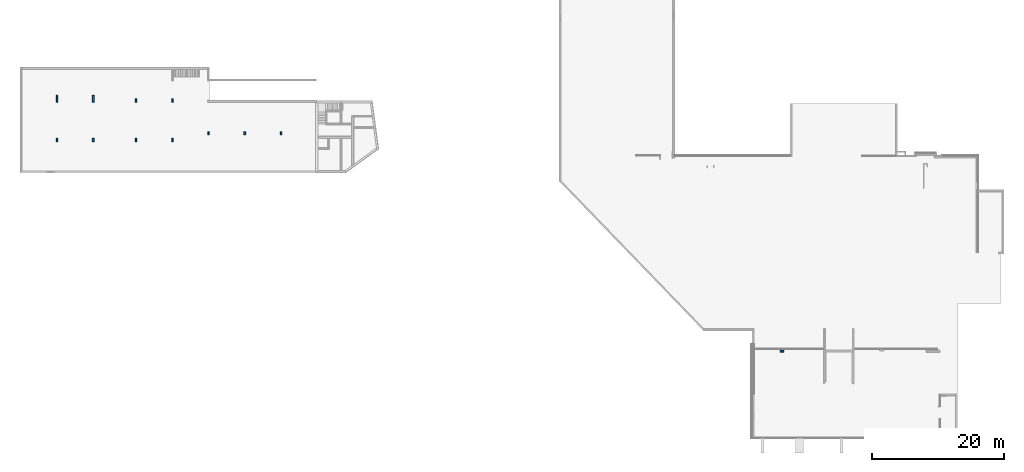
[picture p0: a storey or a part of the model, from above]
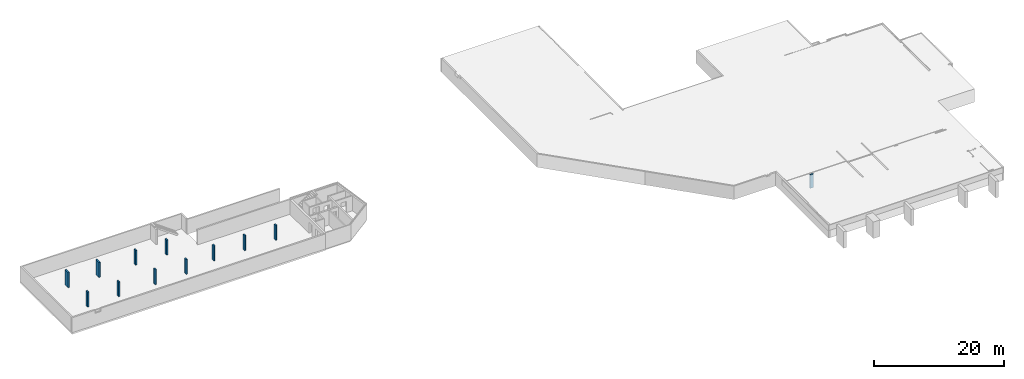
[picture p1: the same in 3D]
Properties of the parts of a building model (IFC2X3), part 1 of 4

# File
Description: ViewDefinition [CoordinationView_V2.0]
File name: X:\Daten\1-Firma\0-bv\Clemenz\18-019_Kandel Rheinstrasse\C a d\Transfair-DATEN\Test_181112.ifc
Time: 2018-11-12T08:55:23
Written by: EDMsix Version 2.0100.03 Feb 3 2016
Made in: Allplan 2017.1 19.09.2018 - 11:13:58

# IfcBuildingStorey (5)
In: Gebäude
Name | Elevation (mm)
Allgemein
KG.- Grundriss | -3205
EG.- Grundriss | -200
OG.- Grundriss | 2730
DG.- Grundriss | 5580

# IfcSpace (170)
InteriorOrExteriorSpace: INTERNAL
Allplan Attributes - Einheit: m²; Umschließungsart: a; Flächenart_DIN277: N; Flächenart_Wohnfläche: 1; BauNVO_Anrechnung_auf_GR: 0; Ortscode_Geschoßbezeichnung: 0-UG; BauNVO_Anrechnung_auf_GF: 0; Raum unter Treppe (Wohnfl erst ab 2m): 0; Faktor_Wohnfläche_Raum: 1; Faktor_DIN277: 1
Name | In | Description | LongName | Allright_Bauteil_ID | Nutzungsart_Din277 | Text2 | NOI_UUID
2-U.00.04 | KG.- Grundriss | Anstrich | Trockenraum | 0110Rau0000000851 | NF | Betonboden glatt | b6d4dd52-af4a-4a99-80c0-3d315f88db4b--851
1-U.01.07 | KG.- Grundriss | Anstrich | Müllraum | 0110Rau0000000320 | NF | Betonboden glatt | b6d4dd52-af4a-4a99-80c0-3d315f88db4b--320
1-U.00.03 | KG.- Grundriss | Anstrich | Schleuse1 | 0110Rau0000000425 | VF | Betonboden glatt | b6d4dd52-af4a-4a99-80c0-3d315f88db4b--425
0-U.00.01 | KG.- Grundriss | Anstrich | Tiefgarage | 0110Rau0000000002 | NF | Betonboden glatt | b6d4dd52-af4a-4a99-80c0-3d315f88db4b--2
0-U.00.02-2 | KG.- Grundriss | Anstrich | HAR | 0110Rau0000000212 | TF | Betonboden glatt | b6d4dd52-af4a-4a99-80c0-3d315f88db4b--212
1-U.00.01 | KG.- Grundriss | Werksteinbelag | Treppenhaus1 | 0110Rau0000000524 | VF | schw.Estrich | b6d4dd52-af4a-4a99-80c0-3d315f88db4b--524 | Allplan Attributes - Text3: Dämmung
1-U.00.02 | KG.- Grundriss | Belag | Aufzug1 | 0110Rau0000000629 | VF | schw.Estrich | b6d4dd52-af4a-4a99-80c0-3d315f88db4b--629 | Allplan Attributes - Text3: Trittschalld.
2-U.00.05 | KG.- Grundriss | Anstrich | Abstellraum | 0110Rau0000001094 | NF | Betonboden glatt | b6d4dd52-af4a-4a99-80c0-3d315f88db4b--1094
0-U.00.02-1 | KG.- Grundriss | Anstrich | Haustechnik | 0110Rau0000000107 | TF | Betonboden glatt | b6d4dd52-af4a-4a99-80c0-3d315f88db4b--107
0-U.00.02-2 | KG.- Grundriss | Anstrich | Haustechnik 2 | 0117Rau0781534050 | TF | Betonboden glatt | 09ef5a79-666f-4d65-ae11-371ec0050284--781534050 | Allplan Attributes - Faktor: 1
0-U.00.03 | KG.- Grundriss | Anstrich | Haustechnik 3 | 0117Rau0781533207 | TF | Betonboden glatt | 09ef5a79-666f-4d65-ae11-371ec0050284--781533207 | Allplan Attributes - Faktor: 1
0-U.00.02-1 | KG.- Grundriss | Anstrich | Haustechnik 1 | 0117Rau0781533084 | TF | Betonboden glatt | 09ef5a79-666f-4d65-ae11-371ec0050284--781533084 | Allplan Attributes - Faktor: 1
1-U.01.07 | KG.- Grundriss | Anstrich | Hausmeister | 0117Rau0781533926 | NF | schw.Estrich | 09ef5a79-666f-4d65-ae11-371ec0050284--781533926 | Allplan Attributes - Text3: Dämmung; Faktor: 1; Text4: Betonboden
1-U.00.02 | KG.- Grundriss | Belag | Aufzug1 | 0117Rau0781533922 | VF | schw.Estrich | 09ef5a79-666f-4d65-ae11-371ec0050284--781533922 | Allplan Attributes - Text3: Trittschalld.; Faktor: 1
1-U.00.01 | KG.- Grundriss | Werksteinbelag | Treppenhaus1 | 0117Rau0781533905 | VF | schw.Estrich | 09ef5a79-666f-4d65-ae11-371ec0050284--781533905 | Allplan Attributes - Text3: Dämmung; Faktor: 1
1-U.00.03 | KG.- Grundriss | schw.Estrich | Schleuse1 | 0117Rau0781533321 | VF | Dämmung | 09ef5a79-666f-4d65-ae11-371ec0050284--781533321 | Allplan Attributes - Faktor: 1
1-U.00.04 | KG.- Grundriss | Anstrich | Flur | 0117Rau0781533300 | VF | Betonboden glatt | 09ef5a79-666f-4d65-ae11-371ec0050284--781533300 | Allplan Attributes - Faktor: 1
0-U.00.02 | KG.- Grundriss | Anstrich | Müllraum | 0117Rau0781533278 | NF | Betonboden glatt | 09ef5a79-666f-4d65-ae11-371ec0050284--781533278 | Allplan Attributes - Faktor: 1
2-U.00.02 | KG.- Grundriss | Belag | Aufzug2 | 0117Rau0781533884 | VF | schw.Estrich | 09ef5a79-666f-4d65-ae11-371ec0050284--781533884 | Allplan Attributes - Text3: Trittschalld.; Faktor: 1
2-U.00.03 | KG.- Grundriss | schw.Estrich | Schleuse2 | 0117Rau0781533559 | VF | Dämmung | 09ef5a79-666f-4d65-ae11-371ec0050284--781533559 | Allplan Attributes - Faktor: 1
2-U.00.01 | KG.- Grundriss | Werksteinbelag | Treppenhaus2 | 0117Rau0781533556 | VF | schw.Estrich | 09ef5a79-666f-4d65-ae11-371ec0050284--781533556 | Allplan Attributes - Text3: Dämmung; Faktor: 1
2-U.00.04 | KG.- Grundriss | Anstrich | Abstellraum | 0117Rau0781533294 | NF | Betonboden glatt | 09ef5a79-666f-4d65-ae11-371ec0050284--781533294 | Allplan Attributes - Faktor: 1
2-U.00.05 | KG.- Grundriss | Anstrich | Flur | 0117Rau0781533275 | VF | Betonboden glatt | 09ef5a79-666f-4d65-ae11-371ec0050284--781533275 | Allplan Attributes - Faktor: 1
2-U.00.07 | KG.- Grundriss | schw.Estrich | Technik2 | 0117Rau0781533135 | TF | Dämmung | 09ef5a79-666f-4d65-ae11-371ec0050284--781533135 | Allplan Attributes - Faktor: 1
2-U.00.06 | KG.- Grundriss | Anstrich | Flur | 0117Rau0781533063 | VF | Betonboden glatt | 09ef5a79-666f-4d65-ae11-371ec0050284--781533063 | Allplan Attributes - Faktor: 1
3-U.00.01 | KG.- Grundriss | Werksteinbelag | Treppenhaus3 | 0117Rau0781533430 | VF | schw.Estrich | 09ef5a79-666f-4d65-ae11-371ec0050284--781533430 | Allplan Attributes - Text3: Dämmung; Faktor: 1
3-U.00.04 | KG.- Grundriss | schw.Estrich | Abstellraum | 0117Rau0781533296 | NF | Dämmung | 09ef5a79-666f-4d65-ae11-371ec0050284--781533296 | Allplan Attributes - Faktor: 1
3-U.00.06 | KG.- Grundriss | Anstrich | Flur | 0117Rau0781533292 | VF | Betonboden glatt | 09ef5a79-666f-4d65-ae11-371ec0050284--781533292 | Allplan Attributes - Faktor: 1
3-U.00.05a | KG.- Grundriss | Anstrich | Heizungs-Verteilung | 0117Rau0781533193 | TF | Betonboden glatt | 09ef5a79-666f-4d65-ae11-371ec0050284--781533193 | Allplan Attributes - Faktor: 1
3-U.00.05 | KG.- Grundriss | Anstrich | Technik3 | 0117Rau0781533145 | TF | Betonboden glatt | 09ef5a79-666f-4d65-ae11-371ec0050284--781533145 | Allplan Attributes - Faktor: 1
3-U.00.02 | KG.- Grundriss | Belag | Aufzug3 | 0117Rau0781532964 | VF | schw.Estrich | 09ef5a79-666f-4d65-ae11-371ec0050284--781532964 | Allplan Attributes - Text3: Trittschalld.; Faktor: 1
3-U.00.03 | KG.- Grundriss | schw.Estrich | Schleuse3 | 0117Rau0781532952 | VF | Dämmung | 09ef5a79-666f-4d65-ae11-371ec0050284--781532952 | Allplan Attributes - Faktor: 1
3-U.12 | KG.- Grundriss | Anstrich | Keller3.12 | 0117Rau0781533157 | NF | Betonboden glatt | 09ef5a79-666f-4d65-ae11-371ec0050284--781533157 | Allplan Attributes - Faktor: 1
3-U.13 | KG.- Grundriss | Anstrich | Keller3.13 | 0117Rau0781533154 | NF | Betonboden glatt | 09ef5a79-666f-4d65-ae11-371ec0050284--781533154 | Allplan Attributes - Faktor: 1
3-U.11 | KG.- Grundriss | Anstrich | Keller3.11 | 0117Rau0781533151 | NF | Betonboden glatt | 09ef5a79-666f-4d65-ae11-371ec0050284--781533151 | Allplan Attributes - Faktor: 1
3-U.10 | KG.- Grundriss | Anstrich | Keller3.10 | 0117Rau0781533148 | NF | Betonboden glatt | 09ef5a79-666f-4d65-ae11-371ec0050284--781533148 | Allplan Attributes - Faktor: 1
3-U.01 | KG.- Grundriss | Anstrich | Keller3.01 | 0117Rau0781533081 | NF | Betonboden glatt | 09ef5a79-666f-4d65-ae11-371ec0050284--781533081 | Allplan Attributes - Faktor: 1
3-U.02 | KG.- Grundriss | Anstrich | Keller3.02 | 0117Rau0781533072 | NF | Betonboden glatt | 09ef5a79-666f-4d65-ae11-371ec0050284--781533072 | Allplan Attributes - Faktor: 1
3-U.09 | KG.- Grundriss | Anstrich | Keller3.09 | 0117Rau0781533027 | NF | Betonboden glatt | 09ef5a79-666f-4d65-ae11-371ec0050284--781533027 | Allplan Attributes - Faktor: 1
3-U.08 | KG.- Grundriss | Anstrich | Keller3.08 | 0117Rau0781533018 | NF | Betonboden glatt | 09ef5a79-666f-4d65-ae11-371ec0050284--781533018 | Allplan Attributes - Faktor: 1
3-U.07 | KG.- Grundriss | Anstrich | Keller3.07 | 0117Rau0781533009 | NF | Betonboden glatt | 09ef5a79-666f-4d65-ae11-371ec0050284--781533009 | Allplan Attributes - Faktor: 1
3-U.06 | KG.- Grundriss | Anstrich | Keller3.06 | 0117Rau0781533000 | NF | Betonboden glatt | 09ef5a79-666f-4d65-ae11-371ec0050284--781533000 | Allplan Attributes - Faktor: 1
3-U.05 | KG.- Grundriss | Anstrich | Keller3.05 | 0117Rau0781532991 | NF | Betonboden glatt | 09ef5a79-666f-4d65-ae11-371ec0050284--781532991 | Allplan Attributes - Faktor: 1
3-U.03 | KG.- Grundriss | Anstrich | Keller3.03 | 0117Rau0781532982 | NF | Betonboden glatt | 09ef5a79-666f-4d65-ae11-371ec0050284--781532982 | Allplan Attributes - Faktor: 1
3-U.04 | KG.- Grundriss | Anstrich | Keller3.04 | 0117Rau0781532973 | NF | Betonboden glatt | 09ef5a79-666f-4d65-ae11-371ec0050284--781532973 | Allplan Attributes - Faktor: 1
2-U.01 | KG.- Grundriss | schw.Estrich | Keller2.01 | 0117Rau0781533265 | NF | Dämmung | 09ef5a79-666f-4d65-ae11-371ec0050284--781533265 | Allplan Attributes - Faktor: 1
2-U.03 | KG.- Grundriss | Anstrich | Keller2.03 | 0117Rau0781533262 | NF | Betonboden glatt | 09ef5a79-666f-4d65-ae11-371ec0050284--781533262 | Allplan Attributes - Faktor: 1
2-U.04 | KG.- Grundriss | Anstrich | Keller2.04 | 0117Rau0781533259 | NF | Betonboden glatt | 09ef5a79-666f-4d65-ae11-371ec0050284--781533259 | Allplan Attributes - Faktor: 1
2-U.07 | KG.- Grundriss | Anstrich | Keller2.07 | 0117Rau0781533132 | NF | Betonboden glatt | 09ef5a79-666f-4d65-ae11-371ec0050284--781533132 | Allplan Attributes - Faktor: 1
2-U.08 | KG.- Grundriss | Anstrich | Keller2.08 | 0117Rau0781533129 | NF | Betonboden glatt | 09ef5a79-666f-4d65-ae11-371ec0050284--781533129 | Allplan Attributes - Faktor: 1
2-U.11 | KG.- Grundriss | schw.Estrich | Keller2.11 | 0117Rau0781533126 | NF | Dämmung | 09ef5a79-666f-4d65-ae11-371ec0050284--781533126 | Allplan Attributes - Faktor: 1
2-U.10 | KG.- Grundriss | Anstrich | Keller2.10 | 0117Rau0781533123 | NF | Betonboden glatt | 09ef5a79-666f-4d65-ae11-371ec0050284--781533123 | Allplan Attributes - Faktor: 1
2-U.09 | KG.- Grundriss | Anstrich | Keller2.09 | 0117Rau0781533098 | NF | Betonboden glatt | 09ef5a79-666f-4d65-ae11-371ec0050284--781533098 | Allplan Attributes - Faktor: 1
2-U.02 | KG.- Grundriss | Anstrich | Keller2.02 | 0117Rau0781532961 | NF | Betonboden glatt | 09ef5a79-666f-4d65-ae11-371ec0050284--781532961 | Allplan Attributes - Faktor: 1
2-U.06 | KG.- Grundriss | Anstrich | Keller2.06 | 0117Rau0781532958 | NF | Betonboden glatt | 09ef5a79-666f-4d65-ae11-371ec0050284--781532958 | Allplan Attributes - Faktor: 1
2-U.05 | KG.- Grundriss | Anstrich | Keller2.05 | 0117Rau0781532955 | NF | Betonboden glatt | 09ef5a79-666f-4d65-ae11-371ec0050284--781532955 | Allplan Attributes - Faktor: 1
1-U.08 | KG.- Grundriss | Anstrich | Keller1.08 | 0117Rau0781533407 | NF | Betonboden glatt | 09ef5a79-666f-4d65-ae11-371ec0050284--781533407 | Allplan Attributes - Faktor: 1
1-U.09 | KG.- Grundriss | Anstrich | Keller1.09 | 0117Rau0781533404 | NF | Betonboden glatt | 09ef5a79-666f-4d65-ae11-371ec0050284--781533404 | Allplan Attributes - Faktor: 1
1-U.10 | KG.- Grundriss | Anstrich | Keller1.10 | 0117Rau0781533401 | NF | Betonboden glatt | 09ef5a79-666f-4d65-ae11-371ec0050284--781533401 | Allplan Attributes - Faktor: 1
1-U.11 | KG.- Grundriss | Anstrich | Keller1.11 | 0117Rau0781533383 | NF | Betonboden glatt | 09ef5a79-666f-4d65-ae11-371ec0050284--781533383 | Allplan Attributes - Faktor: 1
1-U.01 | KG.- Grundriss | Anstrich | Keller1.01 | 0117Rau0781533060 | NF | Betonboden glatt | 09ef5a79-666f-4d65-ae11-371ec0050284--781533060 | Allplan Attributes - Faktor: 1
1-U.02 | KG.- Grundriss | Anstrich | Keller1.02 | 0117Rau0781533057 | NF | Betonboden glatt | 09ef5a79-666f-4d65-ae11-371ec0050284--781533057 | Allplan Attributes - Faktor: 1
1-U.03 | KG.- Grundriss | Anstrich | Keller1.03 | 0117Rau0781533054 | NF | Betonboden glatt | 09ef5a79-666f-4d65-ae11-371ec0050284--781533054 | Allplan Attributes - Faktor: 1
1-U.04 | KG.- Grundriss | Anstrich | Keller1.04 | 0117Rau0781533051 | NF | Betonboden glatt | 09ef5a79-666f-4d65-ae11-371ec0050284--781533051 | Allplan Attributes - Faktor: 1
1-U.05 | KG.- Grundriss | Anstrich | Keller1.05 | 0117Rau0781533048 | NF | Betonboden glatt | 09ef5a79-666f-4d65-ae11-371ec0050284--781533048 | Allplan Attributes - Faktor: 1
1-U.14 | KG.- Grundriss | Anstrich | Keller1.14 | 0117Rau0781533045 | NF | Betonboden glatt | 09ef5a79-666f-4d65-ae11-371ec0050284--781533045 | Allplan Attributes - Faktor: 1
1-U.17 | KG.- Grundriss | Anstrich | Keller1.17 | 0117Rau0781533042 | NF | Betonboden glatt | 09ef5a79-666f-4d65-ae11-371ec0050284--781533042 | Allplan Attributes - Faktor: 1
1-U.16 | KG.- Grundriss | Anstrich | Keller1.16 | 0117Rau0781533039 | NF | Betonboden glatt | 09ef5a79-666f-4d65-ae11-371ec0050284--781533039 | Allplan Attributes - Faktor: 1
1-U.15 | KG.- Grundriss | Anstrich | Keller1.15 | 0117Rau0781533036 | NF | Betonboden glatt | 09ef5a79-666f-4d65-ae11-371ec0050284--781533036 | Allplan Attributes - Faktor: 1
1-U.13 | KG.- Grundriss | Anstrich | Keller1.13 | 0117Rau0781533033 | NF | Betonboden glatt | 09ef5a79-666f-4d65-ae11-371ec0050284--781533033 | Allplan Attributes - Faktor: 1
1-U.12 | KG.- Grundriss | Anstrich | Keller1.12 | 0117Rau0781533030 | NF | Betonboden glatt | 09ef5a79-666f-4d65-ae11-371ec0050284--781533030 | Allplan Attributes - Faktor: 1
0-U.00.01 | KG.- Grundriss | Anstrich | Tiefgarage | 0117Rau0781533466 | NF | Betonboden glatt | 09ef5a79-666f-4d65-ae11-371ec0050284--781533466 | Allplan Attributes - Faktor: 1
1-0.00.02 | EG.- Grundriss | Belag | Aufzug1 | 0210Rau0000001110 | VF | schw.Estrich | cb6ca373-0bca-4cb3-851c-22c560fc348a--1110 | Allplan Attributes - Text3: Trittschalld.
1-0.00.01 | EG.- Grundriss | Werksteinbelag | Treppenhaus1 | 0210Rau0000001113 | VF | schw.Estrich | cb6ca373-0bca-4cb3-851c-22c560fc348a--1113 | Allplan Attributes - Text3: Dämmung
1-0.00.28 | EG.- Grundriss | Anstrich | Abstellraum | 0210Rau0000004021 | NF | Betonboden glatt | cb6ca373-0bca-4cb3-851c-22c560fc348a--4021
1-0.00.09 | EG.- Grundriss | Anstrich | Raum | 0210Rau0000001909 | NF | Betonboden glatt | cb6ca373-0bca-4cb3-851c-22c560fc348a--1909
1-0.00.08 | EG.- Grundriss | Anstrich | Raum | 0210Rau0000001786 | NF | Betonboden glatt | cb6ca373-0bca-4cb3-851c-22c560fc348a--1786
1-0.00.05 | EG.- Grundriss | Anstrich | WC | 0210Rau0000001107 | NF | Betonboden glatt | cb6ca373-0bca-4cb3-851c-22c560fc348a--1107
1-0.00.07 | EG.- Grundriss | Anstrich | Teeküche | 0210Rau0000001687 | NF | Betonboden glatt | cb6ca373-0bca-4cb3-851c-22c560fc348a--1687
1-0.00.06 | EG.- Grundriss | Anstrich | Bad | 0210Rau0000001588 | NF | Betonboden glatt | cb6ca373-0bca-4cb3-851c-22c560fc348a--1588
1-0.00.05 | EG.- Grundriss | Anstrich | Wohnen/Essen/Kochen | 0210Rau0000001441 | NF | Betonboden glatt | cb6ca373-0bca-4cb3-851c-22c560fc348a--1441
1-0.00.05 | EG.- Grundriss | Anstrich | Abstr. | 0210Rau0000001408 | NF | Betonboden glatt | cb6ca373-0bca-4cb3-851c-22c560fc348a--1408
1-0.00.13 | EG.- Grundriss | Anstrich | Ankleide | 0210Rau0000002359 | NF | Betonboden glatt | cb6ca373-0bca-4cb3-851c-22c560fc348a--2359
1-0.00.11 | EG.- Grundriss | Anstrich | Bad | 0210Rau0000002131 | NF | Betonboden glatt | cb6ca373-0bca-4cb3-851c-22c560fc348a--2131
1-0.00.01 | EG.- Grundriss | Werksteinbelag | Treppenhaus2 | 0210Rau0000004441 | VF | schw.Estrich | cb6ca373-0bca-4cb3-851c-22c560fc348a--4441 | Allplan Attributes - Text3: Dämmung
1-0.00.10 | EG.- Grundriss | Anstrich | Flur | 0210Rau0000002032 | NF | Betonboden glatt | cb6ca373-0bca-4cb3-851c-22c560fc348a--2032
1-0.00.12 | EG.- Grundriss | Anstrich | Wohnen/Essen/Kochen | 0210Rau0000002230 | NF | Betonboden glatt | cb6ca373-0bca-4cb3-851c-22c560fc348a--2230
1-0.00.15 | EG.- Grundriss | Anstrich | Schlafen | 0210Rau0000002557 | NF | Betonboden glatt | cb6ca373-0bca-4cb3-851c-22c560fc348a--2557
1-0.00.19 | EG.- Grundriss | Anstrich | Flur | 0210Rau0000003001 | NF | Betonboden glatt | cb6ca373-0bca-4cb3-851c-22c560fc348a--3001
1-0.00.16 | EG.- Grundriss | Anstrich | Bad | 0210Rau0000002668 | NF | Betonboden glatt | cb6ca373-0bca-4cb3-851c-22c560fc348a--2668
1-0.00.17 | EG.- Grundriss | Anstrich | Schlafen | 0210Rau0000002767 | NF | Betonboden glatt | cb6ca373-0bca-4cb3-851c-22c560fc348a--2767
1-0.00.18 | EG.- Grundriss | Anstrich | Wohnen/Essen/Kochen | 0210Rau0000002884 | NF | Betonboden glatt | cb6ca373-0bca-4cb3-851c-22c560fc348a--2884
1-0.00.24 | EG.- Grundriss | Anstrich | Wohnen/Essen/Kochen | 0210Rau0000003514 | NF | Betonboden glatt | cb6ca373-0bca-4cb3-851c-22c560fc348a--3514
1-0.00.21 | EG.- Grundriss | Anstrich | Schlafen | 0210Rau0000003199 | NF | Betonboden glatt | cb6ca373-0bca-4cb3-851c-22c560fc348a--3199
1-0.00.20 | EG.- Grundriss | Anstrich | Flur | 0210Rau0000003100 | NF | Betonboden glatt | cb6ca373-0bca-4cb3-851c-22c560fc348a--3100
1-0.00.23 | EG.- Grundriss | Anstrich | Bad | 0210Rau0000003415 | NF | Betonboden glatt | cb6ca373-0bca-4cb3-851c-22c560fc348a--3415
1-0.00.22 | EG.- Grundriss | Anstrich | Abstr. | 0210Rau0000003316 | NF | Betonboden glatt | cb6ca373-0bca-4cb3-851c-22c560fc348a--3316
1-0.00.14 | EG.- Grundriss | Anstrich | Abstr. | 0210Rau0000002458 | NF | Betonboden glatt | cb6ca373-0bca-4cb3-851c-22c560fc348a--2458
1-0.00.25 | EG.- Grundriss | Anstrich | WC | 0210Rau0000003660 | NF | Betonboden glatt | cb6ca373-0bca-4cb3-851c-22c560fc348a--3660
1-0.00.27 | EG.- Grundriss | Anstrich | Kochen | 0210Rau0000004889 | NF | Betonboden glatt | cb6ca373-0bca-4cb3-851c-22c560fc348a--4889
1-0.00.30 | EG.- Grundriss | Anstrich | Wohnen/Essen | 0210Rau0000004219 | NF | Betonboden glatt | cb6ca373-0bca-4cb3-851c-22c560fc348a--4219
1-0.00.27 | EG.- Grundriss | Anstrich | Wohnen/Essen | 0210Rau0000003880 | NF | Betonboden glatt | cb6ca373-0bca-4cb3-851c-22c560fc348a--3880
1-0.00.29 | EG.- Grundriss | Anstrich | Kochen | 0210Rau0000004120 | NF | Betonboden glatt | cb6ca373-0bca-4cb3-851c-22c560fc348a--4120
1-0.00.32 | EG.- Grundriss | Anstrich | Abstr. | 0210Rau0000005164 | NF | Betonboden glatt | cb6ca373-0bca-4cb3-851c-22c560fc348a--5164
1-0.00.31 | EG.- Grundriss | Anstrich | Abstr. | 0210Rau0000005065 | NF | Betonboden glatt | cb6ca373-0bca-4cb3-851c-22c560fc348a--5065
1-0.00.31 | EG.- Grundriss | Anstrich | Diele | 0210Rau0000004330 | NF | Betonboden glatt | cb6ca373-0bca-4cb3-851c-22c560fc348a--4330
1-0.00.26 | EG.- Grundriss | Anstrich | Diele | 0210Rau0000003781 | NF | Betonboden glatt | cb6ca373-0bca-4cb3-851c-22c560fc348a--3781
1-0.00.14 | OG.- Grundriss | Anstrich | Abstr. | 0310Rau0000005811 | NF | Betonboden glatt | c8e704be-ccd8-4ce4-b42b-70ee46b7e8a9--5811
1-0.00.22 | OG.- Grundriss | Anstrich | Abstr. | 0310Rau0000005788 | NF | Betonboden glatt | c8e704be-ccd8-4ce4-b42b-70ee46b7e8a9--5788
1-0.00.23 | OG.- Grundriss | Anstrich | Bad | 0310Rau0000005765 | NF | Betonboden glatt | c8e704be-ccd8-4ce4-b42b-70ee46b7e8a9--5765
1-0.00.20 | OG.- Grundriss | Anstrich | Flur | 0310Rau0000005762 | NF | Betonboden glatt | c8e704be-ccd8-4ce4-b42b-70ee46b7e8a9--5762
1-0.00.21 | OG.- Grundriss | Anstrich | Schlafen | 0310Rau0000005719 | NF | Betonboden glatt | c8e704be-ccd8-4ce4-b42b-70ee46b7e8a9--5719
1-0.00.24 | OG.- Grundriss | Anstrich | Wohnen/Essen/Kochen | 0310Rau0000005696 | NF | Betonboden glatt | c8e704be-ccd8-4ce4-b42b-70ee46b7e8a9--5696
1-0.00.18 | OG.- Grundriss | Anstrich | Wohnen/Essen/Kochen | 0310Rau0000005673 | NF | Betonboden glatt | c8e704be-ccd8-4ce4-b42b-70ee46b7e8a9--5673
1-0.00.17 | OG.- Grundriss | Anstrich | Schlafen | 0310Rau0000005650 | NF | Betonboden glatt | c8e704be-ccd8-4ce4-b42b-70ee46b7e8a9--5650
1-0.00.16 | OG.- Grundriss | Anstrich | Bad | 0310Rau0000005627 | NF | Betonboden glatt | c8e704be-ccd8-4ce4-b42b-70ee46b7e8a9--5627
1-0.00.19 | OG.- Grundriss | Anstrich | Flur | 0310Rau0000005604 | NF | Betonboden glatt | c8e704be-ccd8-4ce4-b42b-70ee46b7e8a9--5604
1-0.00.15 | OG.- Grundriss | Anstrich | Schlafen | 0310Rau0000005581 | NF | Betonboden glatt | c8e704be-ccd8-4ce4-b42b-70ee46b7e8a9--5581
1-0.00.12 | OG.- Grundriss | Anstrich | Wohnen/Essen/Kochen | 0310Rau0000005558 | NF | Betonboden glatt | c8e704be-ccd8-4ce4-b42b-70ee46b7e8a9--5558
1-0.00.10 | OG.- Grundriss | Anstrich | Flur | 0310Rau0000005535 | NF | Betonboden glatt | c8e704be-ccd8-4ce4-b42b-70ee46b7e8a9--5535
1-0.00.01 | OG.- Grundriss | Werksteinbelag | Treppenhaus2 | 0310Rau0000005512 | VF | schw.Estrich | c8e704be-ccd8-4ce4-b42b-70ee46b7e8a9--5512 | Allplan Attributes - Text3: Dämmung
1-0.00.11 | OG.- Grundriss | Anstrich | Bad | 0310Rau0000005489 | NF | Betonboden glatt | c8e704be-ccd8-4ce4-b42b-70ee46b7e8a9--5489
1-0.00.13 | OG.- Grundriss | Anstrich | Ankleide | 0310Rau0000005466 | NF | Betonboden glatt | c8e704be-ccd8-4ce4-b42b-70ee46b7e8a9--5466
1-0.00.05 | OG.- Grundriss | Anstrich | Abstr. | 0310Rau0000005463 | NF | Betonboden glatt | c8e704be-ccd8-4ce4-b42b-70ee46b7e8a9--5463
1-0.00.05 | OG.- Grundriss | Anstrich | Wohnen/Essen/Kochen | 0310Rau0000005420 | NF | Betonboden glatt | c8e704be-ccd8-4ce4-b42b-70ee46b7e8a9--5420
1-0.00.06 | OG.- Grundriss | Anstrich | Bad | 0310Rau0000005397 | NF | Betonboden glatt | c8e704be-ccd8-4ce4-b42b-70ee46b7e8a9--5397
1-0.00.09 | OG.- Grundriss | Anstrich | Raum | 0310Rau0000005305 | NF | Betonboden glatt | c8e704be-ccd8-4ce4-b42b-70ee46b7e8a9--5305
1-0.00.01 | OG.- Grundriss | Werksteinbelag | Treppenhaus1 | 0310Rau0000005279 | VF | schw.Estrich | c8e704be-ccd8-4ce4-b42b-70ee46b7e8a9--5279 | Allplan Attributes - Text3: Dämmung
1-0.00.02 | OG.- Grundriss | Belag | Aufzug1 | 0310Rau0000005257 | VF | schw.Estrich | c8e704be-ccd8-4ce4-b42b-70ee46b7e8a9--5257 | Allplan Attributes - Text3: Trittschalld.
1-0.00.07 | OG.- Grundriss | Anstrich | Bad | 0310Rau0000005374 | NF | Betonboden glatt | c8e704be-ccd8-4ce4-b42b-70ee46b7e8a9--5374
1-0.00.05 | OG.- Grundriss | Anstrich | Abstr. | 0310Rau0000005371 | NF | Betonboden glatt | c8e704be-ccd8-4ce4-b42b-70ee46b7e8a9--5371
1-0.00.08 | OG.- Grundriss | Anstrich | Raum | 0310Rau0000005328 | NF | Betonboden glatt | c8e704be-ccd8-4ce4-b42b-70ee46b7e8a9--5328
1-0.00.31 | OG.- Grundriss | Anstrich | Flur | 0310Rau0000005999 | NF | Betonboden glatt | c8e704be-ccd8-4ce4-b42b-70ee46b7e8a9--5999
1-0.00.29 | OG.- Grundriss | Anstrich | Dusche | 0310Rau0000005930 | NF | Betonboden glatt | c8e704be-ccd8-4ce4-b42b-70ee46b7e8a9--5930
1-0.00.30 | OG.- Grundriss | Anstrich | Kind1 | 0310Rau0000006716 | NF | Betonboden glatt | c8e704be-ccd8-4ce4-b42b-70ee46b7e8a9--6716
1-0.00.30 | OG.- Grundriss | Anstrich | Kind2 | 0310Rau0000005884 | NF | Betonboden glatt | c8e704be-ccd8-4ce4-b42b-70ee46b7e8a9--5884
1-0.00.30 | OG.- Grundriss | Anstrich | Kind2 | 0310Rau0000006992 | NF | Betonboden glatt | c8e704be-ccd8-4ce4-b42b-70ee46b7e8a9--6992
1-0.00.30 | OG.- Grundriss | Anstrich | Kind1 | 0310Rau0000006970 | NF | Betonboden glatt | c8e704be-ccd8-4ce4-b42b-70ee46b7e8a9--6970
1-0.00.29 | OG.- Grundriss | Anstrich | Dusche | 0310Rau0000006968 | NF | Betonboden glatt | c8e704be-ccd8-4ce4-b42b-70ee46b7e8a9--6968
1-0.00.31 | OG.- Grundriss | Anstrich | Flur | 0310Rau0000006946 | NF | Betonboden glatt | c8e704be-ccd8-4ce4-b42b-70ee46b7e8a9--6946
1-0.00.11 | DG.- Grundriss | Anstrich | Bad | 0510Rau0000007544 | NF | Betonboden glatt | 5b11ceff-7c37-4271-a11e-d8302deba2a0--7544
1-0.00.01 | DG.- Grundriss | Werksteinbelag | Treppenhaus2 | 0510Rau0000007541 | VF | schw.Estrich | 5b11ceff-7c37-4271-a11e-d8302deba2a0--7541 | Allplan Attributes - Text3: Dämmung
1-0.00.30 | DG.- Grundriss | Anstrich | Kind1 | 0510Rau0000007728 | NF | Betonboden glatt | 5b11ceff-7c37-4271-a11e-d8302deba2a0--7728
1-0.00.30 | DG.- Grundriss | Anstrich | Kind1 | 0510Rau0000007679 | NF | Betonboden glatt | 5b11ceff-7c37-4271-a11e-d8302deba2a0--7679
1-0.00.31 | DG.- Grundriss | Anstrich | Flur | 0510Rau0000007734 | NF | Betonboden glatt | 5b11ceff-7c37-4271-a11e-d8302deba2a0--7734
1-0.00.31 | DG.- Grundriss | Anstrich | Flur | 0510Rau0000007653 | NF | Betonboden glatt | 5b11ceff-7c37-4271-a11e-d8302deba2a0--7653
1-0.00.29 | DG.- Grundriss | Anstrich | Dusche | 0510Rau0000007676 | NF | Betonboden glatt | 5b11ceff-7c37-4271-a11e-d8302deba2a0--7676
1-0.00.29 | DG.- Grundriss | Anstrich | Dusche | 0510Rau0000007731 | NF | Betonboden glatt | 5b11ceff-7c37-4271-a11e-d8302deba2a0--7731
1-0.00.14 | DG.- Grundriss | Anstrich | Abstr. | 0510Rau0000007502 | NF | Betonboden glatt | 5b11ceff-7c37-4271-a11e-d8302deba2a0--7502
1-0.00.15 | DG.- Grundriss | Anstrich | Schlafen | 0510Rau0000007532 | NF | Betonboden glatt | 5b11ceff-7c37-4271-a11e-d8302deba2a0--7532
1-0.00.21 | DG.- Grundriss | Anstrich | Dachterrasse ½ | 0510Rau0000007514 | NF | Betonboden glatt | 5b11ceff-7c37-4271-a11e-d8302deba2a0--7514
1-0.00.22 | DG.- Grundriss | Anstrich | Abstr. | 0510Rau0000007505 | NF | Betonboden glatt | 5b11ceff-7c37-4271-a11e-d8302deba2a0--7505
1-0.00.17 | DG.- Grundriss | Anstrich | Schlafen | 0510Rau0000007523 | NF | Betonboden glatt | 5b11ceff-7c37-4271-a11e-d8302deba2a0--7523
1-0.00.19 | DG.- Grundriss | Anstrich | Flur | 0510Rau0000007529 | NF | Betonboden glatt | 5b11ceff-7c37-4271-a11e-d8302deba2a0--7529
1-0.00.23 | DG.- Grundriss | Anstrich | Bad | 0510Rau0000007508 | NF | Betonboden glatt | 5b11ceff-7c37-4271-a11e-d8302deba2a0--7508
1-0.00.24 | DG.- Grundriss | Anstrich | Wohnen/Essen/Kochen | 0510Rau0000007517 | NF | Betonboden glatt | 5b11ceff-7c37-4271-a11e-d8302deba2a0--7517
1-0.00.22 | DG.- Grundriss | Anstrich | Kind | 0510Rau0000009184 | NF | Betonboden glatt | 5b11ceff-7c37-4271-a11e-d8302deba2a0--9184
1-0.00.12 | DG.- Grundriss | Anstrich | Wohnen/Essen/Kochen | 0510Rau0000007535 | NF | Betonboden glatt | 5b11ceff-7c37-4271-a11e-d8302deba2a0--7535
1-0.00.10 | DG.- Grundriss | Anstrich | Flur | 0510Rau0000007538 | NF | Betonboden glatt | 5b11ceff-7c37-4271-a11e-d8302deba2a0--7538
1-0.00.06 | DG.- Grundriss | Anstrich | Bad | 0510Rau0000007556 | NF | Betonboden glatt | 5b11ceff-7c37-4271-a11e-d8302deba2a0--7556
1-0.00.05 | DG.- Grundriss | Anstrich | Wohnen/Essen/Kochen | 0510Rau0000007553 | NF | Betonboden glatt | 5b11ceff-7c37-4271-a11e-d8302deba2a0--7553
1-0.00.01 | DG.- Grundriss | Werksteinbelag | Treppenhaus1 | 0510Rau0000007562 | VF | schw.Estrich | 5b11ceff-7c37-4271-a11e-d8302deba2a0--7562 | Allplan Attributes - Text3: Dämmung
1-0.00.05 | DG.- Grundriss | Anstrich | Abstr. | 0510Rau0000007591 | NF | Betonboden glatt | 5b11ceff-7c37-4271-a11e-d8302deba2a0--7591
1-0.00.15 | DG.- Grundriss | Anstrich | Schlafen | 0510Rau0000009638 | NF | Betonboden glatt | 5b11ceff-7c37-4271-a11e-d8302deba2a0--9638
1-0.00.05 | DG.- Grundriss | Anstrich | Abstr. | 0510Rau0000009683 | NF | Betonboden glatt | 5b11ceff-7c37-4271-a11e-d8302deba2a0--9683
1-0.00.05 | DG.- Grundriss | Anstrich | Abstr. | 0510Rau0000009745 | NF | Betonboden glatt | 5b11ceff-7c37-4271-a11e-d8302deba2a0--9745
1-0.00.05 | DG.- Grundriss | Anstrich | Abstr. | 0510Rau0000009776 | NF | Betonboden glatt | 5b11ceff-7c37-4271-a11e-d8302deba2a0--9776
1-0.00.05 | DG.- Grundriss | Anstrich | Abstr. | 0510Rau0000009807 | NF | Betonboden glatt | 5b11ceff-7c37-4271-a11e-d8302deba2a0--9807
1-0.00.05 | DG.- Grundriss | Anstrich | Abstr. | 0510Rau0000009838 | NF | Betonboden glatt | 5b11ceff-7c37-4271-a11e-d8302deba2a0--9838
1-0.00.05 | DG.- Grundriss | Anstrich | Abstr. | 0510Rau0000009869 | NF | Betonboden glatt | 5b11ceff-7c37-4271-a11e-d8302deba2a0--9869

# IfcBuildingElementProxy (11)
Material: <Unnamed Material>
Name | In
7 x 3D Element | Allgemein
4 x 3D Element | KG.- Grundriss

# IfcColumn (41)
In: KG.- Grundriss
Allplan Attributes - Umbaukategorie: Neubau; Einheit: m
Name | Material | Allright_Bauteil_ID | NOI_UUID
<Unnamed Element> | Stb-Stütze | 0100St 0780221014 | bb7460a6-57d8-45f2-954a-172a4282fe15--780221014 | Pset_ColumnCommon - LoadBearing: no; Allplan Attributes - Gewerk: Betonarbeiten
<Unnamed Element> | Stb-Stütze | 0100St 0780220911 | bb7460a6-57d8-45f2-954a-172a4282fe15--780220911 | Pset_ColumnCommon - LoadBearing: no; Allplan Attributes - Gewerk: Betonarbeiten
<Unnamed Element> | Stb-Stütze | 0100St 0780221021 | bb7460a6-57d8-45f2-954a-172a4282fe15--780221021 | Pset_ColumnCommon - LoadBearing: no; Allplan Attributes - Gewerk: Betonarbeiten
<Unnamed Element> | Stb-Stütze | 0100St 0780221020 | bb7460a6-57d8-45f2-954a-172a4282fe15--780221020 | Pset_ColumnCommon - LoadBearing: no; Allplan Attributes - Gewerk: Betonarbeiten
<Unnamed Element> | Stb-Stütze | 0100St 0780221019 | bb7460a6-57d8-45f2-954a-172a4282fe15--780221019 | Pset_ColumnCommon - LoadBearing: no; Allplan Attributes - Gewerk: Betonarbeiten
<Unnamed Element> | Stb-Stütze | 0100St 0780221018 | bb7460a6-57d8-45f2-954a-172a4282fe15--780221018 | Pset_ColumnCommon - LoadBearing: no; Allplan Attributes - Gewerk: Betonarbeiten
<Unnamed Element> | Stb-Stütze | 0100St 0780221017 | bb7460a6-57d8-45f2-954a-172a4282fe15--780221017 | Pset_ColumnCommon - LoadBearing: no; Allplan Attributes - Gewerk: Betonarbeiten
<Unnamed Element> | Stb-Stütze | 0100St 0780221016 | bb7460a6-57d8-45f2-954a-172a4282fe15--780221016 | Pset_ColumnCommon - LoadBearing: no; Allplan Attributes - Gewerk: Betonarbeiten
<Unnamed Element> | Stb-Stütze | 0100St 0780221015 | bb7460a6-57d8-45f2-954a-172a4282fe15--780221015 | Pset_ColumnCommon - LoadBearing: no; Allplan Attributes - Gewerk: Betonarbeiten
<Unnamed Element> | Stb-Stütze | 0100St 0780221013 | bb7460a6-57d8-45f2-954a-172a4282fe15--780221013 | Pset_ColumnCommon - LoadBearing: no; Allplan Attributes - Gewerk: Betonarbeiten
<Unnamed Element> | Stb-Stütze | 0100St 0780220474 | bb7460a6-57d8-45f2-954a-172a4282fe15--780220474 | Pset_ColumnCommon - LoadBearing: no; Allplan Attributes - Gewerk: Betonarbeiten
<Unnamed Element> | Stb-Stütze | 0117St 0781540728 | 09ef5a79-666f-4d65-ae11-371ec0050284--781540728
<Unnamed Element> | Stb-Stütze | 0117St 0781540726 | 09ef5a79-666f-4d65-ae11-371ec0050284--781540726
<Unnamed Element> | Stb-Wand | 0117St 0781540716 | 09ef5a79-666f-4d65-ae11-371ec0050284--781540716
<Unnamed Element> | Stb-Stütze | 0117St 0781540714 | 09ef5a79-666f-4d65-ae11-371ec0050284--781540714
<Unnamed Element> | Stb-Stütze | 0117St 0781540712 | 09ef5a79-666f-4d65-ae11-371ec0050284--781540712
<Unnamed Element> | Stb-Stütze | 0117St 0781540710 | 09ef5a79-666f-4d65-ae11-371ec0050284--781540710
<Unnamed Element> | Stb-Stütze | 0117St 0781540708 | 09ef5a79-666f-4d65-ae11-371ec0050284--781540708
<Unnamed Element> | Stb-Stütze | 0117St 0781540706 | 09ef5a79-666f-4d65-ae11-371ec0050284--781540706
<Unnamed Element> | Stb-Wand | 0117St 0781540704 | 09ef5a79-666f-4d65-ae11-371ec0050284--781540704
<Unnamed Element> | Stb-Stütze | 0117St 0781540702 | 09ef5a79-666f-4d65-ae11-371ec0050284--781540702
<Unnamed Element> | Stb-Stütze | 0117St 0781540700 | 09ef5a79-666f-4d65-ae11-371ec0050284--781540700
<Unnamed Element> | Stb-Stütze | 0117St 0781540698 | 09ef5a79-666f-4d65-ae11-371ec0050284--781540698
<Unnamed Element> | Stb-Stütze | 0117St 0781540696 | 09ef5a79-666f-4d65-ae11-371ec0050284--781540696
<Unnamed Element> | Stb-Stütze | 0117St 0781540694 | 09ef5a79-666f-4d65-ae11-371ec0050284--781540694
<Unnamed Element> | Stb-Stütze | 0117St 0781540692 | 09ef5a79-666f-4d65-ae11-371ec0050284--781540692
<Unnamed Element> | Stb-Stütze | 0117St 0781540690 | 09ef5a79-666f-4d65-ae11-371ec0050284--781540690
<Unnamed Element> | Stb-Stütze | 0117St 0781540688 | 09ef5a79-666f-4d65-ae11-371ec0050284--781540688
<Unnamed Element> | Stb-Stütze | 0117St 0781540686 | 09ef5a79-666f-4d65-ae11-371ec0050284--781540686
<Unnamed Element> | Stb-Stütze | 0117St 0781540684 | 09ef5a79-666f-4d65-ae11-371ec0050284--781540684
<Unnamed Element> | Stb-Stütze | 0117St 0781540682 | 09ef5a79-666f-4d65-ae11-371ec0050284--781540682
<Unnamed Element> | Stb-Stütze | 0117St 0781540680 | 09ef5a79-666f-4d65-ae11-371ec0050284--781540680
<Unnamed Element> | Stb-Stütze | 0117St 0781540678 | 09ef5a79-666f-4d65-ae11-371ec0050284--781540678
<Unnamed Element> | Stb-Stütze | 0117St 0781540676 | 09ef5a79-666f-4d65-ae11-371ec0050284--781540676
<Unnamed Element> | Stb-Stütze | 0117St 0781540674 | 09ef5a79-666f-4d65-ae11-371ec0050284--781540674
<Unnamed Element> | Stb-Stütze | 0117St 0781540672 | 09ef5a79-666f-4d65-ae11-371ec0050284--781540672
<Unnamed Element> | Stb-Stütze | 0117St 0781540660 | 09ef5a79-666f-4d65-ae11-371ec0050284--781540660
<Unnamed Element> | Stb-Stütze | 0117St 0781540658 | 09ef5a79-666f-4d65-ae11-371ec0050284--781540658
<Unnamed Element> | Stb-Stütze | 0117St 0781540652 | 09ef5a79-666f-4d65-ae11-371ec0050284--781540652
<Unnamed Element> | Stb-Stütze | 0117St 0781540650 | 09ef5a79-666f-4d65-ae11-371ec0050284--781540650
<Unnamed Element> | Stb-Wand | 0117St 0781540648 | 09ef5a79-666f-4d65-ae11-371ec0050284--781540648

# IfcDoor: Tür (4)
In: EG.- Grundriss
Type - OperationType: USERDEFINED; ParameterTakesPrecedence: no; Sizeable: no
OverallHeight: 2430 mm
Allplan Attributes - Einheit: St; V6: 0; V7: 0; V8: 0; V9: 0; Programmversion: 2.2; Bezeichnung: Tür; Plugin_Bezeichnung: MainObject; Plugin_Objektname: SmartPartCompressed; Version: 4.1; Einbauhöhe_Fensterbank_Außen: 0; Einbauhöhe_Fensterbank_Innen: 0; Abstand_Öffn_Unten: 0; Abstand_Öffn_Oben: 0; Abstand_Öffn_Links: 0; Abstand_Öffn_Rechts: 0; Abzug_Öffn_Unten: 70; Abzug_Öffn_Links: 70; Abzug_Öffn_Rechts: 70; Abzug_Öffn_Oben: 70
Name | OverallWidth (mm) | Allright_Bauteil_ID | NOI_UUID | Glasfläche
Tür | 1510 | 0200Mak0784438912 | 9eee6ca3-aa3f-4e17-bd40-2a040d5346dc--784438912 | 2.125
Tür | 1510 | 0200Mak0784438617 | 9eee6ca3-aa3f-4e17-bd40-2a040d5346dc--784438617 | 2.125
Tür | 1510 | 0200Mak0784440761 | 9eee6ca3-aa3f-4e17-bd40-2a040d5346dc--784440761 | 2.125
Tür | 1135 | 0200Mak0784440144 | 9eee6ca3-aa3f-4e17-bd40-2a040d5346dc--784440144 | 1.51845

# IfcDoor: m
In: DG.- Grundriss
Type - OperationType: SINGLE_SWING_LEFT; ParameterTakesPrecedence: no; Sizeable: no
OverallHeight: 2135 mm; OverallWidth: 900 mm
Allplan Attributes - Allright_Bauteil_ID: 0500Mak0784449447; UK: 0; OK: -999; Einheit: St; V6: 4; V7: 4; V8: 0; V9: 0; NOI_UUID: 1bfc5a75-329c-4bd5-adfb-044822b851e1--784449447

# IfcFooting (5)
In: KG.- Grundriss
PredefinedType: STRIP_FOOTING; Material: <Unnamed Material>
Allplan Attributes - Umbaukategorie: Neubau; Einheit: m³
Name | Allright_Bauteil_ID | NOI_UUID
<Unnamed Element> | 0117SFu0781530093 | 09ef5a79-666f-4d65-ae11-371ec0050284--781530093
<Unnamed Element> | 0117SFu0781530090 | 09ef5a79-666f-4d65-ae11-371ec0050284--781530090
<Unnamed Element> | 0117SFu0781530087 | 09ef5a79-666f-4d65-ae11-371ec0050284--781530087
<Unnamed Element> | 0117SFu0781530084 | 09ef5a79-666f-4d65-ae11-371ec0050284--781530084
<Unnamed Element> | 0117SFu0781530080 | 09ef5a79-666f-4d65-ae11-371ec0050284--781530080

# IfcOpeningElement: Opening (200)
Name | In | Object Layer Attributes #1, Allright_Bauteil_ID | Object Layer Attributes #1, Umbaukategorie | Object Layer Attributes #1, Einheit | Object Layer Attributes #1, Gewerk | Object Layer Attributes #1, NOI_UUID
Fensteröffnung | KG.- Grundriss | 0100Fen0780220470 | Neubau | m³ | Betonarbeiten | bb7460a6-57d8-45f2-954a-172a4282fe15--780220470
Türöffnung | KG.- Grundriss | 0100Tür0783113361 | Neubau | m² | Wärme- und Kältedämmarbeiten | bb7460a6-57d8-45f2-954a-172a4282fe15--783113361 | Allplan Attributes - Object Layer Attributes #2, Allright_Bauteil_ID: 0100Tür0783113362; Object Layer Attributes #2, Umbaukategorie: Neubau; Object Layer Attributes #2, Einheit: m³; Object Layer Attributes #2, Gewerk: Betonarbeiten; Object Layer Attributes #2, NOI_UUID: bb7460a6-57d8-45f2-954a-172a4282fe15--783113362
Türöffnung | KG.- Grundriss | 0100Tür0783113172 | Neubau | m² | Wärme- und Kältedämmarbeiten | bb7460a6-57d8-45f2-954a-172a4282fe15--783113172 | Allplan Attributes - Object Layer Attributes #2, Allright_Bauteil_ID: 0100Tür0783113171; Object Layer Attributes #2, Umbaukategorie: Neubau; Object Layer Attributes #2, Einheit: m³; Object Layer Attributes #2, Gewerk: Betonarbeiten; Object Layer Attributes #2, NOI_UUID: bb7460a6-57d8-45f2-954a-172a4282fe15--783113171
Türöffnung | KG.- Grundriss | 0100Tür0783113343 | Neubau | m³ | Betonarbeiten | bb7460a6-57d8-45f2-954a-172a4282fe15--783113343
Türöffnung | KG.- Grundriss | 0100Tür0783112759 |  | m³ | Betonarbeiten | bb7460a6-57d8-45f2-954a-172a4282fe15--783112759
Türöffnung | KG.- Grundriss | 0100Tür0783113336 | Neubau | m³ | Betonarbeiten | bb7460a6-57d8-45f2-954a-172a4282fe15--783113336
Türöffnung | KG.- Grundriss | 0100Tür0783113183 | Neubau | m³ | Betonarbeiten | bb7460a6-57d8-45f2-954a-172a4282fe15--783113183
Türöffnung | KG.- Grundriss | 0100Tür0783113190 | Neubau | m³ | Betonarbeiten | bb7460a6-57d8-45f2-954a-172a4282fe15--783113190
Türöffnung | KG.- Grundriss | 0100Tür0783113309 | Neubau | m³ | Mauerarbeiten | bb7460a6-57d8-45f2-954a-172a4282fe15--783113309
Fensteröffnung | KG.- Grundriss | 0117Fen0781540389 | Neubau | m³ |  | 09ef5a79-666f-4d65-ae11-371ec0050284--781540389
Fensteröffnung | KG.- Grundriss | 0117Fen0781540385 | Neubau | m³ |  | 09ef5a79-666f-4d65-ae11-371ec0050284--781540385
Fensteröffnung | KG.- Grundriss | 0117Fen0781540387 | Neubau | m³ |  | 09ef5a79-666f-4d65-ae11-371ec0050284--781540387
Fensteröffnung | KG.- Grundriss | 0117Fen0781540768 | Neubau | m³ |  | 09ef5a79-666f-4d65-ae11-371ec0050284--781540768
Fensteröffnung | KG.- Grundriss | 0117Fen0781540775 | Neubau | m³ |  | 09ef5a79-666f-4d65-ae11-371ec0050284--781540775
Deckendurchbruch | KG.- Grundriss | 0117Ddu0781530204 | Neubau | m² |  | 09ef5a79-666f-4d65-ae11-371ec0050284--781530204
Deckendurchbruch | KG.- Grundriss | 0117Ddu0781530206 | Neubau | m² |  | 09ef5a79-666f-4d65-ae11-371ec0050284--781530206
Deckenöffnung | KG.- Grundriss | 0117Ddu0781530208 |  | m² |  | 09ef5a79-666f-4d65-ae11-371ec0050284--781530208
Deckenöffnung | KG.- Grundriss | 0117Ddu0781530210 |  | m² |  | 09ef5a79-666f-4d65-ae11-371ec0050284--781530210
Deckenöffnung | KG.- Grundriss | 0117Ddu0781530212 |  | m² |  | 09ef5a79-666f-4d65-ae11-371ec0050284--781530212
Deckenöffnung | KG.- Grundriss | 0117Ddu0781530214 |  | m² |  | 09ef5a79-666f-4d65-ae11-371ec0050284--781530214
Deckendurchbruch | KG.- Grundriss | 0117Ddu0781530216 | Neubau | m² |  | 09ef5a79-666f-4d65-ae11-371ec0050284--781530216
Deckendurchbruch | KG.- Grundriss | 0117Ddu0781530218 | Neubau | m² |  | 09ef5a79-666f-4d65-ae11-371ec0050284--781530218
Fensteröffnung | EG.- Grundriss | 0200Fen0784438021 | Neubau | m³ | Wärmedämm-Verbundsysteme | 9eee6ca3-aa3f-4e17-bd40-2a040d5346dc--784438021
Fensteröffnung | EG.- Grundriss | 0200Fen0784437888 | Neubau | m³ | Wärmedämm-Verbundsysteme | 9eee6ca3-aa3f-4e17-bd40-2a040d5346dc--784437888
Fensteröffnung | EG.- Grundriss | 0200Fen0784437464 | Neubau | m³ | Wärmedämm-Verbundsysteme | 9eee6ca3-aa3f-4e17-bd40-2a040d5346dc--784437464
Fensteröffnung | EG.- Grundriss | 0200Fen0784438087 | Neubau | m³ | Wärmedämm-Verbundsysteme | 9eee6ca3-aa3f-4e17-bd40-2a040d5346dc--784438087
Fensteröffnung | EG.- Grundriss | 0200Fen0784438088 | Neubau | m³ | Wärmedämm-Verbundsysteme | 9eee6ca3-aa3f-4e17-bd40-2a040d5346dc--784438088
Fensteröffnung | EG.- Grundriss | 0200Fen0784438080 | Neubau | m³ | Wärmedämm-Verbundsysteme | 9eee6ca3-aa3f-4e17-bd40-2a040d5346dc--784438080
Türöffnung | EG.- Grundriss | 0200Tür0784438909 | Neubau | m³ | Mauerarbeiten | 9eee6ca3-aa3f-4e17-bd40-2a040d5346dc--784438909
Türöffnung | EG.- Grundriss | 0200Tür0784438558 | Neubau | m³ | Mauerarbeiten | 9eee6ca3-aa3f-4e17-bd40-2a040d5346dc--784438558
Fensteröffnung | EG.- Grundriss | 0200Fen0784438527 | Neubau | m³ | Wärmedämm-Verbundsysteme | 9eee6ca3-aa3f-4e17-bd40-2a040d5346dc--784438527
Fensteröffnung | EG.- Grundriss | 0200Fen0784438513 | Neubau | m³ | Wärmedämm-Verbundsysteme | 9eee6ca3-aa3f-4e17-bd40-2a040d5346dc--784438513
Fensteröffnung | EG.- Grundriss | 0200Fen0784440914 | Neubau | m³ | Wärmedämm-Verbundsysteme | 9eee6ca3-aa3f-4e17-bd40-2a040d5346dc--784440914
Fensteröffnung | EG.- Grundriss | 0200Fen0784440920 | Neubau | m³ | Wärmedämm-Verbundsysteme | 9eee6ca3-aa3f-4e17-bd40-2a040d5346dc--784440920
Fensteröffnung | EG.- Grundriss | 0200Fen0784440898 | Neubau | m³ | Wärmedämm-Verbundsysteme | 9eee6ca3-aa3f-4e17-bd40-2a040d5346dc--784440898
Fensteröffnung | EG.- Grundriss | 0200Fen0784440884 | Neubau | m³ | Wärmedämm-Verbundsysteme | 9eee6ca3-aa3f-4e17-bd40-2a040d5346dc--784440884
Fensteröffnung | EG.- Grundriss | 0200Fen0784439595 | Neubau | m³ | Wärmedämm-Verbundsysteme | 9eee6ca3-aa3f-4e17-bd40-2a040d5346dc--784439595
Fensteröffnung | EG.- Grundriss | 0200Fen0784439581 | Neubau | m³ | Wärmedämm-Verbundsysteme | 9eee6ca3-aa3f-4e17-bd40-2a040d5346dc--784439581
Fensteröffnung | EG.- Grundriss | 0200Fen0784439567 | Neubau | m³ | Wärmedämm-Verbundsysteme | 9eee6ca3-aa3f-4e17-bd40-2a040d5346dc--784439567
Fensteröffnung | EG.- Grundriss | 0200Fen0784439553 | Neubau | m³ | Wärmedämm-Verbundsysteme | 9eee6ca3-aa3f-4e17-bd40-2a040d5346dc--784439553
Fensteröffnung | EG.- Grundriss | 0200Fen0784439539 | Neubau | m³ | Wärmedämm-Verbundsysteme | 9eee6ca3-aa3f-4e17-bd40-2a040d5346dc--784439539
Fensteröffnung | EG.- Grundriss | 0200Fen0784439525 | Neubau | m³ | Wärmedämm-Verbundsysteme | 9eee6ca3-aa3f-4e17-bd40-2a040d5346dc--784439525
Fensteröffnung | EG.- Grundriss | 0200Fen0784439373 | Neubau | m³ | Wärmedämm-Verbundsysteme | 9eee6ca3-aa3f-4e17-bd40-2a040d5346dc--784439373
Fensteröffnung | EG.- Grundriss | 0200Fen0784439193 | Neubau | m³ | Wärmedämm-Verbundsysteme | 9eee6ca3-aa3f-4e17-bd40-2a040d5346dc--784439193
Fensteröffnung | EG.- Grundriss | 0200Fen0784439180 | Neubau | m³ | Wärmedämm-Verbundsysteme | 9eee6ca3-aa3f-4e17-bd40-2a040d5346dc--784439180
Fensteröffnung | EG.- Grundriss | 0200Fen0784439166 | Neubau | m³ | Wärmedämm-Verbundsysteme | 9eee6ca3-aa3f-4e17-bd40-2a040d5346dc--784439166
Fensteröffnung | EG.- Grundriss | 0200Fen0784439652 | Neubau | m³ | Wärmedämm-Verbundsysteme | 9eee6ca3-aa3f-4e17-bd40-2a040d5346dc--784439652
Fensteröffnung | EG.- Grundriss | 0200Fen0784439638 | Neubau | m³ | Wärmedämm-Verbundsysteme | 9eee6ca3-aa3f-4e17-bd40-2a040d5346dc--784439638
Fensteröffnung | EG.- Grundriss | 0200Fen0784439666 | Neubau | m³ | Mauerarbeiten | 9eee6ca3-aa3f-4e17-bd40-2a040d5346dc--784439666
Fensteröffnung | EG.- Grundriss | 0200Fen0784440054 | Neubau | m³ | Wärmedämm-Verbundsysteme | 9eee6ca3-aa3f-4e17-bd40-2a040d5346dc--784440054
Fensteröffnung | EG.- Grundriss | 0200Fen0784440776 | Neubau | m³ | Wärmedämm-Verbundsysteme | 9eee6ca3-aa3f-4e17-bd40-2a040d5346dc--784440776
Fensteröffnung | EG.- Grundriss | 0200Fen0784440869 | Neubau | m³ | Wärmedämm-Verbundsysteme | 9eee6ca3-aa3f-4e17-bd40-2a040d5346dc--784440869
Fensteröffnung | EG.- Grundriss | 0200Fen0784440790 | Neubau | m³ | Wärmedämm-Verbundsysteme | 9eee6ca3-aa3f-4e17-bd40-2a040d5346dc--784440790
Fensteröffnung | EG.- Grundriss | 0200Fen0784439029 | Neubau | m³ | Mauerarbeiten | 9eee6ca3-aa3f-4e17-bd40-2a040d5346dc--784439029
Fensteröffnung | EG.- Grundriss | 0200Fen0784434088 | Neubau | m³ | Mauerarbeiten | 9eee6ca3-aa3f-4e17-bd40-2a040d5346dc--784434088
Fensteröffnung | EG.- Grundriss | 0200Fen0784440762 | Neubau | m³ | Wärmedämm-Verbundsysteme | 9eee6ca3-aa3f-4e17-bd40-2a040d5346dc--784440762
Türöffnung | EG.- Grundriss | 0200Tür0784440747 | Neubau | m³ | Mauerarbeiten | 9eee6ca3-aa3f-4e17-bd40-2a040d5346dc--784440747
Türöffnung | EG.- Grundriss | 0200Tür0784441235 | Neubau | m³ | Mauerarbeiten | 9eee6ca3-aa3f-4e17-bd40-2a040d5346dc--784441235
Türöffnung | EG.- Grundriss | 0200Tür0784441242 | Neubau | m³ | Mauerarbeiten | 9eee6ca3-aa3f-4e17-bd40-2a040d5346dc--784441242
Türöffnung | EG.- Grundriss | 0200Tür0784435554 |  | m³ | Betonarbeiten | 9eee6ca3-aa3f-4e17-bd40-2a040d5346dc--784435554
Fensteröffnung | EG.- Grundriss | 0200Fen0784439676 | Neubau | m³ | Mauerarbeiten | 9eee6ca3-aa3f-4e17-bd40-2a040d5346dc--784439676
Türöffnung | EG.- Grundriss | 0200Tür0784440133 | Neubau | m³ | Mauerarbeiten | 9eee6ca3-aa3f-4e17-bd40-2a040d5346dc--784440133
Fensteröffnung | EG.- Grundriss | 0200Fen0784440733 | Neubau | m³ | Wärmedämm-Verbundsysteme | 9eee6ca3-aa3f-4e17-bd40-2a040d5346dc--784440733
Fensteröffnung | EG.- Grundriss | 0200Fen0784440719 | Neubau | m³ | Wärmedämm-Verbundsysteme | 9eee6ca3-aa3f-4e17-bd40-2a040d5346dc--784440719
Fensteröffnung | EG.- Grundriss | 0200Fen0784440200 | Neubau | m³ | Wärmedämm-Verbundsysteme | 9eee6ca3-aa3f-4e17-bd40-2a040d5346dc--784440200
Fensteröffnung | EG.- Grundriss | 0200Fen0784440186 | Neubau | m³ | Wärmedämm-Verbundsysteme | 9eee6ca3-aa3f-4e17-bd40-2a040d5346dc--784440186
Türöffnung | EG.- Grundriss | 0200Tür0784441063 | Neubau | m³ | Mauerarbeiten | 9eee6ca3-aa3f-4e17-bd40-2a040d5346dc--784441063
Türöffnung | EG.- Grundriss | 0200Tür0784441184 | Neubau | m³ | Mauerarbeiten | 9eee6ca3-aa3f-4e17-bd40-2a040d5346dc--784441184
Türöffnung | EG.- Grundriss | 0200Tür0784441191 | Neubau | m³ | Mauerarbeiten | 9eee6ca3-aa3f-4e17-bd40-2a040d5346dc--784441191
Türöffnung | EG.- Grundriss | 0200Tür0784441205 | Neubau | m³ | Mauerarbeiten | 9eee6ca3-aa3f-4e17-bd40-2a040d5346dc--784441205
Türöffnung | EG.- Grundriss | 0200Tür0784441198 | Neubau | m³ | Mauerarbeiten | 9eee6ca3-aa3f-4e17-bd40-2a040d5346dc--784441198
Türöffnung | EG.- Grundriss | 0200Tür0784441104 | Neubau | m³ | Mauerarbeiten | 9eee6ca3-aa3f-4e17-bd40-2a040d5346dc--784441104
Türöffnung | EG.- Grundriss | 0200Tür0784441097 | Neubau | m³ | Mauerarbeiten | 9eee6ca3-aa3f-4e17-bd40-2a040d5346dc--784441097
Türöffnung | EG.- Grundriss | 0200Tür0784441077 | Neubau | m³ | Mauerarbeiten | 9eee6ca3-aa3f-4e17-bd40-2a040d5346dc--784441077
Türöffnung | EG.- Grundriss | 0200Tür0784441070 | Neubau | m³ | Mauerarbeiten | 9eee6ca3-aa3f-4e17-bd40-2a040d5346dc--784441070
Türöffnung | EG.- Grundriss | 0200Tür0784441090 | Neubau | m³ | Mauerarbeiten | 9eee6ca3-aa3f-4e17-bd40-2a040d5346dc--784441090
Türöffnung | EG.- Grundriss | 0200Tür0784441515 | Neubau | m³ | Mauerarbeiten | 9eee6ca3-aa3f-4e17-bd40-2a040d5346dc--784441515
Türöffnung | EG.- Grundriss | 0200Tür0784441508 | Neubau | m³ | Mauerarbeiten | 9eee6ca3-aa3f-4e17-bd40-2a040d5346dc--784441508
Türöffnung | EG.- Grundriss | 0200Tür0784441529 | Neubau | m³ | Mauerarbeiten | 9eee6ca3-aa3f-4e17-bd40-2a040d5346dc--784441529
Türöffnung | EG.- Grundriss | 0200Tür0784441522 | Neubau | m³ | Mauerarbeiten | 9eee6ca3-aa3f-4e17-bd40-2a040d5346dc--784441522
Türöffnung | EG.- Grundriss | 0200Tür0784441212 | Neubau | m³ | Mauerarbeiten | 9eee6ca3-aa3f-4e17-bd40-2a040d5346dc--784441212
Türöffnung | EG.- Grundriss | 0200Tür0784441163 | Neubau | m³ | Mauerarbeiten | 9eee6ca3-aa3f-4e17-bd40-2a040d5346dc--784441163
Türöffnung | EG.- Grundriss | 0200Tür0784441219 | Neubau | m³ | Mauerarbeiten | 9eee6ca3-aa3f-4e17-bd40-2a040d5346dc--784441219
Türöffnung | EG.- Grundriss | 0200Tür0784441177 | Neubau | m³ | Mauerarbeiten | 9eee6ca3-aa3f-4e17-bd40-2a040d5346dc--784441177
Türöffnung | EG.- Grundriss | 0200Tür0784441228 | Neubau | m³ | Mauerarbeiten | 9eee6ca3-aa3f-4e17-bd40-2a040d5346dc--784441228
Türöffnung | EG.- Grundriss | 0200Tür0784441170 | Neubau | m³ | Mauerarbeiten | 9eee6ca3-aa3f-4e17-bd40-2a040d5346dc--784441170
Türöffnung | EG.- Grundriss | 0200Tür0784441022 | Neubau | m³ | Mauerarbeiten | 9eee6ca3-aa3f-4e17-bd40-2a040d5346dc--784441022
Türöffnung | EG.- Grundriss | 0200Tür0784441554 | Neubau | m³ | Mauerarbeiten | 9eee6ca3-aa3f-4e17-bd40-2a040d5346dc--784441554
Türöffnung | EG.- Grundriss | 0200Tür0784441585 | Neubau | m³ | Mauerarbeiten | 9eee6ca3-aa3f-4e17-bd40-2a040d5346dc--784441585
Türöffnung | EG.- Grundriss | 0200Tür0784441629 | Neubau | m³ | Mauerarbeiten | 9eee6ca3-aa3f-4e17-bd40-2a040d5346dc--784441629
Fensteröffnung | OG.- Grundriss | 0300Fen0784445547 | Neubau | m³ | Wärmedämm-Verbundsysteme | 92c99fbc-4ab2-4783-a754-1daa3fa43448--784445547
Fensteröffnung | OG.- Grundriss | 0300Fen0000000181 | Neubau | m³ | Wärmedämm-Verbundsysteme | 92c99fbc-4ab2-4783-a754-1daa3fa43448--181
Fensteröffnung | OG.- Grundriss | 0300Fen0000000175 | Neubau | m³ | Wärmedämm-Verbundsysteme | 92c99fbc-4ab2-4783-a754-1daa3fa43448--175
Fensteröffnung | OG.- Grundriss | 0300Fen0784445530 | Neubau | m³ | Wärmedämm-Verbundsysteme | 92c99fbc-4ab2-4783-a754-1daa3fa43448--784445530
Fensteröffnung | OG.- Grundriss | 0300Fen0000000169 | Neubau | m³ | Wärmedämm-Verbundsysteme | 92c99fbc-4ab2-4783-a754-1daa3fa43448--169
Fensteröffnung | OG.- Grundriss | 0300Fen0000000163 | Neubau | m³ | Wärmedämm-Verbundsysteme | 92c99fbc-4ab2-4783-a754-1daa3fa43448--163
Fensteröffnung | OG.- Grundriss | 0300Fen0784445404 | Neubau | m³ | Wärmedämm-Verbundsysteme | 92c99fbc-4ab2-4783-a754-1daa3fa43448--784445404
Fensteröffnung | OG.- Grundriss | 0300Fen0784445390 | Neubau | m³ | Wärmedämm-Verbundsysteme | 92c99fbc-4ab2-4783-a754-1daa3fa43448--784445390
Fensteröffnung | OG.- Grundriss | 0300Fen0000000485 | Neubau | m³ | Wärmedämm-Verbundsysteme | 92c99fbc-4ab2-4783-a754-1daa3fa43448--485
Fensteröffnung | OG.- Grundriss | 0300Fen0000000484 | Neubau | m³ | Wärmedämm-Verbundsysteme | 92c99fbc-4ab2-4783-a754-1daa3fa43448--484
Fensteröffnung | OG.- Grundriss | 0300Fen0000000340 | Neubau | m³ | Wärmedämm-Verbundsysteme | 92c99fbc-4ab2-4783-a754-1daa3fa43448--340
Fensteröffnung | OG.- Grundriss | 0300Fen0000000347 | Neubau | m³ | Wärmedämm-Verbundsysteme | 92c99fbc-4ab2-4783-a754-1daa3fa43448--347
Fensteröffnung | OG.- Grundriss | 0300Fen0784442894 | Neubau | m³ | Wärmedämm-Verbundsysteme | 92c99fbc-4ab2-4783-a754-1daa3fa43448--784442894
Fensteröffnung | OG.- Grundriss | 0300Fen0784442878 | Neubau | m³ | Wärmedämm-Verbundsysteme | 92c99fbc-4ab2-4783-a754-1daa3fa43448--784442878
Fensteröffnung | OG.- Grundriss | 0300Fen0784444739 | Neubau | m³ | Wärmedämm-Verbundsysteme | 92c99fbc-4ab2-4783-a754-1daa3fa43448--784444739
Fensteröffnung | OG.- Grundriss | 0300Fen0784444722 | Neubau | m³ | Wärmedämm-Verbundsysteme | 92c99fbc-4ab2-4783-a754-1daa3fa43448--784444722
Fensteröffnung | OG.- Grundriss | 0300Fen0000000321 | Neubau | m³ | Wärmedämm-Verbundsysteme | 92c99fbc-4ab2-4783-a754-1daa3fa43448--321
Fensteröffnung | OG.- Grundriss | 0300Fen0784445444 | Neubau | m³ | Wärmedämm-Verbundsysteme | 92c99fbc-4ab2-4783-a754-1daa3fa43448--784445444
Fensteröffnung | OG.- Grundriss | 0300Fen0784445474 | Neubau | m³ | Wärmedämm-Verbundsysteme | 92c99fbc-4ab2-4783-a754-1daa3fa43448--784445474
Fensteröffnung | OG.- Grundriss | 0300Fen0784445428 | Neubau | m³ | Wärmedämm-Verbundsysteme | 92c99fbc-4ab2-4783-a754-1daa3fa43448--784445428
Fensteröffnung | OG.- Grundriss | 0300Fen0784445460 | Neubau | m³ | Wärmedämm-Verbundsysteme | 92c99fbc-4ab2-4783-a754-1daa3fa43448--784445460
Fensteröffnung | OG.- Grundriss | 0300Fen0784442205 | Neubau | m³ | Mauerarbeiten | 92c99fbc-4ab2-4783-a754-1daa3fa43448--784442205
Fensteröffnung | OG.- Grundriss | 0300Fen0000000307 | Neubau | m³ | Wärmedämm-Verbundsysteme | 92c99fbc-4ab2-4783-a754-1daa3fa43448--307
Fensteröffnung | OG.- Grundriss | 0300Fen0784442083 | Neubau | m³ | Mauerarbeiten | 92c99fbc-4ab2-4783-a754-1daa3fa43448--784442083
Fensteröffnung | OG.- Grundriss | 0300Fen0784444797 | Neubau | m³ | Wärmedämm-Verbundsysteme | 92c99fbc-4ab2-4783-a754-1daa3fa43448--784444797
Türöffnung | OG.- Grundriss | 0300Tür0000000466 | Neubau | m³ | Mauerarbeiten | 92c99fbc-4ab2-4783-a754-1daa3fa43448--466
Türöffnung | OG.- Grundriss | 0300Tür0000000052 |  | m³ | Betonarbeiten | 92c99fbc-4ab2-4783-a754-1daa3fa43448--52
Fensteröffnung | OG.- Grundriss | 0300Fen0784444753 | Neubau | m³ | Wärmedämm-Verbundsysteme | 92c99fbc-4ab2-4783-a754-1daa3fa43448--784444753
Fensteröffnung | OG.- Grundriss | 0300Fen0784444783 | Neubau | m³ | Wärmedämm-Verbundsysteme | 92c99fbc-4ab2-4783-a754-1daa3fa43448--784444783
Fensteröffnung | OG.- Grundriss | 0300Fen0784444769 | Neubau | m³ | Wärmedämm-Verbundsysteme | 92c99fbc-4ab2-4783-a754-1daa3fa43448--784444769
Fensteröffnung | OG.- Grundriss | 0300Fen0000000296 | Neubau | m³ | Wärmedämm-Verbundsysteme | 92c99fbc-4ab2-4783-a754-1daa3fa43448--296
Fensteröffnung | OG.- Grundriss | 0300Fen0000000280 | Neubau | m³ | Wärmedämm-Verbundsysteme | 92c99fbc-4ab2-4783-a754-1daa3fa43448--280
Fensteröffnung | OG.- Grundriss | 0300Fen0000000274 | Neubau | m³ | Wärmedämm-Verbundsysteme | 92c99fbc-4ab2-4783-a754-1daa3fa43448--274
Türöffnung | OG.- Grundriss | 0300Tür0000000361 | Neubau | m³ | Mauerarbeiten | 92c99fbc-4ab2-4783-a754-1daa3fa43448--361
Türöffnung | OG.- Grundriss | 0300Tür0000000392 | Neubau | m³ | Mauerarbeiten | 92c99fbc-4ab2-4783-a754-1daa3fa43448--392
Türöffnung | OG.- Grundriss | 0300Tür0000000395 | Neubau | m³ | Mauerarbeiten | 92c99fbc-4ab2-4783-a754-1daa3fa43448--395
Türöffnung | OG.- Grundriss | 0300Tür0000000377 | Neubau | m³ | Mauerarbeiten | 92c99fbc-4ab2-4783-a754-1daa3fa43448--377
Türöffnung | OG.- Grundriss | 0300Tür0000000374 | Neubau | m³ | Mauerarbeiten | 92c99fbc-4ab2-4783-a754-1daa3fa43448--374
Türöffnung | OG.- Grundriss | 0300Tür0000000368 | Neubau | m³ | Mauerarbeiten | 92c99fbc-4ab2-4783-a754-1daa3fa43448--368
Türöffnung | OG.- Grundriss | 0300Tür0000000365 | Neubau | m³ | Mauerarbeiten | 92c99fbc-4ab2-4783-a754-1daa3fa43448--365
Türöffnung | OG.- Grundriss | 0300Tür0000000371 | Neubau | m³ | Mauerarbeiten | 92c99fbc-4ab2-4783-a754-1daa3fa43448--371
Türöffnung | OG.- Grundriss | 0300Tür0000000416 | Neubau | m³ | Mauerarbeiten | 92c99fbc-4ab2-4783-a754-1daa3fa43448--416
Türöffnung | OG.- Grundriss | 0300Tür0000000417 | Neubau | m³ | Mauerarbeiten | 92c99fbc-4ab2-4783-a754-1daa3fa43448--417
Türöffnung | OG.- Grundriss | 0300Tür0000000415 | Neubau | m³ | Mauerarbeiten | 92c99fbc-4ab2-4783-a754-1daa3fa43448--415
Türöffnung | OG.- Grundriss | 0300Tür0000000388 | Neubau | m³ | Mauerarbeiten | 92c99fbc-4ab2-4783-a754-1daa3fa43448--388
Türöffnung | OG.- Grundriss | 0300Tür0000000384 | Neubau | m³ | Mauerarbeiten | 92c99fbc-4ab2-4783-a754-1daa3fa43448--384
Türöffnung | OG.- Grundriss | 0300Tür0000000418 | Neubau | m³ | Mauerarbeiten | 92c99fbc-4ab2-4783-a754-1daa3fa43448--418
Türöffnung | OG.- Grundriss | 0300Tür0784445569 | Neubau | m³ | Mauerarbeiten | 92c99fbc-4ab2-4783-a754-1daa3fa43448--784445569
Türöffnung | OG.- Grundriss | 0300Tür0784445562 | Neubau | m³ | Mauerarbeiten | 92c99fbc-4ab2-4783-a754-1daa3fa43448--784445562
Türöffnung | OG.- Grundriss | 0300Tür0784445579 | Neubau | m³ | Mauerarbeiten | 92c99fbc-4ab2-4783-a754-1daa3fa43448--784445579
Türöffnung | OG.- Grundriss | 0300Tür0784445582 | Neubau | m³ | Mauerarbeiten | 92c99fbc-4ab2-4783-a754-1daa3fa43448--784445582
Türöffnung | OG.- Grundriss | 0300Tür0000000499 | Neubau | m³ | Mauerarbeiten | 92c99fbc-4ab2-4783-a754-1daa3fa43448--499
Türöffnung | OG.- Grundriss | 0300Tür0784442051 | Neubau | m³ | Mauerarbeiten | 92c99fbc-4ab2-4783-a754-1daa3fa43448--784442051
Türöffnung | OG.- Grundriss | 0300Tür0000000401 | Neubau | m³ | Mauerarbeiten | 92c99fbc-4ab2-4783-a754-1daa3fa43448--401
Türöffnung | OG.- Grundriss | 0300Tür0000000398 | Neubau | m³ | Mauerarbeiten | 92c99fbc-4ab2-4783-a754-1daa3fa43448--398
Türöffnung | OG.- Grundriss | 0300Tür0000000441 | Neubau | m³ | Mauerarbeiten | 92c99fbc-4ab2-4783-a754-1daa3fa43448--441
Fensteröffnung | OG.- Grundriss | 0300Fen0000000439 | Neubau | m³ | Wärmedämm-Verbundsysteme | 92c99fbc-4ab2-4783-a754-1daa3fa43448--439
Fensteröffnung | OG.- Grundriss | 0300Fen0000000438 | Neubau | m³ | Wärmedämm-Verbundsysteme | 92c99fbc-4ab2-4783-a754-1daa3fa43448--438
Fensteröffnung | OG.- Grundriss | 0300Fen0784442390 | Neubau | m³ | Wärmedämm-Verbundsysteme | 92c99fbc-4ab2-4783-a754-1daa3fa43448--784442390
Fensteröffnung | OG.- Grundriss | 0300Fen0784442376 | Neubau | m³ | Wärmedämm-Verbundsysteme | 92c99fbc-4ab2-4783-a754-1daa3fa43448--784442376
Fensteröffnung | OG.- Grundriss | 0300Fen0000000434 | Neubau | m³ | Wärmedämm-Verbundsysteme | 92c99fbc-4ab2-4783-a754-1daa3fa43448--434
Fensteröffnung | OG.- Grundriss | 0300Fen0000000433 | Neubau | m³ | Wärmedämm-Verbundsysteme | 92c99fbc-4ab2-4783-a754-1daa3fa43448--433
Fensteröffnung | OG.- Grundriss | 0300Fen0784442300 | Neubau | m³ | Wärmedämm-Verbundsysteme | 92c99fbc-4ab2-4783-a754-1daa3fa43448--784442300
Fensteröffnung | OG.- Grundriss | 0300Fen0000000432 | Neubau | m³ | Wärmedämm-Verbundsysteme | 92c99fbc-4ab2-4783-a754-1daa3fa43448--432
Fensteröffnung | OG.- Grundriss | 0300Fen0000000435 | Neubau | m³ | Wärmedämm-Verbundsysteme | 92c99fbc-4ab2-4783-a754-1daa3fa43448--435
Fensteröffnung | OG.- Grundriss | 0300Fen0000000437 | Neubau | m³ | Wärmedämm-Verbundsysteme | 92c99fbc-4ab2-4783-a754-1daa3fa43448--437
Fensteröffnung | OG.- Grundriss | 0300Fen0000000440 | Neubau | m³ | Wärmedämm-Verbundsysteme | 92c99fbc-4ab2-4783-a754-1daa3fa43448--440
Fensteröffnung | DG.- Grundriss | 0500Fen0000000512 | Neubau | m³ | Wärmedämm-Verbundsysteme | 1bfc5a75-329c-4bd5-adfb-044822b851e1--512
Fensteröffnung | DG.- Grundriss | 0500Fen0000000230 | Neubau | m³ | Wärmedämm-Verbundsysteme | 1bfc5a75-329c-4bd5-adfb-044822b851e1--230
Fensteröffnung | DG.- Grundriss | 0500Fen0000000229 | Neubau | m³ | Wärmedämm-Verbundsysteme | 1bfc5a75-329c-4bd5-adfb-044822b851e1--229
Fensteröffnung | DG.- Grundriss | 0500Fen0000000505 | Neubau | m³ | Wärmedämm-Verbundsysteme | 1bfc5a75-329c-4bd5-adfb-044822b851e1--505
Fensteröffnung | DG.- Grundriss | 0500Fen0000000228 | Neubau | m³ | Wärmedämm-Verbundsysteme | 1bfc5a75-329c-4bd5-adfb-044822b851e1--228
Fensteröffnung | DG.- Grundriss | 0500Fen0000000227 | Neubau | m³ | Wärmedämm-Verbundsysteme | 1bfc5a75-329c-4bd5-adfb-044822b851e1--227
Fensteröffnung | DG.- Grundriss | 0500Fen0000000473 | Neubau | m³ | Wärmedämm-Verbundsysteme | 1bfc5a75-329c-4bd5-adfb-044822b851e1--473
Fensteröffnung | DG.- Grundriss | 0500Fen0000000467 | Neubau | m³ | Wärmedämm-Verbundsysteme | 1bfc5a75-329c-4bd5-adfb-044822b851e1--467
Fensteröffnung | DG.- Grundriss | 0500Fen0000000256 | Neubau | m³ | Wärmedämm-Verbundsysteme | 1bfc5a75-329c-4bd5-adfb-044822b851e1--256
Fensteröffnung | DG.- Grundriss | 0500Fen0000000255 | Neubau | m³ | Wärmedämm-Verbundsysteme | 1bfc5a75-329c-4bd5-adfb-044822b851e1--255
Fensteröffnung | DG.- Grundriss | 0500Fen0000000234 | Neubau | m³ | Wärmedämm-Verbundsysteme | 1bfc5a75-329c-4bd5-adfb-044822b851e1--234
Fensteröffnung | DG.- Grundriss | 0500Fen0000000209 | Neubau | m³ | Wärmedämm-Verbundsysteme | 1bfc5a75-329c-4bd5-adfb-044822b851e1--209
Fensteröffnung | DG.- Grundriss | 0500Fen0000000216 | Neubau | m³ | Wärmedämm-Verbundsysteme | 1bfc5a75-329c-4bd5-adfb-044822b851e1--216
Fensteröffnung | DG.- Grundriss | 0500Fen0000000212 | Neubau | m³ | Wärmedämm-Verbundsysteme | 1bfc5a75-329c-4bd5-adfb-044822b851e1--212
Fensteröffnung | DG.- Grundriss | 0500Fen0000000215 | Neubau | m³ | Wärmedämm-Verbundsysteme | 1bfc5a75-329c-4bd5-adfb-044822b851e1--215
Fensteröffnung | DG.- Grundriss | 0500Fen0000000211 | Neubau | m³ | Wärmedämm-Verbundsysteme | 1bfc5a75-329c-4bd5-adfb-044822b851e1--211
Fensteröffnung | DG.- Grundriss | 0500Fen0784449206 | Neubau | m³ | Wärmedämm-Verbundsysteme | 1bfc5a75-329c-4bd5-adfb-044822b851e1--784449206
Fensteröffnung | DG.- Grundriss | 0500Fen0784449207 | Neubau | m³ | Wärmedämm-Verbundsysteme | 1bfc5a75-329c-4bd5-adfb-044822b851e1--784449207
Fensteröffnung | DG.- Grundriss | 0500Fen0784445367 | Neubau | m³ | Mauerarbeiten | 1bfc5a75-329c-4bd5-adfb-044822b851e1--784445367
Fensteröffnung | DG.- Grundriss | 0500Fen0784445357 | Neubau | m³ | Mauerarbeiten | 1bfc5a75-329c-4bd5-adfb-044822b851e1--784445357
Fensteröffnung | DG.- Grundriss | 0500Fen0000000446 | Neubau | m³ | Wärmedämm-Verbundsysteme | 1bfc5a75-329c-4bd5-adfb-044822b851e1--446
Fensteröffnung | DG.- Grundriss | 0500Fen0000000440 | Neubau | m³ | Wärmedämm-Verbundsysteme | 1bfc5a75-329c-4bd5-adfb-044822b851e1--440
Fensteröffnung | DG.- Grundriss | 0500Fen0000000233 | Neubau | m³ | Wärmedämm-Verbundsysteme | 1bfc5a75-329c-4bd5-adfb-044822b851e1--233
Fensteröffnung | DG.- Grundriss | 0500Fen0000000232 | Neubau | m³ | Wärmedämm-Verbundsysteme | 1bfc5a75-329c-4bd5-adfb-044822b851e1--232
Fensteröffnung | DG.- Grundriss | 0500Fen0000000231 | Neubau | m³ | Wärmedämm-Verbundsysteme | 1bfc5a75-329c-4bd5-adfb-044822b851e1--231
Türöffnung | DG.- Grundriss | 0500Tür0000000245 | Neubau | m³ | Mauerarbeiten | 1bfc5a75-329c-4bd5-adfb-044822b851e1--245
Türöffnung | DG.- Grundriss | 0500Tür0000000242 | Neubau | m³ | Mauerarbeiten | 1bfc5a75-329c-4bd5-adfb-044822b851e1--242
Türöffnung | DG.- Grundriss | 0500Tür0784449158 | Neubau | m³ | Mauerarbeiten | 1bfc5a75-329c-4bd5-adfb-044822b851e1--784449158
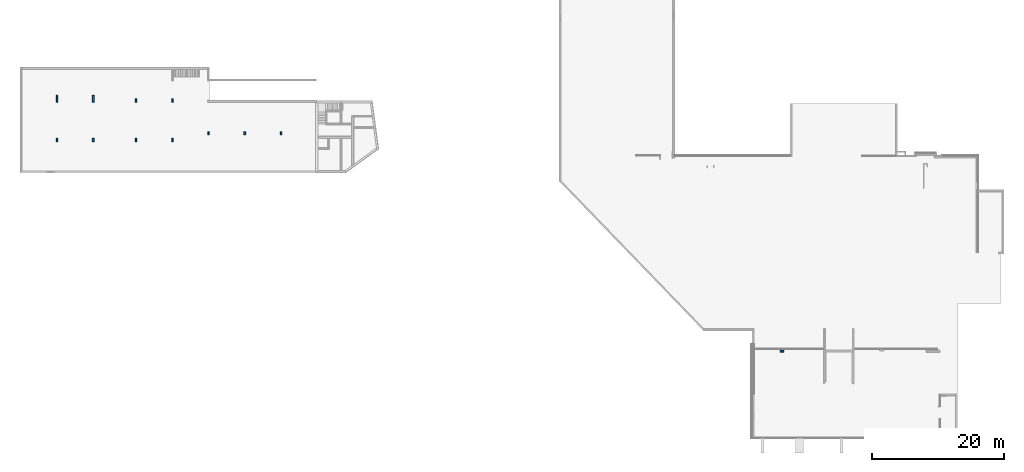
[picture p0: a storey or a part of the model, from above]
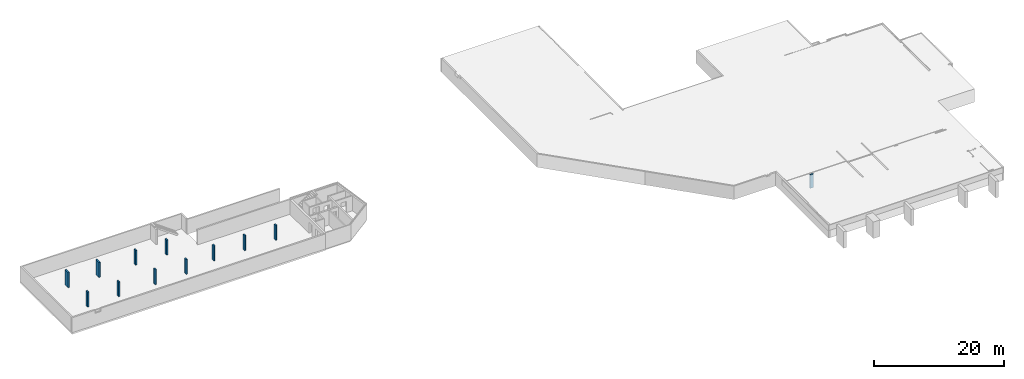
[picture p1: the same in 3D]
Properties of the parts of a building model (IFC2X3), part 2 of 4

# IfcOpeningElement: Opening (200)
Name | In | Object Layer Attributes #1, Allright_Bauteil_ID | Object Layer Attributes #1, Umbaukategorie | Object Layer Attributes #1, Einheit | Object Layer Attributes #1, Gewerk | Object Layer Attributes #1, NOI_UUID
Türöffnung | DG.- Grundriss | 0500Tür0000000522 | Neubau | m³ | Mauerarbeiten | 1bfc5a75-329c-4bd5-adfb-044822b851e1--522
Türöffnung | DG.- Grundriss | 0500Tür0000000519 | Neubau | m³ | Mauerarbeiten | 1bfc5a75-329c-4bd5-adfb-044822b851e1--519
Türöffnung | DG.- Grundriss | 0500Tür0000000530 | Neubau | m³ | Mauerarbeiten | 1bfc5a75-329c-4bd5-adfb-044822b851e1--530
Türöffnung | DG.- Grundriss | 0500Tür0000000529 | Neubau | m³ | Mauerarbeiten | 1bfc5a75-329c-4bd5-adfb-044822b851e1--529
Türöffnung | DG.- Grundriss | 0500Tür0000000225 | Neubau | m³ | Mauerarbeiten | 1bfc5a75-329c-4bd5-adfb-044822b851e1--225
Türöffnung | DG.- Grundriss | 0500Tür0000000224 | Neubau | m³ | Mauerarbeiten | 1bfc5a75-329c-4bd5-adfb-044822b851e1--224
Türöffnung | DG.- Grundriss | 0500Tür0000000218 | Neubau | m³ | Mauerarbeiten | 1bfc5a75-329c-4bd5-adfb-044822b851e1--218
Türöffnung | DG.- Grundriss | 0500Tür0000000243 | Neubau | m³ | Mauerarbeiten | 1bfc5a75-329c-4bd5-adfb-044822b851e1--243
Türöffnung | DG.- Grundriss | 0500Tür0784447322 | Neubau | m³ | Mauerarbeiten | 1bfc5a75-329c-4bd5-adfb-044822b851e1--784447322
Türöffnung | DG.- Grundriss | 0500Tür0000000239 | Neubau | m³ | Mauerarbeiten | 1bfc5a75-329c-4bd5-adfb-044822b851e1--239
Türöffnung | DG.- Grundriss | 0500Tür0000000240 | Neubau | m³ | Mauerarbeiten | 1bfc5a75-329c-4bd5-adfb-044822b851e1--240
Türöffnung | DG.- Grundriss | 0500Tür0000000236 | Neubau | m³ | Mauerarbeiten | 1bfc5a75-329c-4bd5-adfb-044822b851e1--236
Türöffnung | DG.- Grundriss | 0500Tür0000000238 | Neubau | m³ | Mauerarbeiten | 1bfc5a75-329c-4bd5-adfb-044822b851e1--238
Türöffnung | DG.- Grundriss | 0500Tür0784449470 | Neubau | m³ | Mauerarbeiten | 1bfc5a75-329c-4bd5-adfb-044822b851e1--784449470
Türöffnung | DG.- Grundriss | 0500Tür0784449451 |  | m² | Stahlbauarbeiten | 1bfc5a75-329c-4bd5-adfb-044822b851e1--784449451

# IfcOpeningElement: Recess (20)
In: KG.- Grundriss
Allplan Attributes - Object Layer Attributes #1, Einheit: m³
Name | Object Layer Attributes #1, Allright_Bauteil_ID | Object Layer Attributes #1, NOI_UUID
Wanddurchbruch | 0117Wdu0781540447 | 09ef5a79-666f-4d65-ae11-371ec0050284--781540447
Wanddurchbruch | 0117Wdu0781540449 | 09ef5a79-666f-4d65-ae11-371ec0050284--781540449
Wanddurchbruch | 0117Wdu0781540511 | 09ef5a79-666f-4d65-ae11-371ec0050284--781540511
Wanddurchbruch | 0117Wdu0781540509 | 09ef5a79-666f-4d65-ae11-371ec0050284--781540509
Wanddurchbruch | 0117Wdu0781540437 | 09ef5a79-666f-4d65-ae11-371ec0050284--781540437
Wanddurchbruch | 0117Wdu0781540439 | 09ef5a79-666f-4d65-ae11-371ec0050284--781540439
Wanddurchbruch | 0117Wdu0781540441 | 09ef5a79-666f-4d65-ae11-371ec0050284--781540441
Wanddurchbruch | 0117Wdu0781541338 | 09ef5a79-666f-4d65-ae11-371ec0050284--781541338
Wanddurchbruch | 0117Wdu0781541340 | 09ef5a79-666f-4d65-ae11-371ec0050284--781541340
Wanddurchbruch | 0117Wdu0781541342 | 09ef5a79-666f-4d65-ae11-371ec0050284--781541342
Wanddurchbruch | 0117Wdu0781541344 | 09ef5a79-666f-4d65-ae11-371ec0050284--781541344
Wanddurchbruch | 0117Wdu0781540777 | 09ef5a79-666f-4d65-ae11-371ec0050284--781540777
Wanddurchbruch | 0117Wdu0781540779 | 09ef5a79-666f-4d65-ae11-371ec0050284--781540779
Wanddurchbruch | 0117Wdu0781540781 | 09ef5a79-666f-4d65-ae11-371ec0050284--781540781
Wanddurchbruch | 0117Wdu0781540950 | 09ef5a79-666f-4d65-ae11-371ec0050284--781540950
Wanddurchbruch | 0117Wdu0781540952 | 09ef5a79-666f-4d65-ae11-371ec0050284--781540952
Wanddurchbruch | 0117Wdu0781540954 | 09ef5a79-666f-4d65-ae11-371ec0050284--781540954
Wanddurchbruch | 0117Wdu0781540956 | 09ef5a79-666f-4d65-ae11-371ec0050284--781540956
Wanddurchbruch | 0117Wdu0781540979 | 09ef5a79-666f-4d65-ae11-371ec0050284--781540979
Wanddurchbruch | 0117Wdu0781540987 | 09ef5a79-666f-4d65-ae11-371ec0050284--781540987

# IfcRailing (3)
In: KG.- Grundriss
Allplan Attributes - Einheit: St; V6: 0; V7: 0; V8: 0; V9: 0; Bauteil: Rail_Object; Bezeichnung: Rail_Path; Plugin_Bezeichnung: Rail_Path; Plugin_Objektname: Rail_Macro
Name | Allright_Bauteil_ID | NOI_UUID
Rail_Path | 0117Gel0781531017 | 09ef5a79-666f-4d65-ae11-371ec0050284--781531017
Rail_Path | 0117Gel0781531049 | 09ef5a79-666f-4d65-ae11-371ec0050284--781531049
Rail_Path | 0117Gel0781531148 | 09ef5a79-666f-4d65-ae11-371ec0050284--781531148

# IfcSlab (2)
In: KG.- Grundriss
PredefinedType: FLOOR
Pset_SlabCommon - LoadBearing: no
Allplan Attributes - Umbaukategorie: Neubau; Einheit: m²
Name | Material | Allright_Bauteil_ID | NOI_UUID
<Unnamed Element> | Stb-Bodenplatte 300 mm | 0102De 0000000002 | 73e08c98-ac40-4647-81eb-79e3cee2c94e--2 | Allplan Attributes - Gewerk: Betonarbeiten; Material: Stb-Bodenplatte
<Unnamed Element> | <Unnamed Material> 2500 mm | 0117De 0781530229 | 09ef5a79-666f-4d65-ae11-371ec0050284--781530229

# IfcStair (18)
Material: Halbpodesttreppe
Allplan Attributes - Einheit: St; Material: Halbpodesttreppe
Name | In | NumberOfRiser | RiserHeight (mm) | TreadLength (mm) | NumberOfTreads | Allright_Bauteil_ID | NOI_UUID
<Unnamed Element> | KG.- Grundriss | 18 | 178.056 | 260 | 19 | 0103Tre0000000012 | f3cc4b91-5e8d-4cad-8a0a-9c773d636232--12
<Unnamed Element> | KG.- Grundriss | 17 | 188.529 | 260 | 16 | 0103Tre0000000130 | f3cc4b91-5e8d-4cad-8a0a-9c773d636232--130
<Unnamed Element> | KG.- Grundriss | 17 | 185.294 | 270 | 18 | 0117Tre0781530373 | 09ef5a79-666f-4d65-ae11-371ec0050284--781530373
<Unnamed Element> | KG.- Grundriss | 17 | 185.294 | 275 | 16 | 0117Tre0781530427 | 09ef5a79-666f-4d65-ae11-371ec0050284--781530427
<Unnamed Element> | KG.- Grundriss | 17 | 185.294 | 275 | 16 | 0117Tre0781530475 | 09ef5a79-666f-4d65-ae11-371ec0050284--781530475
<Unnamed Element> | EG.- Grundriss | 17 | 188.529 | 260 | 16 | 0203Tre0000000299 | e0ba49bd-80eb-42fb-90d1-040cf14c70d7--299
<Unnamed Element> | EG.- Grundriss | 16 | 178.125 | 260 | 17 | 0203Tre0000000194 | e0ba49bd-80eb-42fb-90d1-040cf14c70d7--194
<Unnamed Element> | EG.- Grundriss | 16 | 178.125 | 260 | 16 | 0203Tre0000000314 | e0ba49bd-80eb-42fb-90d1-040cf14c70d7--314
<Unnamed Element> | EG.- Grundriss | 16 | 178.125 | 260 | 15 | 0203Tre0000000744 | e0ba49bd-80eb-42fb-90d1-040cf14c70d7--744
<Unnamed Element> | EG.- Grundriss | 16 | 178.125 | 260 | 15 | 0203Tre0000000805 | e0ba49bd-80eb-42fb-90d1-040cf14c70d7--805
<Unnamed Element> | OG.- Grundriss | 16 | 178.125 | 260 | 17 | 0303Tre0000000482 | b1819f14-a5ec-4190-87b8-716eaefb8ed3--482
<Unnamed Element> | OG.- Grundriss | 16 | 178.125 | 260 | 16 | 0303Tre0000000520 | b1819f14-a5ec-4190-87b8-716eaefb8ed3--520
<Unnamed Element> | OG.- Grundriss | 16 | 178.125 | 260 | 15 | 0303Tre0000000581 | b1819f14-a5ec-4190-87b8-716eaefb8ed3--581
<Unnamed Element> | OG.- Grundriss | 16 | 178.125 | 260 | 15 | 0303Tre0000000680 | b1819f14-a5ec-4190-87b8-716eaefb8ed3--680
<Unnamed Element> | OG.- Grundriss | 16 | 178.125 | 260 | 15 | 0303Tre0000000635 | b1819f14-a5ec-4190-87b8-716eaefb8ed3--635
<Unnamed Element> | DG.- Grundriss | 16 | 178.125 | 260 | 15 | 0503Tre0000000161 | 50125ca3-da93-4fa0-a6e9-69b7386460d2--161
<Unnamed Element> | DG.- Grundriss | 16 | 178.125 | 260 | 15 | 0503Tre0000000787 | 50125ca3-da93-4fa0-a6e9-69b7386460d2--787
<Unnamed Element> | DG.- Grundriss | 16 | 178.125 | 260 | 15 | 0503Tre0000000839 | 50125ca3-da93-4fa0-a6e9-69b7386460d2--839

# IfcWallStandardCase (383)
Allplan Attributes - Einheit: m³
Name | In | Material | Allright_Bauteil_ID | NOI_UUID | Object Layer Attributes #1, Allright_Bauteil_ID | Object Layer Attributes #1, Umbaukategorie | Object Layer Attributes #1, Einheit | Object Layer Attributes #1, Gewerk | Object Layer Attributes #1, NOI_UUID
<Unnamed Element> | KG.- Grundriss | Stb-Wand 250 mm | 0100HWa0780220794 | bb7460a6-57d8-45f2-954a-172a4282fe15--780220794 | 0100Wa 0780220795 | Neubau | m³ | Betonarbeiten | bb7460a6-57d8-45f2-954a-172a4282fe15--780220795 | Allplan Attributes - Object Layer Attributes #1, statisch_tragend: no
<Unnamed Element> | KG.- Grundriss | Stb-Wand 250 mm | 0100HWa0780220788 | bb7460a6-57d8-45f2-954a-172a4282fe15--780220788 | 0100Wa 0780220790 | Neubau | m³ | Betonarbeiten | bb7460a6-57d8-45f2-954a-172a4282fe15--780220790 | Allplan Attributes - Object Layer Attributes #1, statisch_tragend: no
<Unnamed Element> | KG.- Grundriss | Stb-Wand 250 mm | 0100HWa0780221182 | bb7460a6-57d8-45f2-954a-172a4282fe15--780221182 | 0100Wa 0780221183 | Neubau | m³ | Betonarbeiten | bb7460a6-57d8-45f2-954a-172a4282fe15--780221183 | Allplan Attributes - Object Layer Attributes #1, statisch_tragend: no
<Unnamed Element> | KG.- Grundriss | Stb-Wand 250 mm | 0100HWa0780220791 | bb7460a6-57d8-45f2-954a-172a4282fe15--780220791 | 0100Wa 0780220793 | Neubau | m³ | Betonarbeiten | bb7460a6-57d8-45f2-954a-172a4282fe15--780220793 | Allplan Attributes - Object Layer Attributes #1, statisch_tragend: no
<Unnamed Element> | KG.- Grundriss | Xella Multipor 120 mm, Stb-Wand 250 mm | 0100HWa0780220524 | bb7460a6-57d8-45f2-954a-172a4282fe15--780220524 | 0100Wa 0780220525 | Neubau | m² | Wärme- und Kältedämmarbeiten | bb7460a6-57d8-45f2-954a-172a4282fe15--780220525 | Allplan Attributes - Object Layer Attributes #1, statisch_tragend: no; Object Layer Attributes #1, Material: Xella Multipor; Object Layer Attributes #2, Allright_Bauteil_ID: 0100Wa 0780220526; Object Layer Attributes #2, Umbaukategorie: Neubau; Object Layer Attributes #2, Einheit: m³; Object Layer Attributes #2, Gewerk: Betonarbeiten; Object Layer Attributes #2, Material: Stb-Wand; Object Layer Attributes #2, statisch_tragend: no; Object Layer Attributes #2, NOI_UUID: bb7460a6-57d8-45f2-954a-172a4282fe15--780220526
<Unnamed Element> | KG.- Grundriss | Stb-Wand 250 mm | 0100HWa0780220463 | bb7460a6-57d8-45f2-954a-172a4282fe15--780220463 | 0100Wa 0780220479 | Neubau | m³ | Betonarbeiten | bb7460a6-57d8-45f2-954a-172a4282fe15--780220479 | Allplan Attributes - Object Layer Attributes #1, statisch_tragend: no; Object Layer Attributes #1, Material: Stb-Wand
<Unnamed Element> | KG.- Grundriss | Stb-Wand 250 mm | 0100HWa0780220679 | bb7460a6-57d8-45f2-954a-172a4282fe15--780220679 | 0100Wa 0780220680 | Neubau | m³ | Betonarbeiten | bb7460a6-57d8-45f2-954a-172a4282fe15--780220680 | Allplan Attributes - Object Layer Attributes #1, statisch_tragend: no
<Unnamed Element> | KG.- Grundriss | Stb-Wand 200 mm | 0100HWa0780221531 | bb7460a6-57d8-45f2-954a-172a4282fe15--780221531 | 0100Wa 0780221532 | Neubau | m³ | Betonarbeiten | bb7460a6-57d8-45f2-954a-172a4282fe15--780221532 | Allplan Attributes - Object Layer Attributes #1, statisch_tragend: no
<Unnamed Element> | KG.- Grundriss | Stb-Wand 200 mm | 0100HWa0780221536 | bb7460a6-57d8-45f2-954a-172a4282fe15--780221536 | 0100Wa 0780221537 | Neubau | m³ | Betonarbeiten | bb7460a6-57d8-45f2-954a-172a4282fe15--780221537 | Allplan Attributes - Object Layer Attributes #1, statisch_tragend: no
<Unnamed Element> | KG.- Grundriss | Stb-Wand 200 mm | 0100HWa0780221546 | bb7460a6-57d8-45f2-954a-172a4282fe15--780221546 | 0100Wa 0780221547 | Neubau | m³ | Betonarbeiten | bb7460a6-57d8-45f2-954a-172a4282fe15--780221547 | Allplan Attributes - Object Layer Attributes #1, statisch_tragend: no
<Unnamed Element> | KG.- Grundriss | Xella Multipor 120 mm, Stb-Wand 240 mm | 0100HWa0780220629 | bb7460a6-57d8-45f2-954a-172a4282fe15--780220629 | 0100Wa 0780220630 | Neubau | m² | Wärme- und Kältedämmarbeiten | bb7460a6-57d8-45f2-954a-172a4282fe15--780220630 | Allplan Attributes - Object Layer Attributes #1, statisch_tragend: no; Object Layer Attributes #2, Allright_Bauteil_ID: 0100Wa 0780220631; Object Layer Attributes #2, Umbaukategorie: Neubau; Object Layer Attributes #2, Einheit: m³; Object Layer Attributes #2, Gewerk: Betonarbeiten; Object Layer Attributes #2, statisch_tragend: no; Object Layer Attributes #2, NOI_UUID: bb7460a6-57d8-45f2-954a-172a4282fe15--780220631
<Unnamed Element> | KG.- Grundriss | Xella Multipor 120 mm, Stb-Wand 250 mm | 0100HWa0780220564 | bb7460a6-57d8-45f2-954a-172a4282fe15--780220564 | 0100Wa 0780220565 | Neubau | m² | Wärme- und Kältedämmarbeiten | bb7460a6-57d8-45f2-954a-172a4282fe15--780220565 | Allplan Attributes - Object Layer Attributes #1, statisch_tragend: no; Object Layer Attributes #2, Allright_Bauteil_ID: 0100Wa 0780220566; Object Layer Attributes #2, Umbaukategorie: Neubau; Object Layer Attributes #2, Einheit: m³; Object Layer Attributes #2, Gewerk: Betonarbeiten; Object Layer Attributes #2, statisch_tragend: no; Object Layer Attributes #2, NOI_UUID: bb7460a6-57d8-45f2-954a-172a4282fe15--780220566
<Unnamed Element> | KG.- Grundriss | Xella Multipor 120 mm, Stb-Wand 250 mm | 0100HWa0780220593 | bb7460a6-57d8-45f2-954a-172a4282fe15--780220593 | 0100Wa 0780220594 | Neubau | m² | Wärme- und Kältedämmarbeiten | bb7460a6-57d8-45f2-954a-172a4282fe15--780220594 | Allplan Attributes - Object Layer Attributes #1, statisch_tragend: no; Object Layer Attributes #2, Allright_Bauteil_ID: 0100Wa 0780220595; Object Layer Attributes #2, Umbaukategorie: Neubau; Object Layer Attributes #2, Einheit: m³; Object Layer Attributes #2, Gewerk: Betonarbeiten; Object Layer Attributes #2, statisch_tragend: no; Object Layer Attributes #2, NOI_UUID: bb7460a6-57d8-45f2-954a-172a4282fe15--780220595
<Unnamed Element> | KG.- Grundriss | Stb-Wand 200 mm | 0100HWa0780221558 | bb7460a6-57d8-45f2-954a-172a4282fe15--780221558 | 0100Wa 0780221559 | Neubau | m³ | Betonarbeiten | bb7460a6-57d8-45f2-954a-172a4282fe15--780221559 | Allplan Attributes - Object Layer Attributes #1, statisch_tragend: no
<Unnamed Element> | KG.- Grundriss | Stb-Wand 250 mm | 0100HWa0783112780 | bb7460a6-57d8-45f2-954a-172a4282fe15--783112780 | 0100Wa 0783112781 | Neubau | m³ | Betonarbeiten | bb7460a6-57d8-45f2-954a-172a4282fe15--783112781 | Allplan Attributes - Object Layer Attributes #1, statisch_tragend: no
<Unnamed Element> | KG.- Grundriss | Xella Multipor 120 mm, Stb-Wand 250 mm | 0100HWa0780220832 | bb7460a6-57d8-45f2-954a-172a4282fe15--780220832 | 0100Wa 0780220833 | Neubau | m² | Wärme- und Kältedämmarbeiten | bb7460a6-57d8-45f2-954a-172a4282fe15--780220833 | Allplan Attributes - Object Layer Attributes #1, statisch_tragend: no; Object Layer Attributes #2, Allright_Bauteil_ID: 0100Wa 0780220834; Object Layer Attributes #2, Umbaukategorie: Neubau; Object Layer Attributes #2, Einheit: m³; Object Layer Attributes #2, Gewerk: Betonarbeiten; Object Layer Attributes #2, statisch_tragend: no; Object Layer Attributes #2, NOI_UUID: bb7460a6-57d8-45f2-954a-172a4282fe15--780220834
<Unnamed Element> | KG.- Grundriss | Stb-Wand 250 mm | 0100HWa0783112767 | bb7460a6-57d8-45f2-954a-172a4282fe15--783112767 | 0100Wa 0783112768 | Neubau | m³ | Betonarbeiten | bb7460a6-57d8-45f2-954a-172a4282fe15--783112768 | Allplan Attributes - Object Layer Attributes #1, statisch_tragend: no
<Unnamed Element> | KG.- Grundriss | Stb-Wand 200 mm | 0100HWa0783113267 | bb7460a6-57d8-45f2-954a-172a4282fe15--783113267 | 0100Wa 0783113268 | Neubau | m³ | Betonarbeiten | bb7460a6-57d8-45f2-954a-172a4282fe15--783113268
<Unnamed Element> | KG.- Grundriss | KSPE Mauerwerk 200 mm | 0100HWa0783112827 | bb7460a6-57d8-45f2-954a-172a4282fe15--783112827 | 0100Wa 0783112828 | Neubau | m³ | Mauerarbeiten | bb7460a6-57d8-45f2-954a-172a4282fe15--783112828 | Allplan Attributes - Object Layer Attributes #1, statisch_tragend: no; Object Layer Attributes #1, Material: KSPE Mauerwerk
<Unnamed Element> | KG.- Grundriss | KSPE Mauerwerk 200 mm | 0100HWa0783112797 | bb7460a6-57d8-45f2-954a-172a4282fe15--783112797 | 0100Wa 0783112798 | Neubau | m³ | Mauerarbeiten | bb7460a6-57d8-45f2-954a-172a4282fe15--783112798 | Allplan Attributes - Object Layer Attributes #1, statisch_tragend: no; Object Layer Attributes #1, Material: KSPE Mauerwerk
<Unnamed Element> | KG.- Grundriss | KSPE Mauerwerk 200 mm | 0100HWa0783112810 | bb7460a6-57d8-45f2-954a-172a4282fe15--783112810 | 0100Wa 0783112811 | Neubau | m³ | Mauerarbeiten | bb7460a6-57d8-45f2-954a-172a4282fe15--783112811 | Allplan Attributes - Object Layer Attributes #1, statisch_tragend: no; Object Layer Attributes #1, Material: KSPE Mauerwerk
<Unnamed Element> | KG.- Grundriss | KSPE Mauerwerk 200 mm | 0100HWa0783113197 | bb7460a6-57d8-45f2-954a-172a4282fe15--783113197 | 0100Wa 0783113198 | Neubau | m³ | Mauerarbeiten | bb7460a6-57d8-45f2-954a-172a4282fe15--783113198 | Allplan Attributes - Object Layer Attributes #1, statisch_tragend: no; Object Layer Attributes #1, Material: KSPE Mauerwerk
<Unnamed Element> | KG.- Grundriss | Stb-Wand 250 mm | 0100HWa0783113909 | bb7460a6-57d8-45f2-954a-172a4282fe15--783113909 | 0100Wa 0783113911 | Neubau | m³ | Betonarbeiten | bb7460a6-57d8-45f2-954a-172a4282fe15--783113911 | Allplan Attributes - Object Layer Attributes #1, statisch_tragend: no
<Unnamed Element> | KG.- Grundriss | Metallgitterwand 50 mm | 0117HWa0781530615 | 09ef5a79-666f-4d65-ae11-371ec0050284--781530615 | 0117Wa 0781530823 |  | m² | Stahlbauarbeiten | 09ef5a79-666f-4d65-ae11-371ec0050284--781530823
<Unnamed Element> | KG.- Grundriss | Metallgitterwand 50 mm | 0117HWa0781530617 | 09ef5a79-666f-4d65-ae11-371ec0050284--781530617 | 0117Wa 0781530821 |  | m² | Stahlbauarbeiten | 09ef5a79-666f-4d65-ae11-371ec0050284--781530821
<Unnamed Element> | KG.- Grundriss | Metallgitterwand 50 mm | 0117HWa0781530619 | 09ef5a79-666f-4d65-ae11-371ec0050284--781530619 | 0117Wa 0781530819 |  | m² | Stahlbauarbeiten | 09ef5a79-666f-4d65-ae11-371ec0050284--781530819
<Unnamed Element> | KG.- Grundriss | Metallgitterwand 50 mm | 0117HWa0781530621 | 09ef5a79-666f-4d65-ae11-371ec0050284--781530621 | 0117Wa 0781530817 |  | m² | Stahlbauarbeiten | 09ef5a79-666f-4d65-ae11-371ec0050284--781530817
<Unnamed Element> | KG.- Grundriss | Metallgitterwand 50 mm | 0117HWa0781530623 | 09ef5a79-666f-4d65-ae11-371ec0050284--781530623 | 0117Wa 0781530829 |  | m² | Stahlbauarbeiten | 09ef5a79-666f-4d65-ae11-371ec0050284--781530829
<Unnamed Element> | KG.- Grundriss | Metallgitterwand 50 mm | 0117HWa0781530624 | 09ef5a79-666f-4d65-ae11-371ec0050284--781530624 | 0117Wa 0781530831 |  | m² | Stahlbauarbeiten | 09ef5a79-666f-4d65-ae11-371ec0050284--781530831
<Unnamed Element> | KG.- Grundriss | Metallgitterwand 50 mm | 0117HWa0781530625 | 09ef5a79-666f-4d65-ae11-371ec0050284--781530625 | 0117Wa 0781530833 |  | m² | Stahlbauarbeiten | 09ef5a79-666f-4d65-ae11-371ec0050284--781530833
<Unnamed Element> | KG.- Grundriss | Metallgitterwand 50 mm | 0117HWa0781530626 | 09ef5a79-666f-4d65-ae11-371ec0050284--781530626 | 0117Wa 0781530835 |  | m² | Stahlbauarbeiten | 09ef5a79-666f-4d65-ae11-371ec0050284--781530835
<Unnamed Element> | KG.- Grundriss | Metallgitterwand 50 mm | 0117HWa0781530631 | 09ef5a79-666f-4d65-ae11-371ec0050284--781530631 | 0117Wa 0781530825 |  | m² | Stahlbauarbeiten | 09ef5a79-666f-4d65-ae11-371ec0050284--781530825
<Unnamed Element> | KG.- Grundriss | Metallgitterwand 50 mm | 0117HWa0781530633 | 09ef5a79-666f-4d65-ae11-371ec0050284--781530633 | 0117Wa 0781530827 |  | m² | Stahlbauarbeiten | 09ef5a79-666f-4d65-ae11-371ec0050284--781530827
<Unnamed Element> | KG.- Grundriss | Metallgitterwand 50 mm | 0117HWa0781530635 | 09ef5a79-666f-4d65-ae11-371ec0050284--781530635 | 0117Wa 0781530874 |  | m² | Stahlbauarbeiten | 09ef5a79-666f-4d65-ae11-371ec0050284--781530874
<Unnamed Element> | KG.- Grundriss | Metallgitterwand 50 mm | 0117HWa0781530643 | 09ef5a79-666f-4d65-ae11-371ec0050284--781530643 | 0117Wa 0781530862 |  | m² | Stahlbauarbeiten | 09ef5a79-666f-4d65-ae11-371ec0050284--781530862
<Unnamed Element> | KG.- Grundriss | Metallgitterwand 50 mm | 0117HWa0781530647 | 09ef5a79-666f-4d65-ae11-371ec0050284--781530647 | 0117Wa 0781530866 |  | m² | Stahlbauarbeiten | 09ef5a79-666f-4d65-ae11-371ec0050284--781530866
<Unnamed Element> | KG.- Grundriss | Metallgitterwand 50 mm | 0117HWa0781530656 | 09ef5a79-666f-4d65-ae11-371ec0050284--781530656 | 0117Wa 0781530845 |  | m² | Stahlbauarbeiten | 09ef5a79-666f-4d65-ae11-371ec0050284--781530845
<Unnamed Element> | KG.- Grundriss | Metallgitterwand 50 mm | 0117HWa0781530657 | 09ef5a79-666f-4d65-ae11-371ec0050284--781530657 | 0117Wa 0781530851 |  | m² | Stahlbauarbeiten | 09ef5a79-666f-4d65-ae11-371ec0050284--781530851
<Unnamed Element> | KG.- Grundriss | Metallgitterwand 50 mm | 0117HWa0781530660 | 09ef5a79-666f-4d65-ae11-371ec0050284--781530660 | 0117Wa 0781530854 |  | m² | Stahlbauarbeiten | 09ef5a79-666f-4d65-ae11-371ec0050284--781530854
<Unnamed Element> | KG.- Grundriss | Metallgitterwand 50 mm | 0117HWa0781530663 | 09ef5a79-666f-4d65-ae11-371ec0050284--781530663 | 0117Wa 0781530848 |  | m² | Stahlbauarbeiten | 09ef5a79-666f-4d65-ae11-371ec0050284--781530848
<Unnamed Element> | KG.- Grundriss | Metallgitterwand 50 mm | 0117HWa0781530667 | 09ef5a79-666f-4d65-ae11-371ec0050284--781530667 | 0117Wa 0781530837 |  | m² | Stahlbauarbeiten | 09ef5a79-666f-4d65-ae11-371ec0050284--781530837
<Unnamed Element> | KG.- Grundriss | Metallgitterwand 50 mm | 0117HWa0781530674 | 09ef5a79-666f-4d65-ae11-371ec0050284--781530674 | 0117Wa 0781530839 |  | m² | Stahlbauarbeiten | 09ef5a79-666f-4d65-ae11-371ec0050284--781530839
<Unnamed Element> | KG.- Grundriss | Metallgitterwand 50 mm | 0117HWa0781530677 | 09ef5a79-666f-4d65-ae11-371ec0050284--781530677 | 0117Wa 0781530841 |  | m² | Stahlbauarbeiten | 09ef5a79-666f-4d65-ae11-371ec0050284--781530841
<Unnamed Element> | KG.- Grundriss | Metallgitterwand 50 mm | 0117HWa0781530678 | 09ef5a79-666f-4d65-ae11-371ec0050284--781530678 | 0117Wa 0781531136 |  | m² | Stahlbauarbeiten | 09ef5a79-666f-4d65-ae11-371ec0050284--781531136
<Unnamed Element> | KG.- Grundriss | Metallgitterwand 50 mm | 0117HWa0781530704 | 09ef5a79-666f-4d65-ae11-371ec0050284--781530704 | 0117Wa 0781530815 |  | m² | Stahlbauarbeiten | 09ef5a79-666f-4d65-ae11-371ec0050284--781530815
<Unnamed Element> | KG.- Grundriss | Metallgitterwand 50 mm | 0117HWa0781530707 | 09ef5a79-666f-4d65-ae11-371ec0050284--781530707 | 0117Wa 0781531013 |  | m² | Stahlbauarbeiten | 09ef5a79-666f-4d65-ae11-371ec0050284--781531013
<Unnamed Element> | KG.- Grundriss | Metallgitterwand 50 mm | 0117HWa0781530708 | 09ef5a79-666f-4d65-ae11-371ec0050284--781530708 | 0117Wa 0781531015 |  | m² | Stahlbauarbeiten | 09ef5a79-666f-4d65-ae11-371ec0050284--781531015
<Unnamed Element> | KG.- Grundriss | Metallgitterwand 50 mm | 0117HWa0781530715 | 09ef5a79-666f-4d65-ae11-371ec0050284--781530715 | 0117Wa 0781530880 |  | m² | Stahlbauarbeiten | 09ef5a79-666f-4d65-ae11-371ec0050284--781530880
<Unnamed Element> | KG.- Grundriss | Metallgitterwand 50 mm | 0117HWa0781530721 | 09ef5a79-666f-4d65-ae11-371ec0050284--781530721 | 0117Wa 0781530876 |  | m² | Stahlbauarbeiten | 09ef5a79-666f-4d65-ae11-371ec0050284--781530876
<Unnamed Element> | KG.- Grundriss | Metallgitterwand 50 mm | 0117HWa0781530881 | 09ef5a79-666f-4d65-ae11-371ec0050284--781530881 | 0117Wa 0781530913 |  | m² | Stahlbauarbeiten | 09ef5a79-666f-4d65-ae11-371ec0050284--781530913
<Unnamed Element> | KG.- Grundriss | Metallgitterwand 50 mm | 0117HWa0781530883 | 09ef5a79-666f-4d65-ae11-371ec0050284--781530883 | 0117Wa 0781530906 |  | m² | Stahlbauarbeiten | 09ef5a79-666f-4d65-ae11-371ec0050284--781530906
<Unnamed Element> | KG.- Grundriss | Metallgitterwand 50 mm | 0117HWa0781530885 | 09ef5a79-666f-4d65-ae11-371ec0050284--781530885 | 0117Wa 0781530911 |  | m² | Stahlbauarbeiten | 09ef5a79-666f-4d65-ae11-371ec0050284--781530911
<Unnamed Element> | KG.- Grundriss | Metallgitterwand 50 mm | 0117HWa0781530914 | 09ef5a79-666f-4d65-ae11-371ec0050284--781530914 | 0117Wa 0781530933 |  | m² | Stahlbauarbeiten | 09ef5a79-666f-4d65-ae11-371ec0050284--781530933
<Unnamed Element> | KG.- Grundriss | Metallgitterwand 50 mm | 0117HWa0781530916 | 09ef5a79-666f-4d65-ae11-371ec0050284--781530916 | 0117Wa 0781530931 |  | m² | Stahlbauarbeiten | 09ef5a79-666f-4d65-ae11-371ec0050284--781530931
<Unnamed Element> | KG.- Grundriss | Metallgitterwand 50 mm | 0117HWa0781530936 | 09ef5a79-666f-4d65-ae11-371ec0050284--781530936 | 0117Wa 0781531139 |  | m² | Stahlbauarbeiten | 09ef5a79-666f-4d65-ae11-371ec0050284--781531139
<Unnamed Element> | KG.- Grundriss | Metallgitterwand 50 mm | 0117HWa0781530938 | 09ef5a79-666f-4d65-ae11-371ec0050284--781530938 | 0117Wa 0781530967 |  | m² | Stahlbauarbeiten | 09ef5a79-666f-4d65-ae11-371ec0050284--781530967
<Unnamed Element> | KG.- Grundriss | Metallgitterwand 50 mm | 0117HWa0781530940 | 09ef5a79-666f-4d65-ae11-371ec0050284--781530940 | 0117Wa 0781530969 |  | m² | Stahlbauarbeiten | 09ef5a79-666f-4d65-ae11-371ec0050284--781530969
<Unnamed Element> | KG.- Grundriss | Metallgitterwand 50 mm | 0117HWa0781530942 | 09ef5a79-666f-4d65-ae11-371ec0050284--781530942 | 0117Wa 0781531146 |  | m² | Stahlbauarbeiten | 09ef5a79-666f-4d65-ae11-371ec0050284--781531146
<Unnamed Element> | KG.- Grundriss | Metallgitterwand 50 mm | 0117HWa0781530947 | 09ef5a79-666f-4d65-ae11-371ec0050284--781530947 | 0117Wa 0781530963 |  | m² | Stahlbauarbeiten | 09ef5a79-666f-4d65-ae11-371ec0050284--781530963
<Unnamed Element> | KG.- Grundriss | Metallgitterwand 50 mm | 0117HWa0781530950 | 09ef5a79-666f-4d65-ae11-371ec0050284--781530950 | 0117Wa 0781530971 |  | m² | Stahlbauarbeiten | 09ef5a79-666f-4d65-ae11-371ec0050284--781530971
<Unnamed Element> | KG.- Grundriss | Metallgitterwand 50 mm | 0117HWa0781530956 | 09ef5a79-666f-4d65-ae11-371ec0050284--781530956 | 0117Wa 0781531143 |  | m² | Stahlbauarbeiten | 09ef5a79-666f-4d65-ae11-371ec0050284--781531143
<Unnamed Element> | KG.- Grundriss | Metallgitterwand 50 mm | 0117HWa0781530982 | 09ef5a79-666f-4d65-ae11-371ec0050284--781530982 | 0117Wa 0781530992 |  | m² | Stahlbauarbeiten | 09ef5a79-666f-4d65-ae11-371ec0050284--781530992
<Unnamed Element> | KG.- Grundriss | Metallgitterwand 50 mm | 0117HWa0781530993 | 09ef5a79-666f-4d65-ae11-371ec0050284--781530993 | 0117Wa 0781531011 |  | m² | Stahlbauarbeiten | 09ef5a79-666f-4d65-ae11-371ec0050284--781531011
<Unnamed Element> | KG.- Grundriss | Metallgitterwand 50 mm | 0117HWa0781531066 | 09ef5a79-666f-4d65-ae11-371ec0050284--781531066 | 0117Wa 0781531133 |  | m² | Stahlbauarbeiten | 09ef5a79-666f-4d65-ae11-371ec0050284--781531133
<Unnamed Element> | KG.- Grundriss | Metallgitterwand 50 mm | 0117HWa0781531068 | 09ef5a79-666f-4d65-ae11-371ec0050284--781531068 | 0117Wa 0781531131 |  | m² | Stahlbauarbeiten | 09ef5a79-666f-4d65-ae11-371ec0050284--781531131
<Unnamed Element> | KG.- Grundriss | Metallgitterwand 50 mm | 0117HWa0781531071 | 09ef5a79-666f-4d65-ae11-371ec0050284--781531071 | 0117Wa 0781531119 |  | m² | Stahlbauarbeiten | 09ef5a79-666f-4d65-ae11-371ec0050284--781531119
<Unnamed Element> | KG.- Grundriss | Metallgitterwand 50 mm | 0117HWa0781531073 | 09ef5a79-666f-4d65-ae11-371ec0050284--781531073 | 0117Wa 0781531117 |  | m² | Stahlbauarbeiten | 09ef5a79-666f-4d65-ae11-371ec0050284--781531117
<Unnamed Element> | KG.- Grundriss | Metallgitterwand 50 mm | 0117HWa0781531076 | 09ef5a79-666f-4d65-ae11-371ec0050284--781531076 | 0117Wa 0781531124 |  | m² | Stahlbauarbeiten | 09ef5a79-666f-4d65-ae11-371ec0050284--781531124
<Unnamed Element> | KG.- Grundriss | Metallgitterwand 50 mm | 0117HWa0781531081 | 09ef5a79-666f-4d65-ae11-371ec0050284--781531081 | 0117Wa 0781531129 |  | m² | Stahlbauarbeiten | 09ef5a79-666f-4d65-ae11-371ec0050284--781531129
<Unnamed Element> | KG.- Grundriss | <Unnamed Material> 60 mm | 0117HWa0781537553 | 09ef5a79-666f-4d65-ae11-371ec0050284--781537553 | 0117Wa 0781538275 | Neubau | m³ |  | 09ef5a79-666f-4d65-ae11-371ec0050284--781538275 | Allplan Attributes - Object Layer Attributes #1, statisch_tragend: no
<Unnamed Element> | KG.- Grundriss | <Unnamed Material> 60 mm | 0117HWa0781537563 | 09ef5a79-666f-4d65-ae11-371ec0050284--781537563 | 0117Wa 0781538384 | Neubau | m³ |  | 09ef5a79-666f-4d65-ae11-371ec0050284--781538384 | Allplan Attributes - Object Layer Attributes #1, statisch_tragend: no
<Unnamed Element> | KG.- Grundriss | <Unnamed Material> 60 mm | 0117HWa0781537619 | 09ef5a79-666f-4d65-ae11-371ec0050284--781537619 | 0117Wa 0781538023 | Neubau | m³ |  | 09ef5a79-666f-4d65-ae11-371ec0050284--781538023 | Allplan Attributes - Object Layer Attributes #1, statisch_tragend: no
<Unnamed Element> | KG.- Grundriss | <Unnamed Material> 60 mm | 0117HWa0781537695 | 09ef5a79-666f-4d65-ae11-371ec0050284--781537695 | 0117Wa 0781538155 | Neubau | m³ |  | 09ef5a79-666f-4d65-ae11-371ec0050284--781538155 | Allplan Attributes - Object Layer Attributes #1, statisch_tragend: no
<Unnamed Element> | KG.- Grundriss | <Unnamed Material> 60 mm | 0117HWa0781537696 | 09ef5a79-666f-4d65-ae11-371ec0050284--781537696 | 0117Wa 0781538149 | Neubau | m³ |  | 09ef5a79-666f-4d65-ae11-371ec0050284--781538149 | Allplan Attributes - Object Layer Attributes #1, statisch_tragend: no
<Unnamed Element> | KG.- Grundriss | <Unnamed Material> 60 mm | 0117HWa0781537698 | 09ef5a79-666f-4d65-ae11-371ec0050284--781537698 | 0117Wa 0781538151 | Neubau | m³ |  | 09ef5a79-666f-4d65-ae11-371ec0050284--781538151 | Allplan Attributes - Object Layer Attributes #1, statisch_tragend: no
<Unnamed Element> | KG.- Grundriss | <Unnamed Material> 60 mm | 0117HWa0781537699 | 09ef5a79-666f-4d65-ae11-371ec0050284--781537699 | 0117Wa 0781538147 | Neubau | m³ |  | 09ef5a79-666f-4d65-ae11-371ec0050284--781538147 | Allplan Attributes - Object Layer Attributes #1, statisch_tragend: no
<Unnamed Element> | KG.- Grundriss | <Unnamed Material> 60 mm | 0117HWa0781537700 | 09ef5a79-666f-4d65-ae11-371ec0050284--781537700 | 0117Wa 0781538145 | Neubau | m³ |  | 09ef5a79-666f-4d65-ae11-371ec0050284--781538145 | Allplan Attributes - Object Layer Attributes #1, statisch_tragend: no
<Unnamed Element> | KG.- Grundriss | <Unnamed Material> 60 mm | 0117HWa0781537707 | 09ef5a79-666f-4d65-ae11-371ec0050284--781537707 | 0117Wa 0781538143 | Neubau | m³ |  | 09ef5a79-666f-4d65-ae11-371ec0050284--781538143 | Allplan Attributes - Object Layer Attributes #1, statisch_tragend: no
<Unnamed Element> | KG.- Grundriss | <Unnamed Material> 100 mm | 0117HWa0781537717 | 09ef5a79-666f-4d65-ae11-371ec0050284--781537717 | 0117Wa 0781538135 | Neubau | m³ |  | 09ef5a79-666f-4d65-ae11-371ec0050284--781538135 | Allplan Attributes - Object Layer Attributes #1, statisch_tragend: no
<Unnamed Element> | KG.- Grundriss | <Unnamed Material> 100 mm | 0117HWa0781537719 | 09ef5a79-666f-4d65-ae11-371ec0050284--781537719 | 0117Wa 0781538131 | Neubau | m³ |  | 09ef5a79-666f-4d65-ae11-371ec0050284--781538131 | Allplan Attributes - Object Layer Attributes #1, statisch_tragend: no
<Unnamed Element> | KG.- Grundriss | <Unnamed Material> 100 mm | 0117HWa0781537803 | 09ef5a79-666f-4d65-ae11-371ec0050284--781537803 | 0117Wa 0781538039 | Neubau | m³ |  | 09ef5a79-666f-4d65-ae11-371ec0050284--781538039 | Allplan Attributes - Object Layer Attributes #1, statisch_tragend: no
<Unnamed Element> | KG.- Grundriss | <Unnamed Material> 100 mm | 0117HWa0781537825 | 09ef5a79-666f-4d65-ae11-371ec0050284--781537825 | 0117Wa 0781538017 | Neubau | m³ |  | 09ef5a79-666f-4d65-ae11-371ec0050284--781538017 | Allplan Attributes - Object Layer Attributes #1, statisch_tragend: no
<Unnamed Element> | KG.- Grundriss | <Unnamed Material> 60 mm | 0117HWa0781538376 | 09ef5a79-666f-4d65-ae11-371ec0050284--781538376 | 0117Wa 0781538380 | Neubau | m³ |  | 09ef5a79-666f-4d65-ae11-371ec0050284--781538380 | Allplan Attributes - Object Layer Attributes #1, statisch_tragend: no
<Unnamed Element> | KG.- Grundriss | Stb-Wand 175 mm | 0117HWa0781540040 | 09ef5a79-666f-4d65-ae11-371ec0050284--781540040 | 0117Wa 0781541240 | Neubau | m³ |  | 09ef5a79-666f-4d65-ae11-371ec0050284--781541240 | Allplan Attributes - Object Layer Attributes #1, statisch_tragend: no; Object Layer Attributes #1, Material: Stb-Wand
<Unnamed Element> | KG.- Grundriss | Stb-Wand 175 mm | 0117HWa0781540042 | 09ef5a79-666f-4d65-ae11-371ec0050284--781540042 | 0117Wa 0781540724 | Neubau | m³ |  | 09ef5a79-666f-4d65-ae11-371ec0050284--781540724 | Allplan Attributes - Object Layer Attributes #1, statisch_tragend: no; Object Layer Attributes #1, Material: Stb-Wand
<Unnamed Element> | KG.- Grundriss | Stb-Wand 200 mm | 0117HWa0781540053 | 09ef5a79-666f-4d65-ae11-371ec0050284--781540053 | 0117Wa 0781540722 | Neubau | m³ |  | 09ef5a79-666f-4d65-ae11-371ec0050284--781540722 | Allplan Attributes - Object Layer Attributes #1, statisch_tragend: no; Object Layer Attributes #1, Material: Stb-Wand
<Unnamed Element> | KG.- Grundriss | Stb-Wand 250 mm | 0117HWa0781540055 | 09ef5a79-666f-4d65-ae11-371ec0050284--781540055 | 0117Wa 0781540964 | Neubau | m³ |  | 09ef5a79-666f-4d65-ae11-371ec0050284--781540964 | Allplan Attributes - Object Layer Attributes #1, statisch_tragend: no
<Unnamed Element> | KG.- Grundriss | Stb-Wand 200 mm, <Unnamed Material> 60 mm | 0117HWa0781540057 | 09ef5a79-666f-4d65-ae11-371ec0050284--781540057 | 0117Wa 0781541052 | Neubau | m³ |  | 09ef5a79-666f-4d65-ae11-371ec0050284--781541052 | Allplan Attributes - Object Layer Attributes #1, statisch_tragend: no; Object Layer Attributes #2, Allright_Bauteil_ID: 0117Wa 0781541050; Object Layer Attributes #2, Umbaukategorie: Neubau; Object Layer Attributes #2, Einheit: m³; Object Layer Attributes #2, statisch_tragend: no; Object Layer Attributes #2, NOI_UUID: 09ef5a79-666f-4d65-ae11-371ec0050284--781541050
<Unnamed Element> | KG.- Grundriss | Stb-Wand 200 mm, <Unnamed Material> 60 mm | 0117HWa0781540058 | 09ef5a79-666f-4d65-ae11-371ec0050284--781540058 | 0117Wa 0781540831 | Neubau | m³ |  | 09ef5a79-666f-4d65-ae11-371ec0050284--781540831 | Allplan Attributes - Object Layer Attributes #1, statisch_tragend: no; Object Layer Attributes #2, Allright_Bauteil_ID: 0117Wa 0781540814; Object Layer Attributes #2, Umbaukategorie: Neubau; Object Layer Attributes #2, Einheit: m³; Object Layer Attributes #2, statisch_tragend: no; Object Layer Attributes #2, NOI_UUID: 09ef5a79-666f-4d65-ae11-371ec0050284--781540814
<Unnamed Element> | KG.- Grundriss | Stb-Wand 200 mm | 0117HWa0781540059 | 09ef5a79-666f-4d65-ae11-371ec0050284--781540059 | 0117Wa 0781540875 | Neubau | m³ |  | 09ef5a79-666f-4d65-ae11-371ec0050284--781540875 | Allplan Attributes - Object Layer Attributes #1, statisch_tragend: no
<Unnamed Element> | KG.- Grundriss | Stb-Wand 200 mm, <Unnamed Material> 60 mm | 0117HWa0781540061 | 09ef5a79-666f-4d65-ae11-371ec0050284--781540061 | 0117Wa 0781540923 | Neubau | m³ |  | 09ef5a79-666f-4d65-ae11-371ec0050284--781540923 | Allplan Attributes - Object Layer Attributes #1, statisch_tragend: no; Object Layer Attributes #2, Allright_Bauteil_ID: 0117Wa 0781541026; Object Layer Attributes #2, Umbaukategorie: Neubau; Object Layer Attributes #2, Einheit: m³; Object Layer Attributes #2, statisch_tragend: no; Object Layer Attributes #2, NOI_UUID: 09ef5a79-666f-4d65-ae11-371ec0050284--781541026
<Unnamed Element> | KG.- Grundriss | <Unnamed Material> 120 mm | 0117HWa0781540063 | 09ef5a79-666f-4d65-ae11-371ec0050284--781540063 | 0117Wa 0781540730 | Neubau | m³ |  | 09ef5a79-666f-4d65-ae11-371ec0050284--781540730 | Allplan Attributes - Object Layer Attributes #1, statisch_tragend: no
<Unnamed Element> | KG.- Grundriss | <Unnamed Material> 120 mm | 0117HWa0781540065 | 09ef5a79-666f-4d65-ae11-371ec0050284--781540065 | 0117Wa 0781541249 | Neubau | m³ |  | 09ef5a79-666f-4d65-ae11-371ec0050284--781541249 | Allplan Attributes - Object Layer Attributes #1, statisch_tragend: no
<Unnamed Element> | KG.- Grundriss | Stb-Wand 200 mm | 0117HWa0781540067 | 09ef5a79-666f-4d65-ae11-371ec0050284--781540067 | 0117Wa 0781540633 |  | m² | Mauerarbeiten | 09ef5a79-666f-4d65-ae11-371ec0050284--781540633
<Unnamed Element> | KG.- Grundriss | <Unnamed Material> 120 mm | 0117HWa0781540069 | 09ef5a79-666f-4d65-ae11-371ec0050284--781540069 | 0117Wa 0781540790 | Neubau | m³ |  | 09ef5a79-666f-4d65-ae11-371ec0050284--781540790 | Allplan Attributes - Object Layer Attributes #1, statisch_tragend: no
<Unnamed Element> | KG.- Grundriss | KSPE Mauerwerk 115 mm | 0117HWa0781540073 | 09ef5a79-666f-4d65-ae11-371ec0050284--781540073 | 0117Wa 0781541132 | Neubau | m³ |  | 09ef5a79-666f-4d65-ae11-371ec0050284--781541132 | Allplan Attributes - Object Layer Attributes #1, statisch_tragend: no; Object Layer Attributes #1, Material: KSPE Mauerwerk
<Unnamed Element> | KG.- Grundriss | Stb-Wand 200 mm | 0117HWa0781540077 | 09ef5a79-666f-4d65-ae11-371ec0050284--781540077 | 0117Wa 0781541120 | Neubau | m³ |  | 09ef5a79-666f-4d65-ae11-371ec0050284--781541120 | Allplan Attributes - Object Layer Attributes #1, statisch_tragend: no
<Unnamed Element> | KG.- Grundriss | Stb-Wand 240 mm | 0117HWa0781540080 | 09ef5a79-666f-4d65-ae11-371ec0050284--781540080 | 0117Wa 0781540761 | Neubau | m³ |  | 09ef5a79-666f-4d65-ae11-371ec0050284--781540761 | Allplan Attributes - Object Layer Attributes #1, statisch_tragend: no; Object Layer Attributes #1, Material: Stb-Wand
2 x <Unnamed Element> | KG.- Grundriss | <Unnamed Material> 120 mm | 0117HWa0781540082 | 09ef5a79-666f-4d65-ae11-371ec0050284--781540082 | 0117Wa 0781540586 | Neubau | m³ |  | 09ef5a79-666f-4d65-ae11-371ec0050284--781540586 | Allplan Attributes - Object Layer Attributes #1, statisch_tragend: no
<Unnamed Element> | KG.- Grundriss | Stb-Wand 250 mm | 0117HWa0781540084 | 09ef5a79-666f-4d65-ae11-371ec0050284--781540084 | 0117Wa 0781540927 | Neubau | m³ |  | 09ef5a79-666f-4d65-ae11-371ec0050284--781540927 | Allplan Attributes - Object Layer Attributes #1, statisch_tragend: no
<Unnamed Element> | KG.- Grundriss | <Unnamed Material> 120 mm | 0117HWa0781540086 | 09ef5a79-666f-4d65-ae11-371ec0050284--781540086 | 0117Wa 0781540592 | Neubau | m³ |  | 09ef5a79-666f-4d65-ae11-371ec0050284--781540592 | Allplan Attributes - Object Layer Attributes #1, statisch_tragend: no
<Unnamed Element> | KG.- Grundriss | <Unnamed Material> 120 mm | 0117HWa0781540087 | 09ef5a79-666f-4d65-ae11-371ec0050284--781540087 | 0117Wa 0781540662 | Neubau | m³ |  | 09ef5a79-666f-4d65-ae11-371ec0050284--781540662 | Allplan Attributes - Object Layer Attributes #1, statisch_tragend: no
<Unnamed Element> | KG.- Grundriss | <Unnamed Material> 120 mm | 0117HWa0781540090 | 09ef5a79-666f-4d65-ae11-371ec0050284--781540090 | 0117Wa 0781540666 | Neubau | m³ |  | 09ef5a79-666f-4d65-ae11-371ec0050284--781540666 | Allplan Attributes - Object Layer Attributes #1, statisch_tragend: no
<Unnamed Element> | KG.- Grundriss | Stb-Wand 250 mm | 0117HWa0781540091 | 09ef5a79-666f-4d65-ae11-371ec0050284--781540091 | 0117Wa 0781540668 | Neubau | m³ |  | 09ef5a79-666f-4d65-ae11-371ec0050284--781540668 | Allplan Attributes - Object Layer Attributes #1, statisch_tragend: no
<Unnamed Element> | KG.- Grundriss | <Unnamed Material> 120 mm | 0117HWa0781540092 | 09ef5a79-666f-4d65-ae11-371ec0050284--781540092 | 0117Wa 0781540588 | Neubau | m³ |  | 09ef5a79-666f-4d65-ae11-371ec0050284--781540588 | Allplan Attributes - Object Layer Attributes #1, statisch_tragend: no
<Unnamed Element> | KG.- Grundriss | Stb-Wand 250 mm | 0117HWa0781540093 | 09ef5a79-666f-4d65-ae11-371ec0050284--781540093 | 0117Wa 0781540590 | Neubau | m³ |  | 09ef5a79-666f-4d65-ae11-371ec0050284--781540590 | Allplan Attributes - Object Layer Attributes #1, statisch_tragend: no
<Unnamed Element> | KG.- Grundriss | <Unnamed Material> 120 mm | 0117HWa0781540094 | 09ef5a79-666f-4d65-ae11-371ec0050284--781540094 | 0117Wa 0781540664 | Neubau | m³ |  | 09ef5a79-666f-4d65-ae11-371ec0050284--781540664 | Allplan Attributes - Object Layer Attributes #1, statisch_tragend: no
<Unnamed Element> | KG.- Grundriss | Stb-Wand 250 mm | 0117HWa0781540095 | 09ef5a79-666f-4d65-ae11-371ec0050284--781540095 | 0117Wa 0781540670 | Neubau | m³ |  | 09ef5a79-666f-4d65-ae11-371ec0050284--781540670 | Allplan Attributes - Object Layer Attributes #1, statisch_tragend: no
<Unnamed Element> | KG.- Grundriss | Stb-Wand 250 mm | 0117HWa0781540108 | 09ef5a79-666f-4d65-ae11-371ec0050284--781540108 | 0117Wa 0781540563 | Neubau | m³ |  | 09ef5a79-666f-4d65-ae11-371ec0050284--781540563 | Allplan Attributes - Object Layer Attributes #1, statisch_tragend: no; Object Layer Attributes #1, Material: Stb-Wand
<Unnamed Element> | KG.- Grundriss | Stb-Wand 250 mm | 0117HWa0781540109 | 09ef5a79-666f-4d65-ae11-371ec0050284--781540109 | 0117Wa 0781540559 | Neubau | m³ |  | 09ef5a79-666f-4d65-ae11-371ec0050284--781540559 | Allplan Attributes - Object Layer Attributes #1, statisch_tragend: no; Object Layer Attributes #1, Material: Stb-Wand
<Unnamed Element> | KG.- Grundriss | Stb-Wand 200 mm | 0117HWa0781540112 | 09ef5a79-666f-4d65-ae11-371ec0050284--781540112 | 0117Wa 0781540860 | Neubau | m³ |  | 09ef5a79-666f-4d65-ae11-371ec0050284--781540860 | Allplan Attributes - Object Layer Attributes #1, statisch_tragend: no
<Unnamed Element> | KG.- Grundriss | Stb-Wand 200 mm, <Unnamed Material> 60 mm | 0117HWa0781540114 | 09ef5a79-666f-4d65-ae11-371ec0050284--781540114 | 0117Wa 0781540654 | Neubau | m³ |  | 09ef5a79-666f-4d65-ae11-371ec0050284--781540654 | Allplan Attributes - Object Layer Attributes #1, statisch_tragend: no; Object Layer Attributes #2, Allright_Bauteil_ID: 0117Wa 0781540812; Object Layer Attributes #2, Umbaukategorie: Neubau; Object Layer Attributes #2, Einheit: m³; Object Layer Attributes #2, statisch_tragend: no; Object Layer Attributes #2, NOI_UUID: 09ef5a79-666f-4d65-ae11-371ec0050284--781540812
<Unnamed Element> | KG.- Grundriss | Stb-Wand 200 mm, <Unnamed Material> 60 mm | 0117HWa0781540116 | 09ef5a79-666f-4d65-ae11-371ec0050284--781540116 | 0117Wa 0781540656 | Neubau | m³ |  | 09ef5a79-666f-4d65-ae11-371ec0050284--781540656 | Allplan Attributes - Object Layer Attributes #1, statisch_tragend: no; Object Layer Attributes #1, Material: Stb-Wand; Object Layer Attributes #2, Allright_Bauteil_ID: 0117Wa 0781540862; Object Layer Attributes #2, Umbaukategorie: Neubau; Object Layer Attributes #2, Einheit: m³; Object Layer Attributes #2, statisch_tragend: no; Object Layer Attributes #2, NOI_UUID: 09ef5a79-666f-4d65-ae11-371ec0050284--781540862
<Unnamed Element> | KG.- Grundriss | KSPE Mauerwerk 115 mm | 0117HWa0781540119 | 09ef5a79-666f-4d65-ae11-371ec0050284--781540119 | 0117Wa 0781540537 | Neubau | m³ |  | 09ef5a79-666f-4d65-ae11-371ec0050284--781540537 | Allplan Attributes - Object Layer Attributes #1, statisch_tragend: no; Object Layer Attributes #1, Material: KSPE Mauerwerk
<Unnamed Element> | KG.- Grundriss | Stb-Wand 200 mm | 0117HWa0781540126 | 09ef5a79-666f-4d65-ae11-371ec0050284--781540126 | 0117Wa 0781541322 | Neubau | m³ |  | 09ef5a79-666f-4d65-ae11-371ec0050284--781541322 | Allplan Attributes - Object Layer Attributes #1, statisch_tragend: no
<Unnamed Element> | KG.- Grundriss | Stb-Wand 200 mm | 0117HWa0781540132 | 09ef5a79-666f-4d65-ae11-371ec0050284--781540132 | 0117Wa 0781541319 | Neubau | m³ |  | 09ef5a79-666f-4d65-ae11-371ec0050284--781541319 | Allplan Attributes - Object Layer Attributes #1, statisch_tragend: no
<Unnamed Element> | KG.- Grundriss | Stb-Wand 150 mm | 0117HWa0781540140 | 09ef5a79-666f-4d65-ae11-371ec0050284--781540140 | 0117Wa 0781540594 | Neubau | m³ |  | 09ef5a79-666f-4d65-ae11-371ec0050284--781540594
<Unnamed Element> | KG.- Grundriss | Stb-Wand 150 mm | 0117HWa0781540142 | 09ef5a79-666f-4d65-ae11-371ec0050284--781540142 | 0117Wa 0781541220 | Neubau | m³ |  | 09ef5a79-666f-4d65-ae11-371ec0050284--781541220
<Unnamed Element> | KG.- Grundriss | Stb-Wand 250 mm | 0117HWa0781540144 | 09ef5a79-666f-4d65-ae11-371ec0050284--781540144 | 0117Wa 0781541158 | Neubau | m³ |  | 09ef5a79-666f-4d65-ae11-371ec0050284--781541158 | Allplan Attributes - Object Layer Attributes #1, statisch_tragend: no; Object Layer Attributes #1, Material: Stb-Wand
<Unnamed Element> | KG.- Grundriss | Stb-Wand 240 mm | 0117HWa0781540148 | 09ef5a79-666f-4d65-ae11-371ec0050284--781540148 | 0117Wa 0781541335 | Neubau | m³ |  | 09ef5a79-666f-4d65-ae11-371ec0050284--781541335 | Allplan Attributes - Object Layer Attributes #1, statisch_tragend: no; Object Layer Attributes #1, Material: Stb-Wand
<Unnamed Element> | KG.- Grundriss | Stb-Wand 250 mm | 0117HWa0781540150 | 09ef5a79-666f-4d65-ae11-371ec0050284--781540150 | 0117Wa 0781540793 | Neubau | m³ |  | 09ef5a79-666f-4d65-ae11-371ec0050284--781540793 | Allplan Attributes - Object Layer Attributes #1, statisch_tragend: no; Object Layer Attributes #1, Material: Stb-Wand
<Unnamed Element> | KG.- Grundriss | Stb-Wand 260 mm | 0117HWa0781540156 | 09ef5a79-666f-4d65-ae11-371ec0050284--781540156 | 0117Wa 0781541136 | Neubau | m³ |  | 09ef5a79-666f-4d65-ae11-371ec0050284--781541136 | Allplan Attributes - Object Layer Attributes #1, statisch_tragend: no
<Unnamed Element> | KG.- Grundriss | Stb-Wand 200 mm | 0117HWa0781540164 | 09ef5a79-666f-4d65-ae11-371ec0050284--781540164 | 0117Wa 0781540601 |  | m² | Mauerarbeiten | 09ef5a79-666f-4d65-ae11-371ec0050284--781540601
<Unnamed Element> | KG.- Grundriss | Stb-Wand 200 mm | 0117HWa0781540165 | 09ef5a79-666f-4d65-ae11-371ec0050284--781540165 | 0117Wa 0781540599 |  | m² | Mauerarbeiten | 09ef5a79-666f-4d65-ae11-371ec0050284--781540599
<Unnamed Element> | KG.- Grundriss | Stb-Wand 360 mm, <Unnamed Material> 60 mm | 0117HWa0781540166 | 09ef5a79-666f-4d65-ae11-371ec0050284--781540166 | 0117Wa 0781540612 | Neubau | m³ |  | 09ef5a79-666f-4d65-ae11-371ec0050284--781540612 | Allplan Attributes - Object Layer Attributes #1, statisch_tragend: no; Object Layer Attributes #2, Allright_Bauteil_ID: 0117Wa 0781540610; Object Layer Attributes #2, Umbaukategorie: Neubau; Object Layer Attributes #2, Einheit: m³; Object Layer Attributes #2, statisch_tragend: no; Object Layer Attributes #2, NOI_UUID: 09ef5a79-666f-4d65-ae11-371ec0050284--781540610
<Unnamed Element> | KG.- Grundriss | Stb-Wand 175 mm | 0117HWa0781540170 | 09ef5a79-666f-4d65-ae11-371ec0050284--781540170 | 0117Wa 0781540584 | Neubau | m³ |  | 09ef5a79-666f-4d65-ae11-371ec0050284--781540584 | Allplan Attributes - Object Layer Attributes #1, statisch_tragend: no; Object Layer Attributes #1, Material: Stb-Wand
<Unnamed Element> | KG.- Grundriss | Stb-Wand 175 mm | 0117HWa0781540177 | 09ef5a79-666f-4d65-ae11-371ec0050284--781540177 | 0117Wa 0781541243 | Neubau | m³ |  | 09ef5a79-666f-4d65-ae11-371ec0050284--781541243 | Allplan Attributes - Object Layer Attributes #1, statisch_tragend: no; Object Layer Attributes #1, Material: Stb-Wand
<Unnamed Element> | KG.- Grundriss | Stb-Wand 200 mm | 0117HWa0781540180 | 09ef5a79-666f-4d65-ae11-371ec0050284--781540180 | 0117Wa 0781541229 | Neubau | m³ |  | 09ef5a79-666f-4d65-ae11-371ec0050284--781541229 | Allplan Attributes - Object Layer Attributes #1, statisch_tragend: no
<Unnamed Element> | KG.- Grundriss | KSPE Mauerwerk 175 mm | 0117HWa0781540183 | 09ef5a79-666f-4d65-ae11-371ec0050284--781540183 | 0117Wa 0781541118 | Neubau | m³ |  | 09ef5a79-666f-4d65-ae11-371ec0050284--781541118 | Allplan Attributes - Object Layer Attributes #1, statisch_tragend: no
<Unnamed Element> | KG.- Grundriss | Stb-Wand 200 mm | 0117HWa0781540188 | 09ef5a79-666f-4d65-ae11-371ec0050284--781540188 | 0117Wa 0781540597 | Neubau | m³ |  | 09ef5a79-666f-4d65-ae11-371ec0050284--781540597 | Allplan Attributes - Object Layer Attributes #1, statisch_tragend: no
<Unnamed Element> | KG.- Grundriss | KSPE Mauerwerk 115 mm | 0117HWa0781540190 | 09ef5a79-666f-4d65-ae11-371ec0050284--781540190 | 0117Wa 0781540567 | Neubau | m³ |  | 09ef5a79-666f-4d65-ae11-371ec0050284--781540567 | Allplan Attributes - Object Layer Attributes #1, statisch_tragend: no; Object Layer Attributes #1, Material: KSPE Mauerwerk
<Unnamed Element> | KG.- Grundriss | Stb-Wand 260 mm | 0117HWa0781540194 | 09ef5a79-666f-4d65-ae11-371ec0050284--781540194 | 0117Wa 0781541033 | Neubau | m³ |  | 09ef5a79-666f-4d65-ae11-371ec0050284--781541033 | Allplan Attributes - Object Layer Attributes #1, statisch_tragend: no
<Unnamed Element> | KG.- Grundriss | Stb-Wand 175 mm | 0117HWa0781540202 | 09ef5a79-666f-4d65-ae11-371ec0050284--781540202 | 0117Wa 0781540547 | Neubau | m³ |  | 09ef5a79-666f-4d65-ae11-371ec0050284--781540547 | Allplan Attributes - Object Layer Attributes #1, statisch_tragend: no; Object Layer Attributes #1, Material: Stb-Wand
<Unnamed Element> | KG.- Grundriss | Stb-Wand 240 mm | 0117HWa0781540207 | 09ef5a79-666f-4d65-ae11-371ec0050284--781540207 | 0117Wa 0781541326 | Neubau | m³ |  | 09ef5a79-666f-4d65-ae11-371ec0050284--781541326 | Allplan Attributes - Object Layer Attributes #1, statisch_tragend: no; Object Layer Attributes #1, Material: Stb-Wand
<Unnamed Element> | KG.- Grundriss | Stb-Wand 250 mm | 0117HWa0781540211 | 09ef5a79-666f-4d65-ae11-371ec0050284--781540211 | 0117Wa 0781541148 | Neubau | m³ |  | 09ef5a79-666f-4d65-ae11-371ec0050284--781541148 | Allplan Attributes - Object Layer Attributes #1, statisch_tragend: no
<Unnamed Element> | KG.- Grundriss | Stb-Wand 250 mm | 0117HWa0781540216 | 09ef5a79-666f-4d65-ae11-371ec0050284--781540216 | 0117Wa 0781541156 | Neubau | m³ |  | 09ef5a79-666f-4d65-ae11-371ec0050284--781541156 | Allplan Attributes - Object Layer Attributes #1, statisch_tragend: no
<Unnamed Element> | KG.- Grundriss | Stb-Wand 175 mm | 0117HWa0781540226 | 09ef5a79-666f-4d65-ae11-371ec0050284--781540226 | 0117Wa 0781540631 | Neubau | m³ |  | 09ef5a79-666f-4d65-ae11-371ec0050284--781540631 | Allplan Attributes - Object Layer Attributes #1, statisch_tragend: no
<Unnamed Element> | KG.- Grundriss | Stb-Wand 250 mm | 0117HWa0781540235 | 09ef5a79-666f-4d65-ae11-371ec0050284--781540235 | 0117Wa 0781540643 | Neubau | m³ |  | 09ef5a79-666f-4d65-ae11-371ec0050284--781540643 | Allplan Attributes - Object Layer Attributes #1, statisch_tragend: no
<Unnamed Element> | KG.- Grundriss | Stb-Wand 200 mm | 0117HWa0781540241 | 09ef5a79-666f-4d65-ae11-371ec0050284--781540241 | 0117Wa 0781540637 | Neubau | m³ |  | 09ef5a79-666f-4d65-ae11-371ec0050284--781540637 | Allplan Attributes - Object Layer Attributes #1, statisch_tragend: no
<Unnamed Element> | KG.- Grundriss | KSPE Mauerwerk 200 mm | 0117HWa0781540245 | 09ef5a79-666f-4d65-ae11-371ec0050284--781540245 | 0117Wa 0781540625 | Neubau | m² | Mauerarbeiten | 09ef5a79-666f-4d65-ae11-371ec0050284--781540625 | Allplan Attributes - Object Layer Attributes #1, Material: KSPE Mauerwerk
<Unnamed Element> | KG.- Grundriss | Stb-Wand 200 mm | 0117HWa0781540250 | 09ef5a79-666f-4d65-ae11-371ec0050284--781540250 | 0117Wa 0781540620 | Neubau | m³ |  | 09ef5a79-666f-4d65-ae11-371ec0050284--781540620 | Allplan Attributes - Object Layer Attributes #1, statisch_tragend: no
<Unnamed Element> | KG.- Grundriss | <Unnamed Material> 60 mm | 0117HWa0781540265 | 09ef5a79-666f-4d65-ae11-371ec0050284--781540265 | 0117Wa 0781541071 | Neubau | m³ |  | 09ef5a79-666f-4d65-ae11-371ec0050284--781541071 | Allplan Attributes - Object Layer Attributes #1, statisch_tragend: no
<Unnamed Element> | KG.- Grundriss | Stb-Wand 200 mm, <Unnamed Material> 60 mm | 0117HWa0781540267 | 09ef5a79-666f-4d65-ae11-371ec0050284--781540267 | 0117Wa 0781541075 | Neubau | m³ |  | 09ef5a79-666f-4d65-ae11-371ec0050284--781541075 | Allplan Attributes - Object Layer Attributes #1, statisch_tragend: no; Object Layer Attributes #2, Allright_Bauteil_ID: 0117Wa 0781541069; Object Layer Attributes #2, Umbaukategorie: Neubau; Object Layer Attributes #2, Einheit: m³; Object Layer Attributes #2, statisch_tragend: no; Object Layer Attributes #2, NOI_UUID: 09ef5a79-666f-4d65-ae11-371ec0050284--781541069
<Unnamed Element> | KG.- Grundriss | <Unnamed Material> 60 mm | 0117HWa0781540269 | 09ef5a79-666f-4d65-ae11-371ec0050284--781540269 | 0117Wa 0781541073 | Neubau | m³ |  | 09ef5a79-666f-4d65-ae11-371ec0050284--781541073 | Allplan Attributes - Object Layer Attributes #1, statisch_tragend: no
<Unnamed Element> | KG.- Grundriss | Stb-Wand 200 mm | 0117HWa0781540271 | 09ef5a79-666f-4d65-ae11-371ec0050284--781540271 | 0117Wa 0781540605 |  | m² | Mauerarbeiten | 09ef5a79-666f-4d65-ae11-371ec0050284--781540605
<Unnamed Element> | KG.- Grundriss | Stb-Wand 240 mm | 0117HWa0781540279 | 09ef5a79-666f-4d65-ae11-371ec0050284--781540279 | 0117Wa 0781540543 | Neubau | m³ |  | 09ef5a79-666f-4d65-ae11-371ec0050284--781540543 | Allplan Attributes - Object Layer Attributes #1, statisch_tragend: no
<Unnamed Element> | KG.- Grundriss | <Unnamed Material> 60 mm | 0117HWa0781540284 | 09ef5a79-666f-4d65-ae11-371ec0050284--781540284 | 0117Wa 0781540545 | Neubau | m³ |  | 09ef5a79-666f-4d65-ae11-371ec0050284--781540545 | Allplan Attributes - Object Layer Attributes #1, statisch_tragend: no
<Unnamed Element> | KG.- Grundriss | <Unnamed Material> 60 mm | 0117HWa0781540286 | 09ef5a79-666f-4d65-ae11-371ec0050284--781540286 | 0117Wa 0781540925 | Neubau | m³ |  | 09ef5a79-666f-4d65-ae11-371ec0050284--781540925 | Allplan Attributes - Object Layer Attributes #1, statisch_tragend: no
<Unnamed Element> | KG.- Grundriss | Stb-Wand 250 mm | 0117HWa0781540288 | 09ef5a79-666f-4d65-ae11-371ec0050284--781540288 | 0117Wa 0781541218 | Neubau | m³ |  | 09ef5a79-666f-4d65-ae11-371ec0050284--781541218 | Allplan Attributes - Object Layer Attributes #1, statisch_tragend: no
<Unnamed Element> | KG.- Grundriss | Stb-Wand 200 mm | 0117HWa0781540294 | 09ef5a79-666f-4d65-ae11-371ec0050284--781540294 | 0117Wa 0781540580 | Neubau | m³ |  | 09ef5a79-666f-4d65-ae11-371ec0050284--781540580 | Allplan Attributes - Object Layer Attributes #1, statisch_tragend: no
<Unnamed Element> | KG.- Grundriss | KSPE Mauerwerk 175 mm | 0117HWa0781540300 | 09ef5a79-666f-4d65-ae11-371ec0050284--781540300 | 0117Wa 0781540574 | Neubau | m³ |  | 09ef5a79-666f-4d65-ae11-371ec0050284--781540574 | Allplan Attributes - Object Layer Attributes #1, statisch_tragend: no; Object Layer Attributes #1, Material: KSPE Mauerwerk
<Unnamed Element> | KG.- Grundriss | KSPE Mauerwerk 115 mm | 0117HWa0781540307 | 09ef5a79-666f-4d65-ae11-371ec0050284--781540307 | 0117Wa 0781540570 | Neubau | m³ |  | 09ef5a79-666f-4d65-ae11-371ec0050284--781540570 | Allplan Attributes - Object Layer Attributes #1, statisch_tragend: no; Object Layer Attributes #1, Material: KSPE Mauerwerk
<Unnamed Element> | KG.- Grundriss | Stb-Wand 200 mm | 0117HWa0781540311 | 09ef5a79-666f-4d65-ae11-371ec0050284--781540311 | 0117Wa 0781540998 | Neubau | m³ |  | 09ef5a79-666f-4d65-ae11-371ec0050284--781540998 | Allplan Attributes - Object Layer Attributes #1, statisch_tragend: no
<Unnamed Element> | KG.- Grundriss | Stb-Wand 240 mm | 0117HWa0781540314 | 09ef5a79-666f-4d65-ae11-371ec0050284--781540314 | 0117Wa 0781541001 | Neubau | m³ |  | 09ef5a79-666f-4d65-ae11-371ec0050284--781541001 | Allplan Attributes - Object Layer Attributes #1, statisch_tragend: no; Object Layer Attributes #1, Material: Stb-Wand
<Unnamed Element> | KG.- Grundriss | Stb-Wand 250 mm | 0117HWa0781540316 | 09ef5a79-666f-4d65-ae11-371ec0050284--781540316 | 0117Wa 0781540995 | Neubau | m³ |  | 09ef5a79-666f-4d65-ae11-371ec0050284--781540995 | Allplan Attributes - Object Layer Attributes #1, statisch_tragend: no
<Unnamed Element> | KG.- Grundriss | Stb-Wand 240 mm | 0117HWa0781540318 | 09ef5a79-666f-4d65-ae11-371ec0050284--781540318 | 0117Wa 0781541353 | Neubau | m³ |  | 09ef5a79-666f-4d65-ae11-371ec0050284--781541353 | Allplan Attributes - Object Layer Attributes #1, statisch_tragend: no
<Unnamed Element> | KG.- Grundriss | Stb-Wand 200 mm | 0117HWa0781540326 | 09ef5a79-666f-4d65-ae11-371ec0050284--781540326 | 0117Wa 0781540552 | Neubau | m³ |  | 09ef5a79-666f-4d65-ae11-371ec0050284--781540552 | Allplan Attributes - Object Layer Attributes #1, statisch_tragend: no
<Unnamed Element> | KG.- Grundriss | Stb-Wand 200 mm, <Unnamed Material> 60 mm | 0117HWa0781540333 | 09ef5a79-666f-4d65-ae11-371ec0050284--781540333 | 0117Wa 0781540921 | Neubau | m³ |  | 09ef5a79-666f-4d65-ae11-371ec0050284--781540921 | Allplan Attributes - Object Layer Attributes #1, statisch_tragend: no; Object Layer Attributes #2, Allright_Bauteil_ID: 0117Wa 0781541028; Object Layer Attributes #2, Umbaukategorie: Neubau; Object Layer Attributes #2, Einheit: m³; Object Layer Attributes #2, statisch_tragend: no; Object Layer Attributes #2, NOI_UUID: 09ef5a79-666f-4d65-ae11-371ec0050284--781541028
<Unnamed Element> | KG.- Grundriss | Stb-Wand 200 mm, <Unnamed Material> 60 mm | 0117HWa0781540335 | 09ef5a79-666f-4d65-ae11-371ec0050284--781540335 | 0117Wa 0781540914 | Neubau | m³ |  | 09ef5a79-666f-4d65-ae11-371ec0050284--781540914 | Allplan Attributes - Object Layer Attributes #1, statisch_tragend: no; Object Layer Attributes #2, Allright_Bauteil_ID: 0117Wa 0781540919; Object Layer Attributes #2, Umbaukategorie: Neubau; Object Layer Attributes #2, Einheit: m³; Object Layer Attributes #2, statisch_tragend: no; Object Layer Attributes #2, NOI_UUID: 09ef5a79-666f-4d65-ae11-371ec0050284--781540919
<Unnamed Element> | KG.- Grundriss | Stb-Wand 250 mm | 0117HWa0781540345 | 09ef5a79-666f-4d65-ae11-371ec0050284--781540345 | 0117Wa 0781541316 | Neubau | m³ |  | 09ef5a79-666f-4d65-ae11-371ec0050284--781541316 | Allplan Attributes - Object Layer Attributes #1, statisch_tragend: no
<Unnamed Element> | KG.- Grundriss | Stb-Wand 250 mm | 0117HWa0781540350 | 09ef5a79-666f-4d65-ae11-371ec0050284--781540350 | 0117Wa 0781541196 | Neubau | m³ |  | 09ef5a79-666f-4d65-ae11-371ec0050284--781541196 | Allplan Attributes - Object Layer Attributes #1, statisch_tragend: no
<Unnamed Element> | KG.- Grundriss | KSPE Mauerwerk 115 mm | 0117HWa0781540743 | 09ef5a79-666f-4d65-ae11-371ec0050284--781540743 | 0117Wa 0781541332 | Neubau | m³ |  | 09ef5a79-666f-4d65-ae11-371ec0050284--781541332 | Allplan Attributes - Object Layer Attributes #1, statisch_tragend: no; Object Layer Attributes #1, Material: KSPE Mauerwerk
<Unnamed Element> | KG.- Grundriss | Stb-Wand 240 mm | 0117HWa0781540755 | 09ef5a79-666f-4d65-ae11-371ec0050284--781540755 | 0117Wa 0781540991 | Neubau | m³ |  | 09ef5a79-666f-4d65-ae11-371ec0050284--781540991 | Allplan Attributes - Object Layer Attributes #1, statisch_tragend: no; Object Layer Attributes #1, Material: Stb-Wand
<Unnamed Element> | KG.- Grundriss | <Unnamed Material> 120.025 mm | 0117HWa0781540765 | 09ef5a79-666f-4d65-ae11-371ec0050284--781540765 | 0117Wa 0781540773 | Neubau | m³ |  | 09ef5a79-666f-4d65-ae11-371ec0050284--781540773 | Allplan Attributes - Object Layer Attributes #1, statisch_tragend: no
<Unnamed Element> | KG.- Grundriss | <Unnamed Material> 120 mm | 0117HWa0781540770 | 09ef5a79-666f-4d65-ae11-371ec0050284--781540770 | 0117Wa 0781541183 | Neubau | m³ |  | 09ef5a79-666f-4d65-ae11-371ec0050284--781541183 | Allplan Attributes - Object Layer Attributes #1, statisch_tragend: no
<Unnamed Element> | KG.- Grundriss | <Unnamed Material> 120 mm | 0117HWa0781540783 | 09ef5a79-666f-4d65-ae11-371ec0050284--781540783 | 0117Wa 0781541198 | Neubau | m³ |  | 09ef5a79-666f-4d65-ae11-371ec0050284--781541198 | Allplan Attributes - Object Layer Attributes #1, statisch_tragend: no
<Unnamed Element> | KG.- Grundriss | <Unnamed Material> 120 mm | 0117HWa0781540785 | 09ef5a79-666f-4d65-ae11-371ec0050284--781540785 | 0117Wa 0781540788 | Neubau | m³ |  | 09ef5a79-666f-4d65-ae11-371ec0050284--781540788 | Allplan Attributes - Object Layer Attributes #1, statisch_tragend: no
<Unnamed Element> | KG.- Grundriss | Stb-Wand 200 mm, <Unnamed Material> 60 mm | 0117HWa0781540794 | 09ef5a79-666f-4d65-ae11-371ec0050284--781540794 | 0117Wa 0781540835 | Neubau | m³ |  | 09ef5a79-666f-4d65-ae11-371ec0050284--781540835 | Allplan Attributes - Object Layer Attributes #2, Allright_Bauteil_ID: 0117Wa 0781540810; Object Layer Attributes #2, Umbaukategorie: Neubau; Object Layer Attributes #2, Einheit: m³; Object Layer Attributes #2, statisch_tragend: no; Object Layer Attributes #2, NOI_UUID: 09ef5a79-666f-4d65-ae11-371ec0050284--781540810
<Unnamed Element> | KG.- Grundriss | Stb-Wand 200 mm | 0117HWa0781540816 | 09ef5a79-666f-4d65-ae11-371ec0050284--781540816 | 0117Wa 0781540825 |  | m² | Mauerarbeiten | 09ef5a79-666f-4d65-ae11-371ec0050284--781540825
<Unnamed Element> | KG.- Grundriss | Stb-Wand 100 mm | 0117HWa0781540818 | 09ef5a79-666f-4d65-ae11-371ec0050284--781540818 | 0117Wa 0781540829 |  | m² | Mauerarbeiten | 09ef5a79-666f-4d65-ae11-371ec0050284--781540829
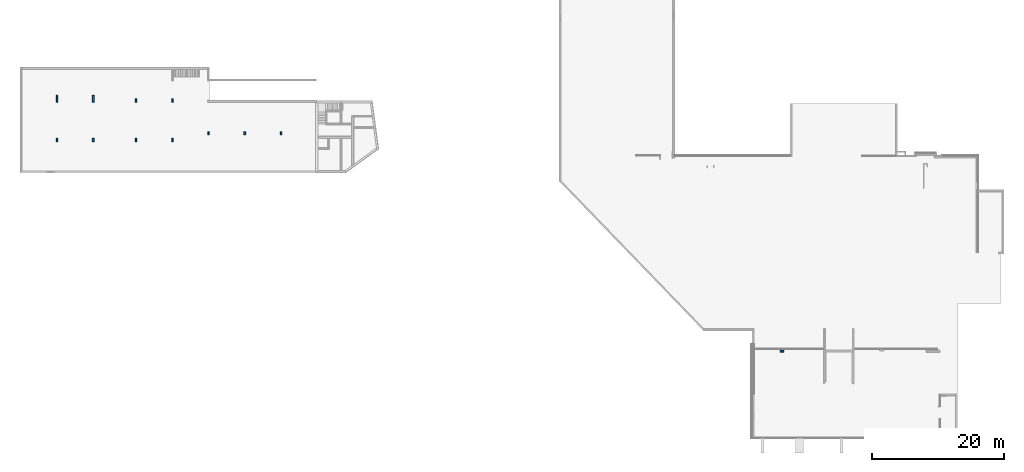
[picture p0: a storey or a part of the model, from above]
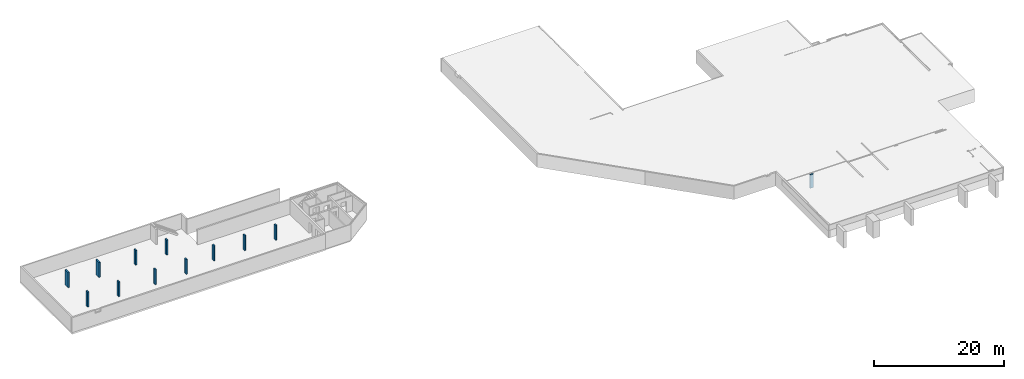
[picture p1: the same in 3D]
Properties of the parts of a building model (IFC2X3), part 3 of 4

# IfcWallStandardCase (383)
Name | In | Material | Allright_Bauteil_ID | NOI_UUID | Object Layer Attributes #1, Allright_Bauteil_ID | Object Layer Attributes #1, Umbaukategorie | Object Layer Attributes #1, Einheit | Object Layer Attributes #1, Gewerk | Object Layer Attributes #1, NOI_UUID
<Unnamed Element> | KG.- Grundriss | Stb-Wand 200 mm | 0117HWa0781540843 | 09ef5a79-666f-4d65-ae11-371ec0050284--781540843 | 0117Wa 0781540858 | Neubau | m³ |  | 09ef5a79-666f-4d65-ae11-371ec0050284--781540858 | Allplan Attributes - Object Layer Attributes #1, statisch_tragend: no
<Unnamed Element> | KG.- Grundriss | Stb-Wand 200 mm, <Unnamed Material> 60 mm | 0117HWa0781540876 | 09ef5a79-666f-4d65-ae11-371ec0050284--781540876 | 0117Wa 0781540909 | Neubau | m³ |  | 09ef5a79-666f-4d65-ae11-371ec0050284--781540909 | Allplan Attributes - Object Layer Attributes #1, statisch_tragend: no; Object Layer Attributes #2, Allright_Bauteil_ID: 0117Wa 0781540907; Object Layer Attributes #2, Umbaukategorie: Neubau; Object Layer Attributes #2, Einheit: m³; Object Layer Attributes #2, statisch_tragend: no; Object Layer Attributes #2, NOI_UUID: 09ef5a79-666f-4d65-ae11-371ec0050284--781540907
<Unnamed Element> | KG.- Grundriss | Stb-Wand 100 mm | 0117HWa0781540877 | 09ef5a79-666f-4d65-ae11-371ec0050284--781540877 | 0117Wa 0781540901 |  | m² | Mauerarbeiten | 09ef5a79-666f-4d65-ae11-371ec0050284--781540901
<Unnamed Element> | KG.- Grundriss | Stb-Wand 200 mm, <Unnamed Material> 60 mm | 0117HWa0781540880 | 09ef5a79-666f-4d65-ae11-371ec0050284--781540880 | 0117Wa 0781540905 | Neubau | m³ |  | 09ef5a79-666f-4d65-ae11-371ec0050284--781540905 | Allplan Attributes - Object Layer Attributes #1, statisch_tragend: no; Object Layer Attributes #2, Allright_Bauteil_ID: 0117Wa 0781540898; Object Layer Attributes #2, Umbaukategorie: Neubau; Object Layer Attributes #2, Einheit: m³; Object Layer Attributes #2, statisch_tragend: no; Object Layer Attributes #2, NOI_UUID: 09ef5a79-666f-4d65-ae11-371ec0050284--781540898
<Unnamed Element> | KG.- Grundriss | Stb-Wand 250 mm | 0117HWa0781540931 | 09ef5a79-666f-4d65-ae11-371ec0050284--781540931 | 0117Wa 0781541234 | Neubau | m³ |  | 09ef5a79-666f-4d65-ae11-371ec0050284--781541234 | Allplan Attributes - Object Layer Attributes #1, statisch_tragend: no
<Unnamed Element> | KG.- Grundriss | Stb-Wand 250 mm | 0117HWa0781540943 | 09ef5a79-666f-4d65-ae11-371ec0050284--781540943 | 0117Wa 0781540962 | Neubau | m³ |  | 09ef5a79-666f-4d65-ae11-371ec0050284--781540962 | Allplan Attributes - Object Layer Attributes #1, statisch_tragend: no
<Unnamed Element> | KG.- Grundriss | Stb-Wand 250 mm | 0117HWa0781540965 | 09ef5a79-666f-4d65-ae11-371ec0050284--781540965 | 0117Wa 0781541190 | Neubau | m³ |  | 09ef5a79-666f-4d65-ae11-371ec0050284--781541190 | Allplan Attributes - Object Layer Attributes #1, statisch_tragend: no; Object Layer Attributes #1, Material: Stb-Wand
<Unnamed Element> | KG.- Grundriss | Stb-Wand 260 mm | 0117HWa0781541006 | 09ef5a79-666f-4d65-ae11-371ec0050284--781541006 | 0117Wa 0781541024 | Neubau | m³ |  | 09ef5a79-666f-4d65-ae11-371ec0050284--781541024 | Allplan Attributes - Object Layer Attributes #1, statisch_tragend: no
<Unnamed Element> | KG.- Grundriss | Stb-Wand 200 mm, <Unnamed Material> 60 mm | 0117HWa0781541034 | 09ef5a79-666f-4d65-ae11-371ec0050284--781541034 | 0117Wa 0781541083 | Neubau | m³ |  | 09ef5a79-666f-4d65-ae11-371ec0050284--781541083 | Allplan Attributes - Object Layer Attributes #1, statisch_tragend: no; Object Layer Attributes #2, Allright_Bauteil_ID: 0117Wa 0781541079; Object Layer Attributes #2, Umbaukategorie: Neubau; Object Layer Attributes #2, Einheit: m³; Object Layer Attributes #2, statisch_tragend: no; Object Layer Attributes #2, NOI_UUID: 09ef5a79-666f-4d65-ae11-371ec0050284--781541079
<Unnamed Element> | KG.- Grundriss | <Unnamed Material> 60 mm | 0117HWa0781541054 | 09ef5a79-666f-4d65-ae11-371ec0050284--781541054 | 0117Wa 0781541085 | Neubau | m³ |  | 09ef5a79-666f-4d65-ae11-371ec0050284--781541085 | Allplan Attributes - Object Layer Attributes #1, statisch_tragend: no
<Unnamed Element> | KG.- Grundriss | <Unnamed Material> 120 mm | 0117HWa0781541056 | 09ef5a79-666f-4d65-ae11-371ec0050284--781541056 | 0117Wa 0781541251 | Neubau | m³ |  | 09ef5a79-666f-4d65-ae11-371ec0050284--781541251 | Allplan Attributes - Object Layer Attributes #1, statisch_tragend: no
<Unnamed Element> | KG.- Grundriss | Stb-Wand 250 mm | 0117HWa0781541058 | 09ef5a79-666f-4d65-ae11-371ec0050284--781541058 | 0117Wa 0781541247 | Neubau | m³ |  | 09ef5a79-666f-4d65-ae11-371ec0050284--781541247 | Allplan Attributes - Object Layer Attributes #1, statisch_tragend: no
<Unnamed Element> | KG.- Grundriss | KSPE Mauerwerk 175 mm | 0117HWa0781541087 | 09ef5a79-666f-4d65-ae11-371ec0050284--781541087 | 0117Wa 0781541109 | Neubau | m³ |  | 09ef5a79-666f-4d65-ae11-371ec0050284--781541109
<Unnamed Element> | KG.- Grundriss | KSPE Mauerwerk 175 mm | 0117HWa0781541090 | 09ef5a79-666f-4d65-ae11-371ec0050284--781541090 | 0117Wa 0781541114 | Neubau | m³ |  | 09ef5a79-666f-4d65-ae11-371ec0050284--781541114 | Allplan Attributes - Object Layer Attributes #1, statisch_tragend: no
<Unnamed Element> | KG.- Grundriss | KSPE Mauerwerk 115 mm | 0117HWa0781541121 | 09ef5a79-666f-4d65-ae11-371ec0050284--781541121 | 0117Wa 0781541144 | Neubau | m³ |  | 09ef5a79-666f-4d65-ae11-371ec0050284--781541144 | Allplan Attributes - Object Layer Attributes #1, statisch_tragend: no; Object Layer Attributes #1, Material: KSPE Mauerwerk
<Unnamed Element> | KG.- Grundriss | Stb-Wand 240 mm | 0117HWa0781541159 | 09ef5a79-666f-4d65-ae11-371ec0050284--781541159 | 0117Wa 0781541313 | Neubau | m³ |  | 09ef5a79-666f-4d65-ae11-371ec0050284--781541313 | Allplan Attributes - Object Layer Attributes #1, statisch_tragend: no
<Unnamed Element> | KG.- Grundriss | Stb-Wand 250 mm | 0117HWa0781541199 | 09ef5a79-666f-4d65-ae11-371ec0050284--781541199 | 0117Wa 0781541214 | Neubau | m³ |  | 09ef5a79-666f-4d65-ae11-371ec0050284--781541214 | Allplan Attributes - Object Layer Attributes #1, statisch_tragend: no
<Unnamed Element> | EG.- Grundriss | Poroton 365 mm | 0200HWa0784434059 | 9eee6ca3-aa3f-4e17-bd40-2a040d5346dc--784434059 | 0200Wa 0784434147 | Neubau | m³ | Mauerarbeiten | 9eee6ca3-aa3f-4e17-bd40-2a040d5346dc--784434147
<Unnamed Element> | EG.- Grundriss | Poroton 365 mm | 0200HWa0784434958 | 9eee6ca3-aa3f-4e17-bd40-2a040d5346dc--784434958 | 0200Wa 0784434959 | Neubau | m³ | Mauerarbeiten | 9eee6ca3-aa3f-4e17-bd40-2a040d5346dc--784434959
<Unnamed Element> | EG.- Grundriss | Poroton 365 mm | 0200HWa0784434963 | 9eee6ca3-aa3f-4e17-bd40-2a040d5346dc--784434963 | 0200Wa 0784434964 | Neubau | m³ | Mauerarbeiten | 9eee6ca3-aa3f-4e17-bd40-2a040d5346dc--784434964
<Unnamed Element> | EG.- Grundriss | Poroton 365 mm | 0200HWa0784435033 | 9eee6ca3-aa3f-4e17-bd40-2a040d5346dc--784435033 | 0200Wa 0784435062 | Neubau | m³ | Mauerarbeiten | 9eee6ca3-aa3f-4e17-bd40-2a040d5346dc--784435062
<Unnamed Element> | EG.- Grundriss | Poroton 365 mm | 0200HWa0784435036 | 9eee6ca3-aa3f-4e17-bd40-2a040d5346dc--784435036 | 0200Wa 0784435061 | Neubau | m³ | Mauerarbeiten | 9eee6ca3-aa3f-4e17-bd40-2a040d5346dc--784435061
<Unnamed Element> | EG.- Grundriss | Poroton 365 mm | 0200HWa0784435125 | 9eee6ca3-aa3f-4e17-bd40-2a040d5346dc--784435125 | 0200Wa 0784435126 | Neubau | m³ | Mauerarbeiten | 9eee6ca3-aa3f-4e17-bd40-2a040d5346dc--784435126
<Unnamed Element> | EG.- Grundriss | Poroton 365 mm | 0200HWa0784435130 | 9eee6ca3-aa3f-4e17-bd40-2a040d5346dc--784435130 | 0200Wa 0784435131 | Neubau | m³ | Mauerarbeiten | 9eee6ca3-aa3f-4e17-bd40-2a040d5346dc--784435131
<Unnamed Element> | EG.- Grundriss | Poroton 365 mm | 0200HWa0784435171 | 9eee6ca3-aa3f-4e17-bd40-2a040d5346dc--784435171 | 0200Wa 0784435172 | Neubau | m³ | Mauerarbeiten | 9eee6ca3-aa3f-4e17-bd40-2a040d5346dc--784435172
<Unnamed Element> | EG.- Grundriss | Poroton 365 mm | 0200HWa0784435047 | 9eee6ca3-aa3f-4e17-bd40-2a040d5346dc--784435047 | 0200Wa 0784435063 | Neubau | m³ | Mauerarbeiten | 9eee6ca3-aa3f-4e17-bd40-2a040d5346dc--784435063
<Unnamed Element> | EG.- Grundriss | Hlz 150 mm | 0200HWa0784435333 | 9eee6ca3-aa3f-4e17-bd40-2a040d5346dc--784435333 | 0200Wa 0784435334 | Neubau | m³ | Mauerarbeiten | 9eee6ca3-aa3f-4e17-bd40-2a040d5346dc--784435334
<Unnamed Element> | EG.- Grundriss | Poroton 365 mm | 0200HWa0784434053 | 9eee6ca3-aa3f-4e17-bd40-2a040d5346dc--784434053 | 0200Wa 0784434143 | Neubau | m³ | Mauerarbeiten | 9eee6ca3-aa3f-4e17-bd40-2a040d5346dc--784434143
<Unnamed Element> | EG.- Grundriss | Hlz 150 mm | 0200HWa0784435328 | 9eee6ca3-aa3f-4e17-bd40-2a040d5346dc--784435328 | 0200Wa 0784435329 | Neubau | m³ | Mauerarbeiten | 9eee6ca3-aa3f-4e17-bd40-2a040d5346dc--784435329
<Unnamed Element> | EG.- Grundriss | Poroton 365 mm | 0200HWa0784435182 | 9eee6ca3-aa3f-4e17-bd40-2a040d5346dc--784435182 | 0200Wa 0784435183 | Neubau | m³ | Mauerarbeiten | 9eee6ca3-aa3f-4e17-bd40-2a040d5346dc--784435183
<Unnamed Element> | EG.- Grundriss | Poroton 365 mm | 0200HWa0784435194 | 9eee6ca3-aa3f-4e17-bd40-2a040d5346dc--784435194 | 0200Wa 0784435195 | Neubau | m³ | Mauerarbeiten | 9eee6ca3-aa3f-4e17-bd40-2a040d5346dc--784435195
<Unnamed Element> | EG.- Grundriss | Poroton 365 mm | 0200HWa0784435211 | 9eee6ca3-aa3f-4e17-bd40-2a040d5346dc--784435211 | 0200Wa 0784435212 | Neubau | m³ | Mauerarbeiten | 9eee6ca3-aa3f-4e17-bd40-2a040d5346dc--784435212
<Unnamed Element> | EG.- Grundriss | Poroton 365 mm | 0200HWa0784435257 | 9eee6ca3-aa3f-4e17-bd40-2a040d5346dc--784435257 | 0200Wa 0784435260 | Neubau | m³ | Mauerarbeiten | 9eee6ca3-aa3f-4e17-bd40-2a040d5346dc--784435260
<Unnamed Element> | EG.- Grundriss | Stb-Wand 200 mm | 0200HWa0784435523 | 9eee6ca3-aa3f-4e17-bd40-2a040d5346dc--784435523 | 0200Wa 0784435572 | Neubau | m³ | Betonarbeiten | 9eee6ca3-aa3f-4e17-bd40-2a040d5346dc--784435572 | Allplan Attributes - Object Layer Attributes #1, statisch_tragend: no
<Unnamed Element> | EG.- Grundriss | Stb-Wand 200 mm | 0200HWa0784435524 | 9eee6ca3-aa3f-4e17-bd40-2a040d5346dc--784435524 | 0200Wa 0784435557 | Neubau | m³ | Betonarbeiten | 9eee6ca3-aa3f-4e17-bd40-2a040d5346dc--784435557 | Allplan Attributes - Object Layer Attributes #1, statisch_tragend: no
<Unnamed Element> | EG.- Grundriss | Stb-Wand 200 mm | 0200HWa0784435526 | 9eee6ca3-aa3f-4e17-bd40-2a040d5346dc--784435526 | 0200Wa 0784435563 | Neubau | m³ | Betonarbeiten | 9eee6ca3-aa3f-4e17-bd40-2a040d5346dc--784435563 | Allplan Attributes - Object Layer Attributes #1, statisch_tragend: no
<Unnamed Element> | EG.- Grundriss | Hlz 250 mm | 0200HWa0784435532 | 9eee6ca3-aa3f-4e17-bd40-2a040d5346dc--784435532 | 0200Wa 0784435567 | Neubau | m³ | Mauerarbeiten | 9eee6ca3-aa3f-4e17-bd40-2a040d5346dc--784435567 | Allplan Attributes - Object Layer Attributes #1, statisch_tragend: no
<Unnamed Element> | EG.- Grundriss | Hlz 250 mm | 0200HWa0784435536 | 9eee6ca3-aa3f-4e17-bd40-2a040d5346dc--784435536 | 0200Wa 0784435570 | Neubau | m³ | Mauerarbeiten | 9eee6ca3-aa3f-4e17-bd40-2a040d5346dc--784435570 | Allplan Attributes - Object Layer Attributes #1, statisch_tragend: no
<Unnamed Element> | EG.- Grundriss | Stb-Wand 200 mm | 0200HWa0784435529 | 9eee6ca3-aa3f-4e17-bd40-2a040d5346dc--784435529 | 0200Wa 0784435561 | Neubau | m³ | Betonarbeiten | 9eee6ca3-aa3f-4e17-bd40-2a040d5346dc--784435561 | Allplan Attributes - Object Layer Attributes #1, statisch_tragend: no
<Unnamed Element> | EG.- Grundriss | Poroton 365 mm | 0200HWa0784435234 | 9eee6ca3-aa3f-4e17-bd40-2a040d5346dc--784435234 | 0200Wa 0784435235 | Neubau | m³ | Mauerarbeiten | 9eee6ca3-aa3f-4e17-bd40-2a040d5346dc--784435235
<Unnamed Element> | EG.- Grundriss | Poroton 365 mm | 0200HWa0784435289 | 9eee6ca3-aa3f-4e17-bd40-2a040d5346dc--784435289 | 0200Wa 0784435292 | Neubau | m³ | Mauerarbeiten | 9eee6ca3-aa3f-4e17-bd40-2a040d5346dc--784435292
<Unnamed Element> | EG.- Grundriss | Poroton 365 mm | 0200HWa0784435222 | 9eee6ca3-aa3f-4e17-bd40-2a040d5346dc--784435222 | 0200Wa 0784435223 | Neubau | m³ | Mauerarbeiten | 9eee6ca3-aa3f-4e17-bd40-2a040d5346dc--784435223
<Unnamed Element> | EG.- Grundriss | Hlz 115 mm | 0200HWa0784435735 | 9eee6ca3-aa3f-4e17-bd40-2a040d5346dc--784435735 | 0200Wa 0784435736 | Neubau | m³ | Mauerarbeiten | 9eee6ca3-aa3f-4e17-bd40-2a040d5346dc--784435736
<Unnamed Element> | EG.- Grundriss | Hlz 115 mm | 0200HWa0784435746 | 9eee6ca3-aa3f-4e17-bd40-2a040d5346dc--784435746 | 0200Wa 0784435747 | Neubau | m³ | Mauerarbeiten | 9eee6ca3-aa3f-4e17-bd40-2a040d5346dc--784435747
<Unnamed Element> | EG.- Grundriss | Hlz 115 mm | 0200HWa0784435753 | 9eee6ca3-aa3f-4e17-bd40-2a040d5346dc--784435753 | 0200Wa 0784435754 | Neubau | m³ | Mauerarbeiten | 9eee6ca3-aa3f-4e17-bd40-2a040d5346dc--784435754
<Unnamed Element> | EG.- Grundriss | Hlz 115 mm | 0200HWa0784435768 | 9eee6ca3-aa3f-4e17-bd40-2a040d5346dc--784435768 | 0200Wa 0784435769 | Neubau | m³ | Mauerarbeiten | 9eee6ca3-aa3f-4e17-bd40-2a040d5346dc--784435769
<Unnamed Element> | EG.- Grundriss | Hlz 115 mm | 0200HWa0784435775 | 9eee6ca3-aa3f-4e17-bd40-2a040d5346dc--784435775 | 0200Wa 0784435776 | Neubau | m³ | Mauerarbeiten | 9eee6ca3-aa3f-4e17-bd40-2a040d5346dc--784435776
<Unnamed Element> | EG.- Grundriss | Hlz 115 mm | 0200HWa0784435786 | 9eee6ca3-aa3f-4e17-bd40-2a040d5346dc--784435786 | 0200Wa 0784435787 | Neubau | m³ | Mauerarbeiten | 9eee6ca3-aa3f-4e17-bd40-2a040d5346dc--784435787
<Unnamed Element> | EG.- Grundriss | Hlz 115 mm | 0200HWa0784435811 | 9eee6ca3-aa3f-4e17-bd40-2a040d5346dc--784435811 | 0200Wa 0784435812 | Neubau | m³ | Mauerarbeiten | 9eee6ca3-aa3f-4e17-bd40-2a040d5346dc--784435812
<Unnamed Element> | EG.- Grundriss | Hlz 115 mm | 0200HWa0784435830 | 9eee6ca3-aa3f-4e17-bd40-2a040d5346dc--784435830 | 0200Wa 0784435831 | Neubau | m³ | Mauerarbeiten | 9eee6ca3-aa3f-4e17-bd40-2a040d5346dc--784435831
<Unnamed Element> | EG.- Grundriss | Hlz 115 mm | 0200HWa0784435842 | 9eee6ca3-aa3f-4e17-bd40-2a040d5346dc--784435842 | 0200Wa 0784435843 | Neubau | m³ | Mauerarbeiten | 9eee6ca3-aa3f-4e17-bd40-2a040d5346dc--784435843
<Unnamed Element> | EG.- Grundriss | Hlz 115 mm | 0200HWa0784435849 | 9eee6ca3-aa3f-4e17-bd40-2a040d5346dc--784435849 | 0200Wa 0784435850 | Neubau | m³ | Mauerarbeiten | 9eee6ca3-aa3f-4e17-bd40-2a040d5346dc--784435850
<Unnamed Element> | EG.- Grundriss | Hlz 115 mm | 0200HWa0784435856 | 9eee6ca3-aa3f-4e17-bd40-2a040d5346dc--784435856 | 0200Wa 0784435857 | Neubau | m³ | Mauerarbeiten | 9eee6ca3-aa3f-4e17-bd40-2a040d5346dc--784435857
<Unnamed Element> | EG.- Grundriss | Hlz 115 mm | 0200HWa0784435868 | 9eee6ca3-aa3f-4e17-bd40-2a040d5346dc--784435868 | 0200Wa 0784435869 | Neubau | m³ | Mauerarbeiten | 9eee6ca3-aa3f-4e17-bd40-2a040d5346dc--784435869
<Unnamed Element> | EG.- Grundriss | Hlz 115 mm | 0200HWa0784435880 | 9eee6ca3-aa3f-4e17-bd40-2a040d5346dc--784435880 | 0200Wa 0784435881 | Neubau | m³ | Mauerarbeiten | 9eee6ca3-aa3f-4e17-bd40-2a040d5346dc--784435881
<Unnamed Element> | EG.- Grundriss | Hlz 115 mm | 0200HWa0784435910 | 9eee6ca3-aa3f-4e17-bd40-2a040d5346dc--784435910 | 0200Wa 0784435911 | Neubau | m³ | Mauerarbeiten | 9eee6ca3-aa3f-4e17-bd40-2a040d5346dc--784435911
<Unnamed Element> | EG.- Grundriss | Hlz 115 mm | 0200HWa0784435956 | 9eee6ca3-aa3f-4e17-bd40-2a040d5346dc--784435956 | 0200Wa 0784435957 | Neubau | m³ | Mauerarbeiten | 9eee6ca3-aa3f-4e17-bd40-2a040d5346dc--784435957
<Unnamed Element> | EG.- Grundriss | Hlz 115 mm | 0200HWa0784435920 | 9eee6ca3-aa3f-4e17-bd40-2a040d5346dc--784435920 | 0200Wa 0784435921 | Neubau | m³ | Mauerarbeiten | 9eee6ca3-aa3f-4e17-bd40-2a040d5346dc--784435921
<Unnamed Element> | EG.- Grundriss | Hlz 115 mm | 0200HWa0784435933 | 9eee6ca3-aa3f-4e17-bd40-2a040d5346dc--784435933 | 0200Wa 0784435934 | Neubau | m³ | Mauerarbeiten | 9eee6ca3-aa3f-4e17-bd40-2a040d5346dc--784435934
<Unnamed Element> | EG.- Grundriss | Hlz 115 mm | 0200HWa0784435944 | 9eee6ca3-aa3f-4e17-bd40-2a040d5346dc--784435944 | 0200Wa 0784435945 | Neubau | m³ | Mauerarbeiten | 9eee6ca3-aa3f-4e17-bd40-2a040d5346dc--784435945
<Unnamed Element> | EG.- Grundriss | Hlz 115 mm | 0200HWa0784436014 | 9eee6ca3-aa3f-4e17-bd40-2a040d5346dc--784436014 | 0200Wa 0784436020 | Neubau | m³ | Mauerarbeiten | 9eee6ca3-aa3f-4e17-bd40-2a040d5346dc--784436020
<Unnamed Element> | EG.- Grundriss | Hlz 115 mm | 0200HWa0784436016 | 9eee6ca3-aa3f-4e17-bd40-2a040d5346dc--784436016 | 0200Wa 0784436019 | Neubau | m³ | Mauerarbeiten | 9eee6ca3-aa3f-4e17-bd40-2a040d5346dc--784436019
<Unnamed Element> | EG.- Grundriss | Hlz 115 mm | 0200HWa0784436061 | 9eee6ca3-aa3f-4e17-bd40-2a040d5346dc--784436061 | 0200Wa 0784436066 | Neubau | m³ | Mauerarbeiten | 9eee6ca3-aa3f-4e17-bd40-2a040d5346dc--784436066
<Unnamed Element> | EG.- Grundriss | Hlz 115 mm | 0200HWa0784436063 | 9eee6ca3-aa3f-4e17-bd40-2a040d5346dc--784436063 | 0200Wa 0784436065 | Neubau | m³ | Mauerarbeiten | 9eee6ca3-aa3f-4e17-bd40-2a040d5346dc--784436065
2 x <Unnamed Element> | EG.- Grundriss | Hlz 240 mm | 0200HWa0784436110 | 9eee6ca3-aa3f-4e17-bd40-2a040d5346dc--784436110 | 0200Wa 0784436161 | Neubau | m³ | Mauerarbeiten | 9eee6ca3-aa3f-4e17-bd40-2a040d5346dc--784436161
<Unnamed Element> | EG.- Grundriss | Hlz 240 mm | 0200HWa0784436113 | 9eee6ca3-aa3f-4e17-bd40-2a040d5346dc--784436113 | 0200Wa 0784436120 | Neubau | m³ | Mauerarbeiten | 9eee6ca3-aa3f-4e17-bd40-2a040d5346dc--784436120
<Unnamed Element> | EG.- Grundriss | Hlz 240 mm | 0200HWa0784436114 | 9eee6ca3-aa3f-4e17-bd40-2a040d5346dc--784436114 | 0200Wa 0784436157 | Neubau | m³ | Mauerarbeiten | 9eee6ca3-aa3f-4e17-bd40-2a040d5346dc--784436157
<Unnamed Element> | EG.- Grundriss | Hlz 240 mm | 0200HWa0784436115 | 9eee6ca3-aa3f-4e17-bd40-2a040d5346dc--784436115 | 0200Wa 0784436123 | Neubau | m³ | Mauerarbeiten | 9eee6ca3-aa3f-4e17-bd40-2a040d5346dc--784436123
<Unnamed Element> | EG.- Grundriss | Hlz 115 mm | 0200HWa0784436121 | 9eee6ca3-aa3f-4e17-bd40-2a040d5346dc--784436121 | 0200Wa 0784436127 | Neubau | m³ | Mauerarbeiten | 9eee6ca3-aa3f-4e17-bd40-2a040d5346dc--784436127
<Unnamed Element> | EG.- Grundriss | Hlz 115 mm | 0200HWa0784436125 | 9eee6ca3-aa3f-4e17-bd40-2a040d5346dc--784436125 | 0200Wa 0784436129 | Neubau | m³ | Mauerarbeiten | 9eee6ca3-aa3f-4e17-bd40-2a040d5346dc--784436129
<Unnamed Element> | EG.- Grundriss | Hlz 240 mm | 0200HWa0784436131 | 9eee6ca3-aa3f-4e17-bd40-2a040d5346dc--784436131 | 0200Wa 0784436136 | Neubau | m³ | Mauerarbeiten | 9eee6ca3-aa3f-4e17-bd40-2a040d5346dc--784436136
<Unnamed Element> | EG.- Grundriss | Hlz 240 mm | 0200HWa0784436132 | 9eee6ca3-aa3f-4e17-bd40-2a040d5346dc--784436132 | 0200Wa 0784436155 | Neubau | m³ | Mauerarbeiten | 9eee6ca3-aa3f-4e17-bd40-2a040d5346dc--784436155
<Unnamed Element> | EG.- Grundriss | Hlz 115 mm | 0200HWa0784436139 | 9eee6ca3-aa3f-4e17-bd40-2a040d5346dc--784436139 | 0200Wa 0784436147 | Neubau | m³ | Mauerarbeiten | 9eee6ca3-aa3f-4e17-bd40-2a040d5346dc--784436147
<Unnamed Element> | EG.- Grundriss | Hlz 115 mm | 0200HWa0784436140 | 9eee6ca3-aa3f-4e17-bd40-2a040d5346dc--784436140 | 0200Wa 0784436149 | Neubau | m³ | Mauerarbeiten | 9eee6ca3-aa3f-4e17-bd40-2a040d5346dc--784436149
<Unnamed Element> | EG.- Grundriss | Hlz 115 mm | 0200HWa0784436141 | 9eee6ca3-aa3f-4e17-bd40-2a040d5346dc--784436141 | 0200Wa 0784436151 | Neubau | m³ | Mauerarbeiten | 9eee6ca3-aa3f-4e17-bd40-2a040d5346dc--784436151
<Unnamed Element> | EG.- Grundriss | Hlz 240 mm | 0200HWa0784436111 | 9eee6ca3-aa3f-4e17-bd40-2a040d5346dc--784436111 | 0200Wa 0784436159 | Neubau | m³ | Mauerarbeiten | 9eee6ca3-aa3f-4e17-bd40-2a040d5346dc--784436159
<Unnamed Element> | EG.- Grundriss | Hlz 175 mm | 0200HWa0784441474 | 9eee6ca3-aa3f-4e17-bd40-2a040d5346dc--784441474 | 0200Wa 0784441476 | Neubau | m³ | Mauerarbeiten | 9eee6ca3-aa3f-4e17-bd40-2a040d5346dc--784441476
<Unnamed Element> | EG.- Grundriss | Hlz 175 mm | 0200HWa0784441536 | 9eee6ca3-aa3f-4e17-bd40-2a040d5346dc--784441536 | 0200Wa 0784441538 | Neubau | m³ | Mauerarbeiten | 9eee6ca3-aa3f-4e17-bd40-2a040d5346dc--784441538
<Unnamed Element> | EG.- Grundriss | Hlz 175 mm | 0200HWa0784435993 | 9eee6ca3-aa3f-4e17-bd40-2a040d5346dc--784435993 | 0200Wa 0784435994 | Neubau | m³ | Mauerarbeiten | 9eee6ca3-aa3f-4e17-bd40-2a040d5346dc--784435994
<Unnamed Element> | EG.- Grundriss | Hlz 175 mm | 0200HWa0784441551 | 9eee6ca3-aa3f-4e17-bd40-2a040d5346dc--784441551 | 0200Wa 0784441555 | Neubau | m³ | Mauerarbeiten | 9eee6ca3-aa3f-4e17-bd40-2a040d5346dc--784441555
<Unnamed Element> | EG.- Grundriss | Hlz 115 mm | 0200HWa0784441582 | 9eee6ca3-aa3f-4e17-bd40-2a040d5346dc--784441582 | 0200Wa 0784441586 | Neubau | m³ | Mauerarbeiten | 9eee6ca3-aa3f-4e17-bd40-2a040d5346dc--784441586
<Unnamed Element> | EG.- Grundriss | Hlz 115 mm | 0200HWa0784441625 | 9eee6ca3-aa3f-4e17-bd40-2a040d5346dc--784441625 | 0200Wa 0784441630 | Neubau | m³ | Mauerarbeiten | 9eee6ca3-aa3f-4e17-bd40-2a040d5346dc--784441630
<Unnamed Element> | OG.- Grundriss | Poroton 365 mm | 0300HWa0000000002 | 92c99fbc-4ab2-4783-a754-1daa3fa43448--2 | 0300Wa 0000000526 | Neubau | m³ | Mauerarbeiten | 92c99fbc-4ab2-4783-a754-1daa3fa43448--526
<Unnamed Element> | OG.- Grundriss | Poroton 365 mm | 0300HWa0000000003 | 92c99fbc-4ab2-4783-a754-1daa3fa43448--3 | 0300Wa 0000000514 | Neubau | m³ | Mauerarbeiten | 92c99fbc-4ab2-4783-a754-1daa3fa43448--514
<Unnamed Element> | OG.- Grundriss | Poroton 365 mm | 0300HWa0000000004 | 92c99fbc-4ab2-4783-a754-1daa3fa43448--4 | 0300Wa 0000000493 | Neubau | m³ | Mauerarbeiten | 92c99fbc-4ab2-4783-a754-1daa3fa43448--493
<Unnamed Element> | OG.- Grundriss | Poroton 365 mm | 0300HWa0000000007 | 92c99fbc-4ab2-4783-a754-1daa3fa43448--7 | 0300Wa 0000000446 | Neubau | m³ | Mauerarbeiten | 92c99fbc-4ab2-4783-a754-1daa3fa43448--446
<Unnamed Element> | OG.- Grundriss | Poroton 365 mm | 0300HWa0000000010 | 92c99fbc-4ab2-4783-a754-1daa3fa43448--10 | 0300Wa 0000000474 | Neubau | m³ | Mauerarbeiten | 92c99fbc-4ab2-4783-a754-1daa3fa43448--474
<Unnamed Element> | OG.- Grundriss | Poroton 365 mm | 0300HWa0000000011 | 92c99fbc-4ab2-4783-a754-1daa3fa43448--11 | 0300Wa 0000000471 | Neubau | m³ | Mauerarbeiten | 92c99fbc-4ab2-4783-a754-1daa3fa43448--471
<Unnamed Element> | OG.- Grundriss | Poroton 365 mm | 0300HWa0000000014 | 92c99fbc-4ab2-4783-a754-1daa3fa43448--14 | 0300Wa 0000000316 | Neubau | m³ | Mauerarbeiten | 92c99fbc-4ab2-4783-a754-1daa3fa43448--316
<Unnamed Element> | OG.- Grundriss | Poroton 365 mm | 0300HWa0000000017 | 92c99fbc-4ab2-4783-a754-1daa3fa43448--17 | 0300Wa 0000000329 | Neubau | m³ | Mauerarbeiten | 92c99fbc-4ab2-4783-a754-1daa3fa43448--329
<Unnamed Element> | OG.- Grundriss | Hlz 150 mm | 0300HWa0000000025 | 92c99fbc-4ab2-4783-a754-1daa3fa43448--25 | 0300Wa 0000000527 | Neubau | m³ | Mauerarbeiten | 92c99fbc-4ab2-4783-a754-1daa3fa43448--527
<Unnamed Element> | OG.- Grundriss | Poroton 365 mm | 0300HWa0000000026 | 92c99fbc-4ab2-4783-a754-1daa3fa43448--26 | 0300Wa 0000000492 | Neubau | m³ | Mauerarbeiten | 92c99fbc-4ab2-4783-a754-1daa3fa43448--492
<Unnamed Element> | OG.- Grundriss | Hlz 150 mm | 0300HWa0000000028 | 92c99fbc-4ab2-4783-a754-1daa3fa43448--28 | 0300Wa 0000000515 | Neubau | m³ | Mauerarbeiten | 92c99fbc-4ab2-4783-a754-1daa3fa43448--515
<Unnamed Element> | OG.- Grundriss | Poroton 365 mm | 0300HWa0000000029 | 92c99fbc-4ab2-4783-a754-1daa3fa43448--29 | 0300Wa 0000000309 | Neubau | m³ | Mauerarbeiten | 92c99fbc-4ab2-4783-a754-1daa3fa43448--309
<Unnamed Element> | OG.- Grundriss | Poroton 365 mm | 0300HWa0000000031 | 92c99fbc-4ab2-4783-a754-1daa3fa43448--31 | 0300Wa 0000000038 | Neubau | m³ | Mauerarbeiten | 92c99fbc-4ab2-4783-a754-1daa3fa43448--38
<Unnamed Element> | OG.- Grundriss | Poroton 365 mm | 0300HWa0000000033 | 92c99fbc-4ab2-4783-a754-1daa3fa43448--33 | 0300Wa 0000000144 | Neubau | m³ | Mauerarbeiten | 92c99fbc-4ab2-4783-a754-1daa3fa43448--144
<Unnamed Element> | OG.- Grundriss | Poroton 365 mm | 0300HWa0000000036 | 92c99fbc-4ab2-4783-a754-1daa3fa43448--36 | 0300Wa 0000000427 | Neubau | m³ | Mauerarbeiten | 92c99fbc-4ab2-4783-a754-1daa3fa43448--427
<Unnamed Element> | OG.- Grundriss | Stb-Wand 200 mm | 0300HWa0000000039 | 92c99fbc-4ab2-4783-a754-1daa3fa43448--39 | 0300Wa 0000000055 | Neubau | m³ | Betonarbeiten | 92c99fbc-4ab2-4783-a754-1daa3fa43448--55 | Allplan Attributes - Object Layer Attributes #1, statisch_tragend: no
<Unnamed Element> | OG.- Grundriss | Stb-Wand 200 mm | 0300HWa0000000040 | 92c99fbc-4ab2-4783-a754-1daa3fa43448--40 | 0300Wa 0000000056 | Neubau | m³ | Betonarbeiten | 92c99fbc-4ab2-4783-a754-1daa3fa43448--56 | Allplan Attributes - Object Layer Attributes #1, statisch_tragend: no
<Unnamed Element> | OG.- Grundriss | Stb-Wand 200 mm | 0300HWa0000000041 | 92c99fbc-4ab2-4783-a754-1daa3fa43448--41 | 0300Wa 0000000053 | Neubau | m³ | Betonarbeiten | 92c99fbc-4ab2-4783-a754-1daa3fa43448--53 | Allplan Attributes - Object Layer Attributes #1, statisch_tragend: no
<Unnamed Element> | OG.- Grundriss | Hlz 250 mm | 0300HWa0000000044 | 92c99fbc-4ab2-4783-a754-1daa3fa43448--44 | 0300Wa 0000000472 | Neubau | m³ | Mauerarbeiten | 92c99fbc-4ab2-4783-a754-1daa3fa43448--472 | Allplan Attributes - Object Layer Attributes #1, statisch_tragend: no
<Unnamed Element> | OG.- Grundriss | Hlz 250 mm | 0300HWa0000000045 | 92c99fbc-4ab2-4783-a754-1daa3fa43448--45 | 0300Wa 0000000477 | Neubau | m³ | Mauerarbeiten | 92c99fbc-4ab2-4783-a754-1daa3fa43448--477 | Allplan Attributes - Object Layer Attributes #1, statisch_tragend: no
<Unnamed Element> | OG.- Grundriss | Stb-Wand 200 mm | 0300HWa0000000046 | 92c99fbc-4ab2-4783-a754-1daa3fa43448--46 | 0300Wa 0000000054 | Neubau | m³ | Betonarbeiten | 92c99fbc-4ab2-4783-a754-1daa3fa43448--54 | Allplan Attributes - Object Layer Attributes #1, statisch_tragend: no
<Unnamed Element> | OG.- Grundriss | Poroton 365 mm | 0300HWa0000000058 | 92c99fbc-4ab2-4783-a754-1daa3fa43448--58 | 0300Wa 0000000064 | Neubau | m³ | Mauerarbeiten | 92c99fbc-4ab2-4783-a754-1daa3fa43448--64
<Unnamed Element> | OG.- Grundriss | Poroton 365 mm | 0300HWa0000000060 | 92c99fbc-4ab2-4783-a754-1daa3fa43448--60 | 0300Wa 0000000476 | Neubau | m³ | Mauerarbeiten | 92c99fbc-4ab2-4783-a754-1daa3fa43448--476
<Unnamed Element> | OG.- Grundriss | Poroton 365 mm | 0300HWa0000000061 | 92c99fbc-4ab2-4783-a754-1daa3fa43448--61 | 0300Wa 0000000443 | Neubau | m³ | Mauerarbeiten | 92c99fbc-4ab2-4783-a754-1daa3fa43448--443
<Unnamed Element> | OG.- Grundriss | Hlz 115 mm | 0300HWa0000000065 | 92c99fbc-4ab2-4783-a754-1daa3fa43448--65 | 0300Wa 0000000362 | Neubau | m³ | Mauerarbeiten | 92c99fbc-4ab2-4783-a754-1daa3fa43448--362
<Unnamed Element> | OG.- Grundriss | Hlz 115 mm | 0300HWa0000000067 | 92c99fbc-4ab2-4783-a754-1daa3fa43448--67 | 0300Wa 0000000450 | Neubau | m³ | Mauerarbeiten | 92c99fbc-4ab2-4783-a754-1daa3fa43448--450
<Unnamed Element> | OG.- Grundriss | Hlz 115 mm | 0300HWa0000000069 | 92c99fbc-4ab2-4783-a754-1daa3fa43448--69 | 0300Wa 0000000070 | Neubau | m³ | Mauerarbeiten | 92c99fbc-4ab2-4783-a754-1daa3fa43448--70
<Unnamed Element> | OG.- Grundriss | Hlz 115 mm | 0300HWa0000000072 | 92c99fbc-4ab2-4783-a754-1daa3fa43448--72 | 0300Wa 0000000449 | Neubau | m³ | Mauerarbeiten | 92c99fbc-4ab2-4783-a754-1daa3fa43448--449
<Unnamed Element> | OG.- Grundriss | Hlz 115 mm | 0300HWa0000000074 | 92c99fbc-4ab2-4783-a754-1daa3fa43448--74 | 0300Wa 0000000080 | Neubau | m³ | Mauerarbeiten | 92c99fbc-4ab2-4783-a754-1daa3fa43448--80
<Unnamed Element> | OG.- Grundriss | Hlz 115 mm | 0300HWa0000000077 | 92c99fbc-4ab2-4783-a754-1daa3fa43448--77 | 0300Wa 0000000451 | Neubau | m³ | Mauerarbeiten | 92c99fbc-4ab2-4783-a754-1daa3fa43448--451
<Unnamed Element> | OG.- Grundriss | Hlz 115 mm | 0300HWa0000000085 | 92c99fbc-4ab2-4783-a754-1daa3fa43448--85 | 0300Wa 0000000378 | Neubau | m³ | Mauerarbeiten | 92c99fbc-4ab2-4783-a754-1daa3fa43448--378
<Unnamed Element> | OG.- Grundriss | Hlz 115 mm | 0300HWa0000000087 | 92c99fbc-4ab2-4783-a754-1daa3fa43448--87 | 0300Wa 0000000426 | Neubau | m³ | Mauerarbeiten | 92c99fbc-4ab2-4783-a754-1daa3fa43448--426
<Unnamed Element> | OG.- Grundriss | Hlz 115 mm | 0300HWa0000000089 | 92c99fbc-4ab2-4783-a754-1daa3fa43448--89 | 0300Wa 0000000424 | Neubau | m³ | Mauerarbeiten | 92c99fbc-4ab2-4783-a754-1daa3fa43448--424
<Unnamed Element> | OG.- Grundriss | Hlz 115 mm | 0300HWa0000000091 | 92c99fbc-4ab2-4783-a754-1daa3fa43448--91 | 0300Wa 0000000425 | Neubau | m³ | Mauerarbeiten | 92c99fbc-4ab2-4783-a754-1daa3fa43448--425
<Unnamed Element> | OG.- Grundriss | Hlz 115 mm | 0300HWa0000000093 | 92c99fbc-4ab2-4783-a754-1daa3fa43448--93 | 0300Wa 0000000445 | Neubau | m³ | Mauerarbeiten | 92c99fbc-4ab2-4783-a754-1daa3fa43448--445
2 x <Unnamed Element> | OG.- Grundriss | Hlz 240 mm | 0300HWa0000000123 | 92c99fbc-4ab2-4783-a754-1daa3fa43448--123 | 0300Wa 0000000421 | Neubau | m³ | Mauerarbeiten | 92c99fbc-4ab2-4783-a754-1daa3fa43448--421
<Unnamed Element> | OG.- Grundriss | Hlz 240 mm | 0300HWa0000000124 | 92c99fbc-4ab2-4783-a754-1daa3fa43448--124 | 0300Wa 0000000143 | Neubau | m³ | Mauerarbeiten | 92c99fbc-4ab2-4783-a754-1daa3fa43448--143
<Unnamed Element> | OG.- Grundriss | Hlz 240 mm | 0300HWa0000000125 | 92c99fbc-4ab2-4783-a754-1daa3fa43448--125 | 0300Wa 0000000444 | Neubau | m³ | Mauerarbeiten | 92c99fbc-4ab2-4783-a754-1daa3fa43448--444
<Unnamed Element> | OG.- Grundriss | Hlz 240 mm | 0300HWa0000000126 | 92c99fbc-4ab2-4783-a754-1daa3fa43448--126 | 0300Wa 0000000142 | Neubau | m³ | Mauerarbeiten | 92c99fbc-4ab2-4783-a754-1daa3fa43448--142
<Unnamed Element> | OG.- Grundriss | Hlz 115 mm | 0300HWa0000000130 | 92c99fbc-4ab2-4783-a754-1daa3fa43448--130 | 0300Wa 0000000389 | Neubau | m³ | Mauerarbeiten | 92c99fbc-4ab2-4783-a754-1daa3fa43448--389
<Unnamed Element> | OG.- Grundriss | Hlz 115 mm | 0300HWa0000000132 | 92c99fbc-4ab2-4783-a754-1daa3fa43448--132 | 0300Wa 0000000141 | Neubau | m³ | Mauerarbeiten | 92c99fbc-4ab2-4783-a754-1daa3fa43448--141
<Unnamed Element> | OG.- Grundriss | Hlz 240 mm | 0300HWa0000000134 | 92c99fbc-4ab2-4783-a754-1daa3fa43448--134 | 0300Wa 0000000448 | Neubau | m³ | Mauerarbeiten | 92c99fbc-4ab2-4783-a754-1daa3fa43448--448
<Unnamed Element> | OG.- Grundriss | Hlz 115 mm | 0300HWa0000000136 | 92c99fbc-4ab2-4783-a754-1daa3fa43448--136 | 0300Wa 0000000447 | Neubau | m³ | Mauerarbeiten | 92c99fbc-4ab2-4783-a754-1daa3fa43448--447
<Unnamed Element> | OG.- Grundriss | Hlz 115 mm | 0300HWa0000000137 | 92c99fbc-4ab2-4783-a754-1daa3fa43448--137 | 0300Wa 0000000385 | Neubau | m³ | Mauerarbeiten | 92c99fbc-4ab2-4783-a754-1daa3fa43448--385
<Unnamed Element> | OG.- Grundriss | Hlz 115 mm | 0300HWa0000000138 | 92c99fbc-4ab2-4783-a754-1daa3fa43448--138 | 0300Wa 0000000423 | Neubau | m³ | Mauerarbeiten | 92c99fbc-4ab2-4783-a754-1daa3fa43448--423
<Unnamed Element> | OG.- Grundriss | Hlz 240 mm | 0300HWa0000000357 | 92c99fbc-4ab2-4783-a754-1daa3fa43448--357 | 0300Wa 0000000422 | Neubau | m³ | Mauerarbeiten | 92c99fbc-4ab2-4783-a754-1daa3fa43448--422
<Unnamed Element> | OG.- Grundriss | Hlz 175 mm | 0300HWa0000000508 | 92c99fbc-4ab2-4783-a754-1daa3fa43448--508 | 0300Wa 0000000513 | Neubau | m³ | Mauerarbeiten | 92c99fbc-4ab2-4783-a754-1daa3fa43448--513
<Unnamed Element> | OG.- Grundriss | Hlz 175 mm | 0300HWa0000000517 | 92c99fbc-4ab2-4783-a754-1daa3fa43448--517 | 0300Wa 0000000523 | Neubau | m³ | Mauerarbeiten | 92c99fbc-4ab2-4783-a754-1daa3fa43448--523
<Unnamed Element> | OG.- Grundriss | Hlz 115 mm | 0300HWa0784441913 | 92c99fbc-4ab2-4783-a754-1daa3fa43448--784441913 | 0300Wa 0784441918 | Neubau | m³ | Mauerarbeiten | 92c99fbc-4ab2-4783-a754-1daa3fa43448--784441918
<Unnamed Element> | OG.- Grundriss | Hlz 115 mm | 0300HWa0784441924 | 92c99fbc-4ab2-4783-a754-1daa3fa43448--784441924 | 0300Wa 0784441929 | Neubau | m³ | Mauerarbeiten | 92c99fbc-4ab2-4783-a754-1daa3fa43448--784441929
<Unnamed Element> | OG.- Grundriss | Hlz 115 mm | 0300HWa0784441934 | 92c99fbc-4ab2-4783-a754-1daa3fa43448--784441934 | 0300Wa 0784441940 | Neubau | m³ | Mauerarbeiten | 92c99fbc-4ab2-4783-a754-1daa3fa43448--784441940
<Unnamed Element> | OG.- Grundriss | Hlz 115 mm | 0300HWa0000000096 | 92c99fbc-4ab2-4783-a754-1daa3fa43448--96 | 0300Wa 0000000109 | Neubau | m³ | Mauerarbeiten | 92c99fbc-4ab2-4783-a754-1daa3fa43448--109
<Unnamed Element> | OG.- Grundriss | Hlz 115 mm | 0300HWa0000000100 | 92c99fbc-4ab2-4783-a754-1daa3fa43448--100 | 0300Wa 0000000500 | Neubau | m³ | Mauerarbeiten | 92c99fbc-4ab2-4783-a754-1daa3fa43448--500
<Unnamed Element> | OG.- Grundriss | Hlz 115 mm | 0300HWa0784442044 | 92c99fbc-4ab2-4783-a754-1daa3fa43448--784442044 | 0300Wa 0784442048 | Neubau | m³ | Mauerarbeiten | 92c99fbc-4ab2-4783-a754-1daa3fa43448--784442048
<Unnamed Element> | OG.- Grundriss | Hlz 115 mm | 0300HWa0784442045 | 92c99fbc-4ab2-4783-a754-1daa3fa43448--784442045 | 0300Wa 0784442052 | Neubau | m³ | Mauerarbeiten | 92c99fbc-4ab2-4783-a754-1daa3fa43448--784442052
<Unnamed Element> | OG.- Grundriss | Hlz 115 mm | 0300HWa0000000081 | 92c99fbc-4ab2-4783-a754-1daa3fa43448--81 | 0300Wa 0000000473 | Neubau | m³ | Mauerarbeiten | 92c99fbc-4ab2-4783-a754-1daa3fa43448--473
<Unnamed Element> | OG.- Grundriss | Hlz 115 mm | 0300HWa0000000083 | 92c99fbc-4ab2-4783-a754-1daa3fa43448--83 | 0300Wa 0000000452 | Neubau | m³ | Mauerarbeiten | 92c99fbc-4ab2-4783-a754-1daa3fa43448--452
<Unnamed Element> | OG.- Grundriss | Hlz 240 mm | 0300HWa0000000135 | 92c99fbc-4ab2-4783-a754-1daa3fa43448--135 | 0300Wa 0000000475 | Neubau | m³ | Mauerarbeiten | 92c99fbc-4ab2-4783-a754-1daa3fa43448--475
<Unnamed Element> | OG.- Grundriss | Hlz 115 mm | 0300HWa0784442279 | 92c99fbc-4ab2-4783-a754-1daa3fa43448--784442279 | 0300Wa 0784442285 | Neubau | m³ | Mauerarbeiten | 92c99fbc-4ab2-4783-a754-1daa3fa43448--784442285
<Unnamed Element> | OG.- Grundriss | Hlz 115 mm | 0300HWa0784442280 | 92c99fbc-4ab2-4783-a754-1daa3fa43448--784442280 | 0300Wa 0784442287 | Neubau | m³ | Mauerarbeiten | 92c99fbc-4ab2-4783-a754-1daa3fa43448--784442287
<Unnamed Element> | OG.- Grundriss | Hlz 115 mm | 0300HWa0784442281 | 92c99fbc-4ab2-4783-a754-1daa3fa43448--784442281 | 0300Wa 0784442286 | Neubau | m³ | Mauerarbeiten | 92c99fbc-4ab2-4783-a754-1daa3fa43448--784442286
<Unnamed Element> | OG.- Grundriss | Hlz 240 mm | 0300HWa0784445594 | 92c99fbc-4ab2-4783-a754-1daa3fa43448--784445594 | 0300Wa 0784445598 | Neubau | m³ | Mauerarbeiten | 92c99fbc-4ab2-4783-a754-1daa3fa43448--784445598
<Unnamed Element> | OG.- Grundriss | Hlz 240 mm | 0300HWa0784445665 | 92c99fbc-4ab2-4783-a754-1daa3fa43448--784445665 | 0300Wa 0784445667 | Neubau | m³ | Mauerarbeiten | 92c99fbc-4ab2-4783-a754-1daa3fa43448--784445667
<Unnamed Element> | OG.- Grundriss | Poroton 365 mm | 0300HWa0000000008 | 92c99fbc-4ab2-4783-a754-1daa3fa43448--8 | 0300Wa 0000000442 | Neubau | m³ | Mauerarbeiten | 92c99fbc-4ab2-4783-a754-1daa3fa43448--442 | Allplan Attributes - Object Layer Attributes #1, Material: Poroton
<Unnamed Element> | DG.- Grundriss | Poroton 365 mm | 0500HWa0000000001 | 1bfc5a75-329c-4bd5-adfb-044822b851e1--1 | 0500Wa 0000000514 | Neubau | m³ | Mauerarbeiten | 1bfc5a75-329c-4bd5-adfb-044822b851e1--514
<Unnamed Element> | DG.- Grundriss | Poroton 365 mm | 0500HWa0000000002 | 1bfc5a75-329c-4bd5-adfb-044822b851e1--2 | 0500Wa 0000000507 | Neubau | m³ | Mauerarbeiten | 1bfc5a75-329c-4bd5-adfb-044822b851e1--507
<Unnamed Element> | DG.- Grundriss | Poroton 365 mm | 0500HWa0000000003 | 1bfc5a75-329c-4bd5-adfb-044822b851e1--3 | 0500Wa 0000000477 | Neubau | m³ | Mauerarbeiten | 1bfc5a75-329c-4bd5-adfb-044822b851e1--477
<Unnamed Element> | DG.- Grundriss | Poroton 365 mm | 0500HWa0000000006 | 1bfc5a75-329c-4bd5-adfb-044822b851e1--6 | 0500Wa 0000000335 | Neubau | m³ | Mauerarbeiten | 1bfc5a75-329c-4bd5-adfb-044822b851e1--335
<Unnamed Element> | DG.- Grundriss | Poroton 365 mm | 0500HWa0000000007 | 1bfc5a75-329c-4bd5-adfb-044822b851e1--7 | 0500Wa 0000000336 | Neubau | m³ | Mauerarbeiten | 1bfc5a75-329c-4bd5-adfb-044822b851e1--336
<Unnamed Element> | DG.- Grundriss | Poroton 365 mm | 0500HWa0000000010 | 1bfc5a75-329c-4bd5-adfb-044822b851e1--10 | 0500Wa 0000000428 | Neubau | m³ | Mauerarbeiten | 1bfc5a75-329c-4bd5-adfb-044822b851e1--428
<Unnamed Element> | DG.- Grundriss | Poroton 365 mm | 0500HWa0000000016 | 1bfc5a75-329c-4bd5-adfb-044822b851e1--16 | 0500Wa 0000000464 | Neubau | m³ | Mauerarbeiten | 1bfc5a75-329c-4bd5-adfb-044822b851e1--464
<Unnamed Element> | DG.- Grundriss | Hlz 150 mm | 0500HWa0000000018 | 1bfc5a75-329c-4bd5-adfb-044822b851e1--18 | 0500Wa 0000000359 | Neubau | m³ | Mauerarbeiten | 1bfc5a75-329c-4bd5-adfb-044822b851e1--359
<Unnamed Element> | DG.- Grundriss | Poroton 365 mm | 0500HWa0000000019 | 1bfc5a75-329c-4bd5-adfb-044822b851e1--19 | 0500Wa 0000000502 | Neubau | m³ | Mauerarbeiten | 1bfc5a75-329c-4bd5-adfb-044822b851e1--502
<Unnamed Element> | DG.- Grundriss | Hlz 150 mm | 0500HWa0000000021 | 1bfc5a75-329c-4bd5-adfb-044822b851e1--21 | 0500Wa 0000000356 | Neubau | m³ | Mauerarbeiten | 1bfc5a75-329c-4bd5-adfb-044822b851e1--356
<Unnamed Element> | DG.- Grundriss | Poroton 365 mm | 0500HWa0000000026 | 1bfc5a75-329c-4bd5-adfb-044822b851e1--26 | 0500Wa 0000000370 | Neubau | m³ | Mauerarbeiten | 1bfc5a75-329c-4bd5-adfb-044822b851e1--370
<Unnamed Element> | DG.- Grundriss | Poroton 365 mm | 0500HWa0000000044 | 1bfc5a75-329c-4bd5-adfb-044822b851e1--44 | 0500Wa 0000000364 | Neubau | m³ | Mauerarbeiten | 1bfc5a75-329c-4bd5-adfb-044822b851e1--364
<Unnamed Element> | DG.- Grundriss | Poroton 365 mm | 0500HWa0000000046 | 1bfc5a75-329c-4bd5-adfb-044822b851e1--46 | 0500Wa 0000000435 | Neubau | m³ | Mauerarbeiten | 1bfc5a75-329c-4bd5-adfb-044822b851e1--435
<Unnamed Element> | DG.- Grundriss | Poroton 365 mm | 0500HWa0000000047 | 1bfc5a75-329c-4bd5-adfb-044822b851e1--47 | 0500Wa 0000000448 | Neubau | m³ | Mauerarbeiten | 1bfc5a75-329c-4bd5-adfb-044822b851e1--448
<Unnamed Element> | DG.- Grundriss | Hlz 240 mm | 0500HWa0000000076 | 1bfc5a75-329c-4bd5-adfb-044822b851e1--76 | 0500Wa 0000000369 | Neubau | m³ | Mauerarbeiten | 1bfc5a75-329c-4bd5-adfb-044822b851e1--369
<Unnamed Element> | DG.- Grundriss | Hlz 240 mm | 0500HWa0000000077 | 1bfc5a75-329c-4bd5-adfb-044822b851e1--77 | 0500Wa 0000000381 | Neubau | m³ | Mauerarbeiten | 1bfc5a75-329c-4bd5-adfb-044822b851e1--381
<Unnamed Element> | DG.- Grundriss | Hlz 240 mm | 0500HWa0000000078 | 1bfc5a75-329c-4bd5-adfb-044822b851e1--78 | 0500Wa 0000000368 | Neubau | m³ | Mauerarbeiten | 1bfc5a75-329c-4bd5-adfb-044822b851e1--368
<Unnamed Element> | DG.- Grundriss | Hlz 115 mm | 0500HWa0000000082 | 1bfc5a75-329c-4bd5-adfb-044822b851e1--82 | 0500Wa 0000000374 | Neubau | m³ | Mauerarbeiten | 1bfc5a75-329c-4bd5-adfb-044822b851e1--374
<Unnamed Element> | DG.- Grundriss | Hlz 115 mm | 0500HWa0000000084 | 1bfc5a75-329c-4bd5-adfb-044822b851e1--84 | 0500Wa 0000000367 | Neubau | m³ | Mauerarbeiten | 1bfc5a75-329c-4bd5-adfb-044822b851e1--367
<Unnamed Element> | DG.- Grundriss | Hlz 240 mm | 0500HWa0000000086 | 1bfc5a75-329c-4bd5-adfb-044822b851e1--86 | 0500Wa 0000000383 | Neubau | m³ | Mauerarbeiten | 1bfc5a75-329c-4bd5-adfb-044822b851e1--383
2 x <Unnamed Element> | DG.- Grundriss | Hlz 240 mm | 0500HWa0000000106 | 1bfc5a75-329c-4bd5-adfb-044822b851e1--106 | 0500Wa 0000000376 | Neubau | m³ | Mauerarbeiten | 1bfc5a75-329c-4bd5-adfb-044822b851e1--376
<Unnamed Element> | DG.- Grundriss | Hlz 175 mm | 0500HWa0000000152 | 1bfc5a75-329c-4bd5-adfb-044822b851e1--152 | 0500Wa 0000000523 | Neubau | m³ | Mauerarbeiten | 1bfc5a75-329c-4bd5-adfb-044822b851e1--523
<Unnamed Element> | DG.- Grundriss | Hlz 175 mm | 0500HWa0000000153 | 1bfc5a75-329c-4bd5-adfb-044822b851e1--153 | 0500Wa 0000000531 | Neubau | m³ | Mauerarbeiten | 1bfc5a75-329c-4bd5-adfb-044822b851e1--531
<Unnamed Element> | DG.- Grundriss | Hlz 115 mm | 0500HWa0000000164 | 1bfc5a75-329c-4bd5-adfb-044822b851e1--164 | 0500Wa 0000000353 | Neubau | m³ | Mauerarbeiten | 1bfc5a75-329c-4bd5-adfb-044822b851e1--353
<Unnamed Element> | DG.- Grundriss | Hlz 115 mm | 0500HWa0000000170 | 1bfc5a75-329c-4bd5-adfb-044822b851e1--170 | 0500Wa 0000000352 | Neubau | m³ | Mauerarbeiten | 1bfc5a75-329c-4bd5-adfb-044822b851e1--352
<Unnamed Element> | DG.- Grundriss | Poroton 365 mm | 0500HWa0784446711 | 1bfc5a75-329c-4bd5-adfb-044822b851e1--784446711 | 0500Wa 0784446713 | Neubau | m³ | Mauerarbeiten | 1bfc5a75-329c-4bd5-adfb-044822b851e1--784446713
<Unnamed Element> | DG.- Grundriss | Poroton 365 mm | 0500HWa0784446805 | 1bfc5a75-329c-4bd5-adfb-044822b851e1--784446805 | 0500Wa 0784446807 | Neubau | m³ | Mauerarbeiten | 1bfc5a75-329c-4bd5-adfb-044822b851e1--784446807
<Unnamed Element> | DG.- Grundriss | Hlz 240 mm | 0500HWa0784446898 | 1bfc5a75-329c-4bd5-adfb-044822b851e1--784446898 | 0500Wa 0784446908 | Neubau | m³ | Mauerarbeiten | 1bfc5a75-329c-4bd5-adfb-044822b851e1--784446908
<Unnamed Element> | DG.- Grundriss | Hlz 240 mm | 0500HWa0784446985 | 1bfc5a75-329c-4bd5-adfb-044822b851e1--784446985 | 0500Wa 0784446988 | Neubau | m³ | Mauerarbeiten | 1bfc5a75-329c-4bd5-adfb-044822b851e1--784446988
<Unnamed Element> | DG.- Grundriss | Hlz 240 mm | 0500HWa0784447014 | 1bfc5a75-329c-4bd5-adfb-044822b851e1--784447014 | 0500Wa 0784447020 | Neubau | m³ | Mauerarbeiten | 1bfc5a75-329c-4bd5-adfb-044822b851e1--784447020
<Unnamed Element> | DG.- Grundriss | Hlz 240 mm | 0500HWa0000000184 | 1bfc5a75-329c-4bd5-adfb-044822b851e1--184 | 0500Wa 0000000345 | Neubau | m³ | Mauerarbeiten | 1bfc5a75-329c-4bd5-adfb-044822b851e1--345
<Unnamed Element> | DG.- Grundriss | Hlz 115 mm | 0500HWa0000000058 | 1bfc5a75-329c-4bd5-adfb-044822b851e1--58 | 0500Wa 0000000366 | Neubau | m³ | Mauerarbeiten | 1bfc5a75-329c-4bd5-adfb-044822b851e1--366
<Unnamed Element> | DG.- Grundriss | Hlz 115 mm | 0500HWa0000000052 | 1bfc5a75-329c-4bd5-adfb-044822b851e1--52 | 0500Wa 0000000343 | Neubau | m³ | Mauerarbeiten | 1bfc5a75-329c-4bd5-adfb-044822b851e1--343
<Unnamed Element> | DG.- Grundriss | Hlz 115 mm | 0500HWa0000000054 | 1bfc5a75-329c-4bd5-adfb-044822b851e1--54 | 0500Wa 0000000365 | Neubau | m³ | Mauerarbeiten | 1bfc5a75-329c-4bd5-adfb-044822b851e1--365
<Unnamed Element> | DG.- Grundriss | Hlz 240 mm | 0500HWa0784447314 | 1bfc5a75-329c-4bd5-adfb-044822b851e1--784447314 | 0500Wa 0784447324 | Neubau | m³ | Mauerarbeiten | 1bfc5a75-329c-4bd5-adfb-044822b851e1--784447324
<Unnamed Element> | DG.- Grundriss | Hlz 240 mm | 0500HWa0784447253 | 1bfc5a75-329c-4bd5-adfb-044822b851e1--784447253 | 0500Wa 0784447263 | Neubau | m³ | Mauerarbeiten | 1bfc5a75-329c-4bd5-adfb-044822b851e1--784447263
<Unnamed Element> | DG.- Grundriss | Hlz 115 mm | 0500HWa0000000064 | 1bfc5a75-329c-4bd5-adfb-044822b851e1--64 | 0500Wa 0000000372 | Neubau | m³ | Mauerarbeiten | 1bfc5a75-329c-4bd5-adfb-044822b851e1--372
<Unnamed Element> | DG.- Grundriss | Hlz 240 mm | 0500HWa0000000075 | 1bfc5a75-329c-4bd5-adfb-044822b851e1--75 | 0500Wa 0000000375 | Neubau | m³ | Mauerarbeiten | 1bfc5a75-329c-4bd5-adfb-044822b851e1--375
<Unnamed Element> | DG.- Grundriss | Hlz 240 mm | 0500HWa0784447468 | 1bfc5a75-329c-4bd5-adfb-044822b851e1--784447468 | 0500Wa 0784447470 | Neubau | m³ | Mauerarbeiten | 1bfc5a75-329c-4bd5-adfb-044822b851e1--784447470
<Unnamed Element> | DG.- Grundriss | Hlz 115 mm | 0500HWa0000000066 | 1bfc5a75-329c-4bd5-adfb-044822b851e1--66 | 0500Wa 0000000380 | Neubau | m³ | Mauerarbeiten | 1bfc5a75-329c-4bd5-adfb-044822b851e1--380
<Unnamed Element> | DG.- Grundriss | Hlz 115 mm | 0500HWa0000000068 | 1bfc5a75-329c-4bd5-adfb-044822b851e1--68 | 0500Wa 0000000378 | Neubau | m³ | Mauerarbeiten | 1bfc5a75-329c-4bd5-adfb-044822b851e1--378
<Unnamed Element> | DG.- Grundriss | Hlz 115 mm | 0500HWa0000000072 | 1bfc5a75-329c-4bd5-adfb-044822b851e1--72 | 0500Wa 0000000337 | Neubau | m³ | Mauerarbeiten | 1bfc5a75-329c-4bd5-adfb-044822b851e1--337
<Unnamed Element> | DG.- Grundriss | Hlz 115 mm | 0500HWa0784447558 | 1bfc5a75-329c-4bd5-adfb-044822b851e1--784447558 | 0500Wa 0784447564 | Neubau | m³ | Mauerarbeiten | 1bfc5a75-329c-4bd5-adfb-044822b851e1--784447564
<Unnamed Element> | DG.- Grundriss | Hlz 115 mm | 0500HWa0784447596 | 1bfc5a75-329c-4bd5-adfb-044822b851e1--784447596 | 0500Wa 0784447599 | Neubau | m³ | Mauerarbeiten | 1bfc5a75-329c-4bd5-adfb-044822b851e1--784447599
<Unnamed Element> | DG.- Grundriss | Hlz 115 mm | 0500HWa0784447678 | 1bfc5a75-329c-4bd5-adfb-044822b851e1--784447678 | 0500Wa 0784447683 | Neubau | m³ | Mauerarbeiten | 1bfc5a75-329c-4bd5-adfb-044822b851e1--784447683
<Unnamed Element> | DG.- Grundriss | Hlz 115 mm | 0500HWa0000000088 | 1bfc5a75-329c-4bd5-adfb-044822b851e1--88 | 0500Wa 0000000373 | Neubau | m³ | Mauerarbeiten | 1bfc5a75-329c-4bd5-adfb-044822b851e1--373
<Unnamed Element> | DG.- Grundriss | Hlz 115 mm | 0500HWa0000000163 | 1bfc5a75-329c-4bd5-adfb-044822b851e1--163 | 0500Wa 0000000354 | Neubau | m³ | Mauerarbeiten | 1bfc5a75-329c-4bd5-adfb-044822b851e1--354
<Unnamed Element> | DG.- Grundriss | Hlz 115 mm | 0500HWa0000000169 | 1bfc5a75-329c-4bd5-adfb-044822b851e1--169 | 0500Wa 0000000351 | Neubau | m³ | Mauerarbeiten | 1bfc5a75-329c-4bd5-adfb-044822b851e1--351
<Unnamed Element> | DG.- Grundriss | Hlz 115 mm | 0500HWa0784447737 | 1bfc5a75-329c-4bd5-adfb-044822b851e1--784447737 | 0500Wa 0784447741 | Neubau | m³ | Mauerarbeiten | 1bfc5a75-329c-4bd5-adfb-044822b851e1--784447741
<Unnamed Element> | DG.- Grundriss | Hlz 115 mm | 0500HWa0784447739 | 1bfc5a75-329c-4bd5-adfb-044822b851e1--784447739 | 0500Wa 0784447743 | Neubau | m³ | Mauerarbeiten | 1bfc5a75-329c-4bd5-adfb-044822b851e1--784447743
<Unnamed Element> | DG.- Grundriss | Hlz 115 mm | 0500HWa0784447667 | 1bfc5a75-329c-4bd5-adfb-044822b851e1--784447667 | 0500Wa 0784447669 | Neubau | m³ | Mauerarbeiten | 1bfc5a75-329c-4bd5-adfb-044822b851e1--784447669
<Unnamed Element> | DG.- Grundriss | Poroton 365 mm | 0500HWa0000000013 | 1bfc5a75-329c-4bd5-adfb-044822b851e1--13 | 0500Wa 0000000349 | Neubau | m³ | Mauerarbeiten | 1bfc5a75-329c-4bd5-adfb-044822b851e1--349 | Allplan Attributes - Object Layer Attributes #1, Material: Poroton
<Unnamed Element> | DG.- Grundriss | Poroton 365 mm | 0500HWa0000000022 | 1bfc5a75-329c-4bd5-adfb-044822b851e1--22 | 0500Wa 0000000348 | Neubau | m³ | Mauerarbeiten | 1bfc5a75-329c-4bd5-adfb-044822b851e1--348 | Allplan Attributes - Object Layer Attributes #1, Material: Poroton
<Unnamed Element> | DG.- Grundriss | Poroton 365 mm | 0500HWa0000000024 | 1bfc5a75-329c-4bd5-adfb-044822b851e1--24 | 0500Wa 0000000350 | Neubau | m³ | Mauerarbeiten | 1bfc5a75-329c-4bd5-adfb-044822b851e1--350 | Allplan Attributes - Object Layer Attributes #1, Material: Poroton
<Unnamed Element> | DG.- Grundriss | Hlz 115 mm | 0500HWa0784449465 | 1bfc5a75-329c-4bd5-adfb-044822b851e1--784449465 | 0500Wa 0784449471 | Neubau | m³ | Mauerarbeiten | 1bfc5a75-329c-4bd5-adfb-044822b851e1--784449471
<Unnamed Element> | DG.- Grundriss | Hlz 115 mm | 0500HWa0784449496 | 1bfc5a75-329c-4bd5-adfb-044822b851e1--784449496 | 0500Wa 0784449498 | Neubau | m³ | Mauerarbeiten | 1bfc5a75-329c-4bd5-adfb-044822b851e1--784449498
<Unnamed Element> | DG.- Grundriss | Metallgitterwand 50 mm | 0500HWa0784449579 | 1bfc5a75-329c-4bd5-adfb-044822b851e1--784449579 | 0500Wa 0784449581 |  | m² | Stahlbauarbeiten | 1bfc5a75-329c-4bd5-adfb-044822b851e1--784449581
<Unnamed Element> | DG.- Grundriss | Metallgitterwand 50 mm | 0500HWa0784449586 | 1bfc5a75-329c-4bd5-adfb-044822b851e1--784449586 | 0500Wa 0784449588 |  | m² | Stahlbauarbeiten | 1bfc5a75-329c-4bd5-adfb-044822b851e1--784449588
<Unnamed Element> | DG.- Grundriss | Metallgitterwand 50 mm | 0500HWa0784449599 | 1bfc5a75-329c-4bd5-adfb-044822b851e1--784449599 | 0500Wa 0784449601 |  | m² | Stahlbauarbeiten | 1bfc5a75-329c-4bd5-adfb-044822b851e1--784449601
<Unnamed Element> | DG.- Grundriss | Metallgitterwand 50 mm | 0500HWa0784449609 | 1bfc5a75-329c-4bd5-adfb-044822b851e1--784449609 | 0500Wa 0784449611 |  | m² | Stahlbauarbeiten | 1bfc5a75-329c-4bd5-adfb-044822b851e1--784449611
<Unnamed Element> | DG.- Grundriss | Metallgitterwand 50 mm | 0500HWa0784449617 | 1bfc5a75-329c-4bd5-adfb-044822b851e1--784449617 | 0500Wa 0784449619 |  | m² | Stahlbauarbeiten | 1bfc5a75-329c-4bd5-adfb-044822b851e1--784449619
<Unnamed Element> | DG.- Grundriss | Metallgitterwand 50 mm | 0500HWa0784449622 | 1bfc5a75-329c-4bd5-adfb-044822b851e1--784449622 | 0500Wa 0784449624 |  | m² | Stahlbauarbeiten | 1bfc5a75-329c-4bd5-adfb-044822b851e1--784449624
<Unnamed Element> | DG.- Grundriss | Metallgitterwand 50 mm | 0500HWa0784449444 | 1bfc5a75-329c-4bd5-adfb-044822b851e1--784449444 | 0500Wa 0784449454 |  | m² | Stahlbauarbeiten | 1bfc5a75-329c-4bd5-adfb-044822b851e1--784449454

# IfcWindow: Fenster
In: KG.- Grundriss
Type - OperationType: SINGLE_PANEL; ParameterTakesPrecedence: no; Sizeable: no
Type - IfcWindowLiningProperties - LiningDepth: 50 mm; LiningThickness: 50 mm; FirstTransomOffset: 0; SecondTransomOffset: 0; FirstMullionOffset: 0; SecondMullionOffset: 0
Type - IfcWindowPanelProperties - OperationType: FIXEDCASEMENT; PanelPosition: MIDDLE
OverallHeight: 600 mm; OverallWidth: 1010 mm
Allplan Attributes - Allright_Bauteil_ID: 0117Mak0781540353; Einheit: St; V6: 5; V7: 10; V8: 0; V9: 0; NOI_UUID: 09ef5a79-666f-4d65-ae11-371ec0050284--781540353

# IfcWindow: Fenster (2)
In: KG.- Grundriss
Type - OperationType: SINGLE_PANEL; ParameterTakesPrecedence: yes; Sizeable: no
Type - IfcWindowLiningProperties - LiningDepth: 50 mm; LiningThickness: 50 mm; FirstTransomOffset: 0; SecondTransomOffset: 0; FirstMullionOffset: 0; SecondMullionOffset: 0
Type - IfcWindowPanelProperties - OperationType: TILTANDTURNLEFTHAND; PanelPosition: MIDDLE; FrameDepth: 50 mm; FrameThickness: 50 mm
OverallHeight: 600 mm; OverallWidth: 1010 mm
Allplan Attributes - Einheit: St; V6: 5; V7: 10; V8: 0; V9: 0
Name | Allright_Bauteil_ID | NOI_UUID
Fenster | 0117Mak0781540221 | 09ef5a79-666f-4d65-ae11-371ec0050284--781540221
Fenster | 0117Mak0781540349 | 09ef5a79-666f-4d65-ae11-371ec0050284--781540349

# IfcWindow: Fenster (2)
In: KG.- Grundriss
Type - OperationType: SINGLE_PANEL; ParameterTakesPrecedence: yes; Sizeable: no
Type - IfcWindowLiningProperties - LiningDepth: 50 mm; LiningThickness: 50 mm; FirstTransomOffset: 0; SecondTransomOffset: 0; FirstMullionOffset: 0; SecondMullionOffset: 0
Type - IfcWindowPanelProperties - OperationType: TILTANDTURNRIGHTHAND; PanelPosition: MIDDLE; FrameDepth: 50 mm; FrameThickness: 50 mm
OverallHeight: 600 mm; OverallWidth: 1010 mm
Allplan Attributes - Einheit: St; V6: 5; V7: 10; V8: 0; V9: 0
Name | Allright_Bauteil_ID | NOI_UUID
Fenster | 0100Mak0780220467 | bb7460a6-57d8-45f2-954a-172a4282fe15--780220467
Fenster | 0117Mak0781540215 | 09ef5a79-666f-4d65-ae11-371ec0050284--781540215

# IfcWindow: Fenster (104)
Type - OperationType: USERDEFINED; ParameterTakesPrecedence: no; Sizeable: no
Pset_WindowCommon - GlazingAreaFraction: 1
Allplan Attributes - Einheit: St; V6: 0; V7: 0; V8: 0; V9: 0; Programmversion: 2.2; Bezeichnung: Fenster; Plugin_Bezeichnung: MainObject; Plugin_Objektname: SmartPartCompressed; Version: 4.1; Einbauhöhe_Fensterbank_Außen: 0; Einbauhöhe_Fensterbank_Innen: 0; Abstand_Öffn_Unten: 0; Abstand_Öffn_Oben: 0; Abstand_Öffn_Links: 0; Abstand_Öffn_Rechts: 0; Abzug_Öffn_Links: 70; Abzug_Öffn_Rechts: 70; Abzug_Öffn_Oben: 370
Name | In | OverallHeight (mm) | OverallWidth (mm) | Allright_Bauteil_ID | NOI_UUID | Glasfläche | Abzug_Öffn_Unten
Fenster | EG.- Grundriss | 1710 | 885 | 0200Mak0784438503 | 9eee6ca3-aa3f-4e17-bd40-2a040d5346dc--784438503 | 0.75465 | 70
Fenster | EG.- Grundriss | 1710 | 885 | 0200Mak0784438480 | 9eee6ca3-aa3f-4e17-bd40-2a040d5346dc--784438480 | 0.75465 | 70
Fenster | EG.- Grundriss | 1710 | 1760 | 0200Mak0784438342 | 9eee6ca3-aa3f-4e17-bd40-2a040d5346dc--784438342 | 1.61343 | 70
Fenster | EG.- Grundriss | 1710 | 885 | 0200Mak0784438457 | 9eee6ca3-aa3f-4e17-bd40-2a040d5346dc--784438457 | 0.75465 | 70
Fenster | EG.- Grundriss | 1710 | 885 | 0200Mak0784438434 | 9eee6ca3-aa3f-4e17-bd40-2a040d5346dc--784438434 | 0.75465 | 70
Fenster | EG.- Grundriss | 1710 | 1760 | 0200Mak0784438411 | 9eee6ca3-aa3f-4e17-bd40-2a040d5346dc--784438411 | 1.61343 | 70
Fenster | EG.- Grundriss | 1710 | 885 | 0200Mak0784438550 | 9eee6ca3-aa3f-4e17-bd40-2a040d5346dc--784438550 | 0.75465 | 70
Fenster | EG.- Grundriss | 1710 | 885 | 0200Mak0784438526 | 9eee6ca3-aa3f-4e17-bd40-2a040d5346dc--784438526 | 0.75465 | 70
Fenster | EG.- Grundriss | 2730 | 885 | 0200Mak0784440918 | 9eee6ca3-aa3f-4e17-bd40-2a040d5346dc--784440918 | 1.35065 | 220
Fenster | EG.- Grundriss | 2730 | 1760 | 0200Mak0784440924 | 9eee6ca3-aa3f-4e17-bd40-2a040d5346dc--784440924 | 2.81316 | 220
Fenster | EG.- Grundriss | 2730 | 1760 | 0200Mak0784440912 | 9eee6ca3-aa3f-4e17-bd40-2a040d5346dc--784440912 | 2.81316 | 220
Fenster | EG.- Grundriss | 2730 | 885 | 0200Mak0784440897 | 9eee6ca3-aa3f-4e17-bd40-2a040d5346dc--784440897 | 1.35065 | 220
Fenster | EG.- Grundriss | 1710 | 885 | 0200Mak0784439598 | 9eee6ca3-aa3f-4e17-bd40-2a040d5346dc--784439598 | 0.75465 | 70
Fenster | EG.- Grundriss | 2730 | 885 | 0200Mak0784439585 | 9eee6ca3-aa3f-4e17-bd40-2a040d5346dc--784439585 | 1.35065 | 220
Fenster | EG.- Grundriss | 2730 | 1760 | 0200Mak0784439570 | 9eee6ca3-aa3f-4e17-bd40-2a040d5346dc--784439570 | 2.90943 | 220
Fenster | EG.- Grundriss | 2730 | 1760 | 0200Mak0784439556 | 9eee6ca3-aa3f-4e17-bd40-2a040d5346dc--784439556 | 2.90943 | 220
Fenster | EG.- Grundriss | 2730 | 1760 | 0200Mak0784439543 | 9eee6ca3-aa3f-4e17-bd40-2a040d5346dc--784439543 | 2.90943 | 220
Fenster | EG.- Grundriss | 1710 | 885 | 0200Mak0784439528 | 9eee6ca3-aa3f-4e17-bd40-2a040d5346dc--784439528 | 0.75465 | 70
Fenster | EG.- Grundriss | 2730 | 885 | 0200Mak0784439451 | 9eee6ca3-aa3f-4e17-bd40-2a040d5346dc--784439451 | 1.35065 | 220
Fenster | EG.- Grundriss | 2730 | 1760 | 0200Mak0784439273 | 9eee6ca3-aa3f-4e17-bd40-2a040d5346dc--784439273 | 2.90943 | 220
Fenster | EG.- Grundriss | 1710 | 885 | 0200Mak0784439183 | 9eee6ca3-aa3f-4e17-bd40-2a040d5346dc--784439183 | 0.75465 | 70
Fenster | EG.- Grundriss | 1710 | 1760 | 0200Mak0784439169 | 9eee6ca3-aa3f-4e17-bd40-2a040d5346dc--784439169 | 1.61343 | 70
Fenster | EG.- Grundriss | 2730 | 885 | 0200Mak0784439665 | 9eee6ca3-aa3f-4e17-bd40-2a040d5346dc--784439665 | 1.35065 | 220
Fenster | EG.- Grundriss | 2730 | 885 | 0200Mak0784439651 | 9eee6ca3-aa3f-4e17-bd40-2a040d5346dc--784439651 | 1.35065 | 220
Fenster | EG.- Grundriss | 2730 | 1340.52 | 0200Mak0784439741 | 9eee6ca3-aa3f-4e17-bd40-2a040d5346dc--784439741 | 2.19065 | 220
Fenster | EG.- Grundriss | 2730 | 885 | 0200Mak0784440132 | 9eee6ca3-aa3f-4e17-bd40-2a040d5346dc--784440132 | 1.35065 | 220
Fenster | EG.- Grundriss | 2730 | 1760 | 0200Mak0784440789 | 9eee6ca3-aa3f-4e17-bd40-2a040d5346dc--784440789 | 2.81316 | 220
Fenster | EG.- Grundriss | 2730 | 885 | 0200Mak0784440883 | 9eee6ca3-aa3f-4e17-bd40-2a040d5346dc--784440883 | 1.35065 | 220
Fenster | EG.- Grundriss | 2730 | 1760 | 0200Mak0784440868 | 9eee6ca3-aa3f-4e17-bd40-2a040d5346dc--784440868 | 2.81316 | 220
Fenster | EG.- Grundriss | 2730 | 2635 | 0200Mak0784439033 | 9eee6ca3-aa3f-4e17-bd40-2a040d5346dc--784439033 | 4.86425 | 220
Fenster | EG.- Grundriss | 2730 | 2635 | 0200Mak0784436665 | 9eee6ca3-aa3f-4e17-bd40-2a040d5346dc--784436665 | 4.86425 | 220
Fenster | EG.- Grundriss | 2730 | 885 | 0200Mak0784440775 | 9eee6ca3-aa3f-4e17-bd40-2a040d5346dc--784440775 | 1.35065 | 220
Fenster | EG.- Grundriss | 2730 | 1340.52 | 0200Mak0784439784 | 9eee6ca3-aa3f-4e17-bd40-2a040d5346dc--784439784 | 2.19065 | 220
Fenster | EG.- Grundriss | 1710 | 885 | 0200Mak0784440746 | 9eee6ca3-aa3f-4e17-bd40-2a040d5346dc--784440746 | 0.75465 | 70
Fenster | EG.- Grundriss | 2730 | 1760 | 0200Mak0784440732 | 9eee6ca3-aa3f-4e17-bd40-2a040d5346dc--784440732 | 2.81316 | 220
Fenster | EG.- Grundriss | 2730 | 1760 | 0200Mak0784440213 | 9eee6ca3-aa3f-4e17-bd40-2a040d5346dc--784440213 | 2.81316 | 220
Fenster | EG.- Grundriss | 1710 | 885 | 0200Mak0784440199 | 9eee6ca3-aa3f-4e17-bd40-2a040d5346dc--784440199 | 0.75465 | 70
Fenster | OG.- Grundriss | 2650 | 1760 | 0300Mak0784445561 | 92c99fbc-4ab2-4783-a754-1daa3fa43448--784445561 | 2.70284 | 220
Fenster | OG.- Grundriss | 1630 | 885 | 0300Mak0000000184 | 92c99fbc-4ab2-4783-a754-1daa3fa43448--184 | 0.70305 | 70
Fenster | OG.- Grundriss | 1630 | 885 | 0300Mak0000000178 | 92c99fbc-4ab2-4783-a754-1daa3fa43448--178 | 0.70305 | 70
Fenster | OG.- Grundriss | 2650 | 1760 | 0300Mak0784445544 | 92c99fbc-4ab2-4783-a754-1daa3fa43448--784445544 | 2.70284 | 220
Fenster | OG.- Grundriss | 1630 | 885 | 0300Mak0000000172 | 92c99fbc-4ab2-4783-a754-1daa3fa43448--172 | 0.70305 | 70
Fenster | OG.- Grundriss | 1630 | 885 | 0300Mak0000000166 | 92c99fbc-4ab2-4783-a754-1daa3fa43448--166 | 0.70305 | 70
Fenster | OG.- Grundriss | 2650 | 885 | 0300Mak0784445417 | 92c99fbc-4ab2-4783-a754-1daa3fa43448--784445417 | 1.29905 | 220
Fenster | OG.- Grundriss | 2650 | 885 | 0300Mak0784445403 | 92c99fbc-4ab2-4783-a754-1daa3fa43448--784445403 | 1.29905 | 220
Fenster | OG.- Grundriss | 1630 | 885 | 0300Mak0000000193 | 92c99fbc-4ab2-4783-a754-1daa3fa43448--193 | 0.70305 | 70
Fenster | OG.- Grundriss | 1630 | 885 | 0300Mak0000000189 | 92c99fbc-4ab2-4783-a754-1daa3fa43448--189 | 0.70305 | 70
Fenster | OG.- Grundriss | 2650 | 1760 | 0300Mak0000000344 | 92c99fbc-4ab2-4783-a754-1daa3fa43448--344 | 2.70284 | 220
Fenster | OG.- Grundriss | 2650 | 1760 | 0300Mak0000000351 | 92c99fbc-4ab2-4783-a754-1daa3fa43448--351 | 2.70284 | 220
Fenster | OG.- Grundriss | 2650 | 885 | 0300Mak0784442907 | 92c99fbc-4ab2-4783-a754-1daa3fa43448--784442907 | 1.29905 | 220
Fenster | OG.- Grundriss | 2650 | 1760 | 0300Mak0784442892 | 92c99fbc-4ab2-4783-a754-1daa3fa43448--784442892 | 2.79911 | 220
Fenster | OG.- Grundriss | 2650 | 1760 | 0300Mak0784444752 | 92c99fbc-4ab2-4783-a754-1daa3fa43448--784444752 | 2.79911 | 220
Fenster | OG.- Grundriss | 2650 | 885 | 0300Mak0784444736 | 92c99fbc-4ab2-4783-a754-1daa3fa43448--784444736 | 1.29905 | 220
Fenster | OG.- Grundriss | 2650 | 1760 | 0300Mak0000000325 | 92c99fbc-4ab2-4783-a754-1daa3fa43448--325 | 2.70284 | 220
Fenster | OG.- Grundriss | 1630 | 1760 | 0300Mak0784445458 | 92c99fbc-4ab2-4783-a754-1daa3fa43448--784445458 | 1.50311 | 70
Fenster | OG.- Grundriss | 2650 | 885 | 0300Mak0784445487 | 92c99fbc-4ab2-4783-a754-1daa3fa43448--784445487 | 1.29905 | 220
Fenster | OG.- Grundriss | 1630 | 1760 | 0300Mak0784445442 | 92c99fbc-4ab2-4783-a754-1daa3fa43448--784445442 | 1.50311 | 70
Fenster | OG.- Grundriss | 2650 | 885 | 0300Mak0784445473 | 92c99fbc-4ab2-4783-a754-1daa3fa43448--784445473 | 1.29905 | 220
Fenster | OG.- Grundriss | 2650 | 1067.5 | 0300Mak0784442230 | 92c99fbc-4ab2-4783-a754-1daa3fa43448--784442230 | 1.60841 | 220
Fenster | OG.- Grundriss | 2650 | 885 | 0300Mak0000000312 | 92c99fbc-4ab2-4783-a754-1daa3fa43448--312 | 1.29905 | 220
Fenster | OG.- Grundriss | 2650 | 1067.5 | 0300Mak0784442096 | 92c99fbc-4ab2-4783-a754-1daa3fa43448--784442096 | 1.60841 | 220
Fenster | OG.- Grundriss | 2650 | 1510 | 0300Mak0784444873 | 92c99fbc-4ab2-4783-a754-1daa3fa43448--784444873 | 2.32661 | 220
Fenster | OG.- Grundriss | 2650 | 885 | 0300Mak0784444766 | 92c99fbc-4ab2-4783-a754-1daa3fa43448--784444766 | 1.29905 | 220
Fenster | OG.- Grundriss | 2650 | 885 | 0300Mak0784444796 | 92c99fbc-4ab2-4783-a754-1daa3fa43448--784444796 | 1.29905 | 220
Fenster | OG.- Grundriss | 2650 | 885 | 0300Mak0784444782 | 92c99fbc-4ab2-4783-a754-1daa3fa43448--784444782 | 1.29905 | 220
Fenster | OG.- Grundriss | 1630 | 885 | 0300Mak0000000300 | 92c99fbc-4ab2-4783-a754-1daa3fa43448--300 | 0.70305 | 70
Fenster | OG.- Grundriss | 2650 | 1760 | 0300Mak0000000284 | 92c99fbc-4ab2-4783-a754-1daa3fa43448--284 | 2.70284 | 220
Fenster | OG.- Grundriss | 1630 | 885 | 0300Mak0000000278 | 92c99fbc-4ab2-4783-a754-1daa3fa43448--278 | 0.70305 | 70
Fenster | OG.- Grundriss | 2650 | 885 | 0300Mak0000000238 | 92c99fbc-4ab2-4783-a754-1daa3fa43448--238 | 1.29905 | 220
Fenster | OG.- Grundriss | 2650 | 1760 | 0300Mak0000000288 | 92c99fbc-4ab2-4783-a754-1daa3fa43448--288 | 2.79911 | 220
Fenster | OG.- Grundriss | 2650 | 885 | 0300Mak0784442393 | 92c99fbc-4ab2-4783-a754-1daa3fa43448--784442393 | 1.29905 | 220
Fenster | OG.- Grundriss | 2650 | 885 | 0300Mak0784442379 | 92c99fbc-4ab2-4783-a754-1daa3fa43448--784442379 | 1.29905 | 220
Fenster | OG.- Grundriss | 2650 | 885 | 0300Mak0000000221 | 92c99fbc-4ab2-4783-a754-1daa3fa43448--221 | 1.29905 | 220
Fenster | OG.- Grundriss | 2650 | 1760 | 0300Mak0000000285 | 92c99fbc-4ab2-4783-a754-1daa3fa43448--285 | 2.79911 | 220
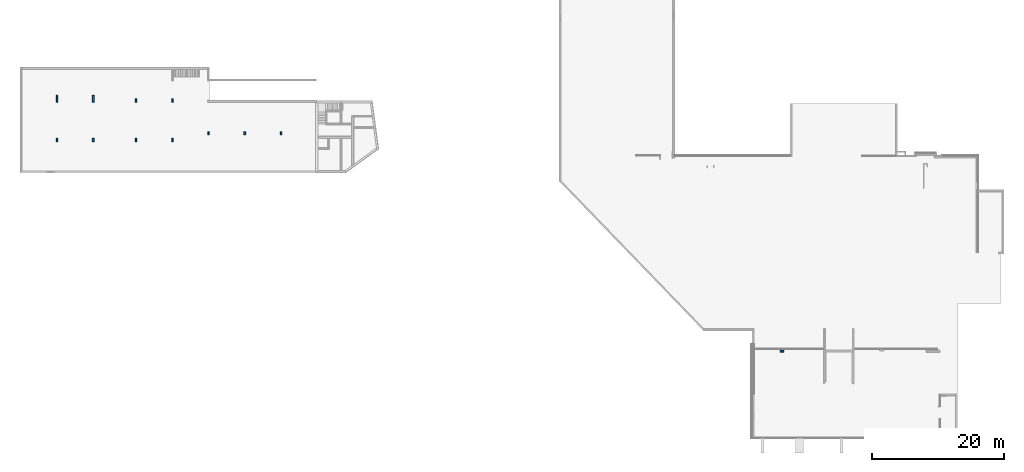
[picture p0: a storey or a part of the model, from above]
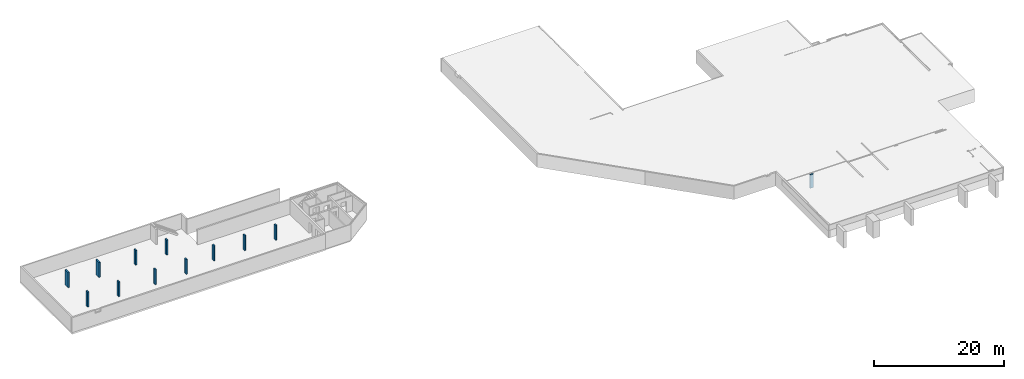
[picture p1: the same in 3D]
Properties of the parts of a building model (IFC2X3), part 4 of 4

# IfcWindow: Fenster (104)
Name | In | OverallHeight (mm) | OverallWidth (mm) | Allright_Bauteil_ID | NOI_UUID | Glasfläche | Abzug_Öffn_Unten
Fenster | OG.- Grundriss | 1630 | 885 | 0300Mak0784442303 | 92c99fbc-4ab2-4783-a754-1daa3fa43448--784442303 | 0.70305 | 70
Fenster | OG.- Grundriss | 1630 | 885 | 0300Mak0000000214 | 92c99fbc-4ab2-4783-a754-1daa3fa43448--214 | 0.70305 | 70
Fenster | OG.- Grundriss | 1630 | 885 | 0300Mak0000000225 | 92c99fbc-4ab2-4783-a754-1daa3fa43448--225 | 0.70305 | 70
Fenster | OG.- Grundriss | 2650 | 1760 | 0300Mak0000000287 | 92c99fbc-4ab2-4783-a754-1daa3fa43448--287 | 2.79911 | 220
Fenster | OG.- Grundriss | 1630 | 885 | 0300Mak0000000242 | 92c99fbc-4ab2-4783-a754-1daa3fa43448--242 | 0.70305 | 70
Fenster | DG.- Grundriss | 2768.15 | 1760 | 0500Mak0000000517 | 1bfc5a75-329c-4bd5-adfb-044822b851e1--517 | 1.88818 | 220
Fenster | DG.- Grundriss | 2273.3 | 885 | 0500Mak0000000304 | 1bfc5a75-329c-4bd5-adfb-044822b851e1--304 | 0.858325 | 70
Fenster | DG.- Grundriss | 3498.67 | 885 | 0500Mak0000000301 | 1bfc5a75-329c-4bd5-adfb-044822b851e1--301 | 1.64868 | 70
Fenster | DG.- Grundriss | 2768.15 | 1760 | 0500Mak0000000510 | 1bfc5a75-329c-4bd5-adfb-044822b851e1--510 | 1.88818 | 220
Fenster | DG.- Grundriss | 2273.3 | 885 | 0500Mak0000000298 | 1bfc5a75-329c-4bd5-adfb-044822b851e1--298 | 0.858325 | 70
Fenster | DG.- Grundriss | 3498.67 | 885 | 0500Mak0000000295 | 1bfc5a75-329c-4bd5-adfb-044822b851e1--295 | 1.64868 | 70
Fenster | DG.- Grundriss | 835.576 | 885 | 0500Mak0000000476 | 1bfc5a75-329c-4bd5-adfb-044822b851e1--476 | 0.0551486 | 220
Fenster | DG.- Grundriss | 835.576 | 885 | 0500Mak0000000471 | 1bfc5a75-329c-4bd5-adfb-044822b851e1--471 | 0.0551486 | 220
Fenster | DG.- Grundriss | 440 | 885 | 0500Mak0000000310 | 1bfc5a75-329c-4bd5-adfb-044822b851e1--310 | 0 | 70
Fenster | DG.- Grundriss | 440 | 885 | 0500Mak0000000307 | 1bfc5a75-329c-4bd5-adfb-044822b851e1--307 | 0 | 70
Fenster | DG.- Grundriss | 4181.04 | 1760 | 0500Mak0000000334 | 1bfc5a75-329c-4bd5-adfb-044822b851e1--334 | 3.83656 | 220
Fenster | DG.- Grundriss | 2955.67 | 1760 | 0500Mak0000000259 | 1bfc5a75-329c-4bd5-adfb-044822b851e1--259 | 2.14678 | 220
Fenster | DG.- Grundriss | 2741.55 | 1760 | 0500Mak0000000280 | 1bfc5a75-329c-4bd5-adfb-044822b851e1--280 | 2.91945 | 220
Fenster | DG.- Grundriss | 2741.55 | 1760 | 0500Mak0000000268 | 1bfc5a75-329c-4bd5-adfb-044822b851e1--268 | 2.91945 | 220
Fenster | DG.- Grundriss | 2741.55 | 885 | 0500Mak0000000277 | 1bfc5a75-329c-4bd5-adfb-044822b851e1--277 | 1.35534 | 220
Fenster | DG.- Grundriss | 2741.55 | 885 | 0500Mak0000000265 | 1bfc5a75-329c-4bd5-adfb-044822b851e1--265 | 1.35534 | 220
Fenster | DG.- Grundriss | 2741.37 | 885 | 0500Mak0784449210 | 1bfc5a75-329c-4bd5-adfb-044822b851e1--784449210 | 1.35523 | 220
Fenster | DG.- Grundriss | 2741.37 | 1760 | 0500Mak0784449213 | 1bfc5a75-329c-4bd5-adfb-044822b851e1--784449213 | 2.91921 | 220
Fenster | DG.- Grundriss | 2641.55 | 2635 | 0500Mak0784445373 | 1bfc5a75-329c-4bd5-adfb-044822b851e1--784445373 | 4.64865 | 220
Fenster | DG.- Grundriss | 2641.55 | 2635 | 0500Mak0784445364 | 1bfc5a75-329c-4bd5-adfb-044822b851e1--784445364 | 4.64865 | 220
Fenster | DG.- Grundriss | 1985.89 | 885 | 0500Mak0000000451 | 1bfc5a75-329c-4bd5-adfb-044822b851e1--451 | 0.760047 | 220
Fenster | DG.- Grundriss | 1985.89 | 885 | 0500Mak0000000444 | 1bfc5a75-329c-4bd5-adfb-044822b851e1--444 | 0.760047 | 220
Fenster | DG.- Grundriss | 965.887 | 885 | 0500Mak0000000331 | 1bfc5a75-329c-4bd5-adfb-044822b851e1--331 | 0.164047 | 70
Fenster | DG.- Grundriss | 1985.89 | 1760 | 0500Mak0000000328 | 1bfc5a75-329c-4bd5-adfb-044822b851e1--328 | 1.55046 | 220
Fenster | DG.- Grundriss | 965.887 | 885 | 0500Mak0000000325 | 1bfc5a75-329c-4bd5-adfb-044822b851e1--325 | 0.164047 | 70
